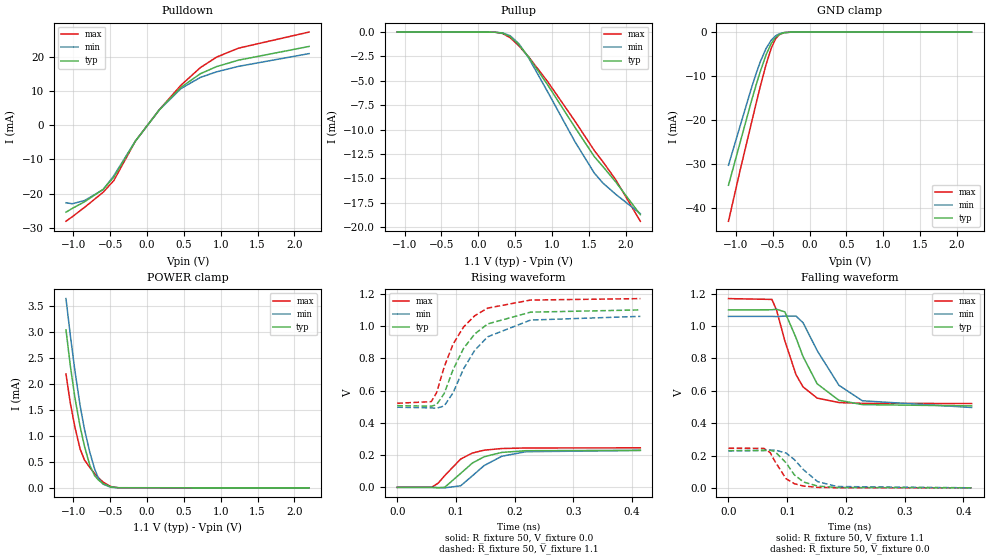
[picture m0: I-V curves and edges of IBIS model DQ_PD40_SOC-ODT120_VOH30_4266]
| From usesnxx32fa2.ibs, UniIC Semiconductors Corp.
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| DQ_PD40_SOC-ODT120_VOH30_4266
| (40 Ohm Pulldown, 120 Ohm System ODT Setting, VOH=VDDQ/3.0, 3200-4266Mbps)
[Model]   DQ_PD40_SOC-ODT120_VOH30_4266
Model_type   I/O
Vinl = 123.333mV
Vinh = 243.333mV
Vmeas = 183.333mV
Vref = 0.0mV
Cref = 0.0pF
Rref = 120.000Ohm
|   typ   min   max
|C_comp   0.834pF   0.784pF   0.884pF
C_comp_pullup   0.4170pF   0.3920pF   0.4420pF
C_comp_pulldown   0.4170pF   0.3920pF   0.4420pF
| Note: C_comp changes when the ODT circuit is enabled.
[Model Spec]
| Input threshold voltage corners
Vinl   0.1233V   0.1167V   0.1350V
Vinh   0.2433V   0.2367V   0.2550V
| Measurement voltage corners
Vmeas   0.1833V   0.1767V   0.1950V
| Timing spec test load voltage corners
Vref   0.0000V   0.0000V   0.0000V
| Dynamic Overshoot Parameters from LPDDR4 Specification
D_overshoot_ampl_h   0.30   NA   NA
D_overshoot_ampl_l   0.30   NA   NA
D_overshoot_area_h   0.1n   NA   NA
D_overshoot_area_l   0.1n   NA   NA
[Voltage Range]   1.1000V   1.0600V   1.1700V
[Pullup Reference]   1.1000V   1.0600V   1.1700V
| Junction Temperature (Ambient temp is 35C typ 95C min -40C max)
[Temperature Range]   50.0   110.0   -40.0
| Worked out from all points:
|   slope of the pulldown table from 0 to 0.165 V, typ, clamps not added: 37 ohm
|   slope of the pullup table from 0 to 0.165 V, typ, clamps not added: 39.1 kohm
|   GND clamp passes 1 mA (typ) near -0.45 V on its own axis
|   POWER clamp passes 1 mA (typ) near -0.88 V on its own axis
|   rising waveform, R_fixture 50, V_fixture 0.0: 20-80 % time 46.5ps typ, 50.5ps min, 41.5ps max; typ from 0 V to 0.23 V
|   falling waveform, R_fixture 50, V_fixture 1.1: 20-80 % time 45.3ps typ, 56.8ps min, 35.6ps max; typ from 1.1 V to 0.507 V
|   rising waveform, R_fixture 50, V_fixture 1.1: 20-80 % time 56.7ps typ, 61.2ps min, 52ps max; typ from 0.507 V to 1.1 V
|   falling waveform, R_fixture 50, V_fixture 0.0: 20-80 % time 30.4ps typ, 38.5ps min, 25.6ps max; typ from 0.23 V to 0 V
[Pulldown]
|   Voltage   I(typ)   I(min)   I(max)
-1.1V     -25.37mA   -22.63mA   -28.03mA
-1.014V   -24.28mA   -22.92mA   -26.7mA
-845.9mV  -22.31mA   -21.96mA   -23.93mA
-595.1mV  -18.71mA   -18.78mA   -19.56mA
-449.9mV  -15.13mA   -14.73mA   -16.13mA
-159.5mV  -4.688mA   -4.687mA   -4.702mA
167.2mV   4.501mA    4.462mA    4.525mA
460.9mV   11.05mA    10.69mA    11.67mA
724.9mV   15.03mA    13.95mA    16.82mA
946mV     17.11mA    15.58mA    19.88mA
1.24V     18.97mA    17.16mA    22.47mA
2.2V      22.98mA    20.89mA    27.18mA
[GND Clamp]
|   Voltage   I(typ)   I(min)   I(max)
-1.1V     -34.74mA   -30.21mA   -42.91mA
-938.3mV  -24.81mA   -21.07mA   -31.08mA
-793.1mV  -15.92mA   -12.96mA   -20.95mA
-727.1mV  -12.12mA   -9.513mA   -16.33mA
-667.7mV  -8.907mA   -6.722mA   -12.29mA
-588.5mV  -5.112mA   -3.681mA   -7.299mA
-519.2mV  -2.567mA   -1.832mA   -3.66mA
-463.1mV  -1.235mA   -898.9uA   -1.597mA
-413.6mV  -566uA     -417.2uA   -621.1uA
-344.3mV  -143.8uA   -109.4uA   -125.2uA
-232.1mV  -7.402uA   -7.068uA   -4.018uA
2.2V      0A         0A         0A
[Pullup]
|   Voltage   I(typ)   I(min)   I(max)
-1.1V     2.092uA    3.224uA    943.2nA
229.9mV   -15.02uA   -15.37uA   -15.53uA
332.2mV   -107.6uA   -89.94uA   -148.2uA
434.5mV   -465.7uA   -380.9uA   -589.6uA
553.3mV   -1.313mA   -1.213mA   -1.422mA
685.3mV   -2.584mA   -2.664mA   -2.556mA
942.7mV   -5.422mA   -6.135mA   -5.087mA
1.312V    -9.759mA   -11.23mA   -9.123mA
1.576V    -12.77mA   -14.46mA   -12.15mA
1.692V    -13.78mA   -15.47mA   -13.29mA
1.867V    -15.37mA   -16.63mA   -15.15mA
2.2V      -18.72mA   -18.61mA   -19.39mA
[POWER Clamp]
|   Voltage   I(typ)   I(min)   I(max)
-1.1V     3.033mA    3.633mA    2.184mA
-1.041V   2.345mA    2.929mA    1.625mA
-977.9mV  1.723mA    2.241mA    1.16mA
-908.6mV  1.178mA    1.582mA    747.9uA
-849.2mV  799uA      1.125mA    535.4uA
-776.6mV  434.1uA    683.3uA    390.2uA
-710.6mV  232.2uA    359.1uA    273.1uA
-657.8mV  146.8uA    178.9uA    190.7uA
-598.4mV  83.64uA    71.98uA    113uA
-496.1mV  20.06uA    12.3uA     25.72uA
-387.2mV  1.914uA    1.296uA    1.609uA
2.2V      0A         0A         0A
[Ramp]
|   typ   min   max
| 20% - 80%
dV/dt_r   137.80m/46.47p   137.36m/50.47p   146.99m/41.48p
dV/dt_f   356.03m/45.27p   337.76m/56.84p   389.18m/35.54p
| 25% - 75%
|dV/dt_r   114.84m/37.07p   114.46m/40.32p   122.49m/32.94p
|dV/dt_f   296.69m/36.12p   281.47m/45.43p   324.32m/28.29p
R_load = 50
[Rising Waveform]
R_fixture = 50
V_fixture = 0.0
|   Time   V(typ)   V(min)   V(max)
0s        169.8uV    127.4uV    131.4uV
59ps      -591.4uV   361.4uV    1.587mV
70ps      -2.672mV   -883.6uV   26.98mV
81ps      1.084mV    -2.735mV   73.35mV
108ps     86.65mV    9.855mV    175.6mV
128ps     150.9mV    71.76mV    212.9mV
148ps     189.8mV    135.3mV    230.7mV
178ps     216.7mV    192.8mV    240.9mV
219ps     227.3mV    221.1mV    244.3mV
414ps     229.8mV    229.1mV    245.1mV
[Falling Waveform]
R_fixture   = 50
V_fixture   = 1.1
V_fixture_min = 1.06
V_fixture_max = 1.17
|   Time   V(typ)   V(min)   V(max)
0s        1.1V       1.06V      1.17V
74ps      1.101V     1.06V      1.165V
82ps      1.104V     1.059V     1.097V
96ps      1.088V     1.062V     908.8mV
115ps     927.6mV    1.062V     699.9mV
127ps     811.5mV    1.021V     624.2mV
151ps     643.3mV    848.8mV    554.9mV
188ps     541.5mV    634.4mV    527.4mV
228ps     514.6mV    538.3mV    522.3mV
414ps     506.6mV    497mV      521.4mV
[Rising Waveform]
R_fixture   = 50
V_fixture   = 1.1
V_fixture_min = 1.06
V_fixture_max = 1.17
|   Time   V(typ)   V(min)   V(max)
0s        506.5mV    496.8mV    521.3mV
58ps      503.3mV    492.8mV    531.4mV
67ps      512.6mV    490.5mV    586.7mV
80ps      581.8mV    504.7mV    747mV
95ps      729.1mV    585.6mV    887.2mV
113ps     861.7mV    735.1mV    994.5mV
132ps     950.7mV    849.8mV    1.064V
154ps     1.013V     933.3mV    1.111V
227ps     1.086V     1.037V     1.161V
414ps     1.1V       1.06V      1.17V
[Falling Waveform]
R_fixture = 50
V_fixture = 0.0
|   Time   V(typ)   V(min)   V(max)
0s        229.9mV    229.2mV    245.2mV
60ps      232.6mV    230mV      244.3mV
71ps      232.3mV    233.1mV    217.7mV
79ps      224.6mV    234mV      164.4mV
98ps      155.3mV    215.2mV    56.71mV
112ps     81.04mV    175.4mV    26.17mV
128ps     35.78mV    111.1mV    10.99mV
152ps     10.71mV    38.17mV    3.147mV
185ps     2.325mV    8.199mV    686.1uV
414ps     237.5uV    227.7uV    152.8uV
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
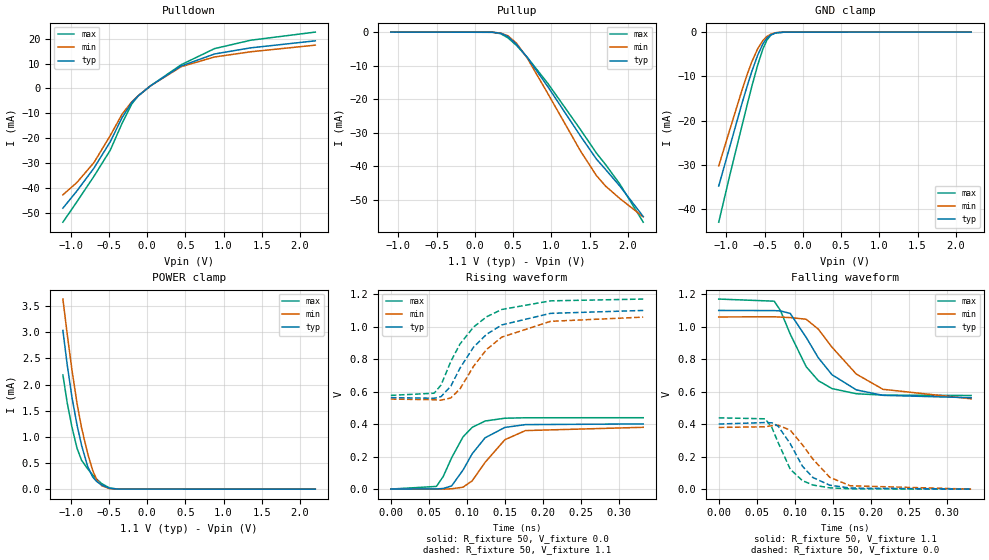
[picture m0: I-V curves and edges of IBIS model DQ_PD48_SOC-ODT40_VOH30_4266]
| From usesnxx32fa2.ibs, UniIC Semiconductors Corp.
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| DQ_PD48_SOC-ODT40_VOH30_4266
| (48 Ohm Pulldown, 40 Ohm System ODT Setting, VOH=VDDQ/3.0, 3200-4266Mbps)
[Model]   DQ_PD48_SOC-ODT40_VOH30_4266
Model_type   I/O
Vinl = 123.333mV
Vinh = 243.333mV
Vmeas = 183.333mV
Vref = 0.0mV
Cref = 0.0pF
Rref = 40.000Ohm
|   typ   min   max
|C_comp   0.834pF   0.784pF   0.884pF
C_comp_pullup   0.4170pF   0.3920pF   0.4420pF
C_comp_pulldown   0.4170pF   0.3920pF   0.4420pF
| Note: C_comp changes when the ODT circuit is enabled.
[Model Spec]
| Input threshold voltage corners
Vinl   0.1233V   0.1167V   0.1350V
Vinh   0.2433V   0.2367V   0.2550V
| Measurement voltage corners
Vmeas   0.1833V   0.1767V   0.1950V
| Timing spec test load voltage corners
Vref   0.0000V   0.0000V   0.0000V
| Dynamic Overshoot Parameters from LPDDR4 Specification
D_overshoot_ampl_h   0.30   NA   NA
D_overshoot_ampl_l   0.30   NA   NA
D_overshoot_area_h   0.1n   NA   NA
D_overshoot_area_l   0.1n   NA   NA
[Voltage Range]   1.1000V   1.0600V   1.1700V
[Pullup Reference]   1.1000V   1.0600V   1.1700V
| Junction Temperature (Ambient temp is 35C typ 95C min -40C max)
[Temperature Range]   50.0   110.0   -40.0
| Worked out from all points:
|   slope of the pulldown table from 0 to 0.165 V, typ, clamps not added: 43.8 ohm
|   slope of the pullup table from 0 to 0.165 V, typ, clamps not added: 13 kohm
|   GND clamp passes 1 mA (typ) near -0.45 V on its own axis
|   POWER clamp passes 1 mA (typ) near -0.88 V on its own axis
|   rising waveform, R_fixture 50, V_fixture 0.0: 20-80 % time 34.7ps typ, 38.8ps min, 30.2ps max; typ from 0.001 V to 0.401 V
|   falling waveform, R_fixture 50, V_fixture 1.1: 20-80 % time 49.3ps typ, 61.2ps min, 39.2ps max; typ from 1.1 V to 0.563 V
|   rising waveform, R_fixture 50, V_fixture 1.1: 20-80 % time 55.5ps typ, 58.1ps min, 51.7ps max; typ from 0.563 V to 1.1 V
|   falling waveform, R_fixture 50, V_fixture 0.0: 20-80 % time 32.5ps typ, 40ps min, 27.6ps max; typ from 0.401 V to 0.001 V
[Pulldown]
|   Voltage   I(typ)   I(min)   I(max)
-1.1V     -48.22mA   -42.85mA   -53.87mA
-918.5mV  -41.36mA   -37.93mA   -45.72mA
-694.1mV  -32.1mA    -29.86mA   -35.4mA
-479.6mV  -21.39mA   -18.92mA   -24.8mA
-324.5mV  -11.65mA   -10.29mA   -13.91mA
-199.1mV  -5.64mA    -5.359mA   -6.219mA
-113.3mV  -2.927mA   -2.884mA   -2.961mA
45.1mV    1.047mA    1.044mA    1.045mA
447.7mV   9.071mA    8.78mA     9.581mA
883.3mV   13.89mA    12.68mA    16.05mA
1.355V    16.35mA    14.77mA    19.42mA
2.2V      19.18mA    17.44mA    22.7mA
[GND Clamp]
|   Voltage   I(typ)   I(min)   I(max)
-1.1V     -34.74mA   -30.21mA   -42.91mA
-941.6mV  -25.02mA   -21.26mA   -31.32mA
-799.7mV  -16.31mA   -13.32mA   -21.42mA
-723.8mV  -11.94mA   -9.348mA   -16.1mA
-667.7mV  -8.907mA   -6.722mA   -12.29mA
-591.8mV  -5.255mA   -3.789mA   -7.493mA
-522.5mV  -2.665mA   -1.902mA   -3.811mA
-469.7mV  -1.357mA   -985.1uA   -1.788mA
-416.9mV  -596.7uA   -440.1uA   -664.7uA
-354.2mV  -178.1uA   -134.8uA   -159.9uA
-235.4mV  -8.186uA   -7.681uA   -4.491uA
2.2V      0A         0A         0A
[Pullup]
|   Voltage   I(typ)   I(min)   I(max)
-1.1V     6.275uA    9.671uA    2.829uA
229.9mV   -45.14uA   -46.16uA   -46.64uA
335.5mV   -340.5uA   -282.4uA   -468.8uA
431.2mV   -1.333mA   -1.089mA   -1.693mA
543.4mV   -3.63mA    -3.312mA   -3.978mA
685.3mV   -7.607mA   -7.806mA   -7.548mA
955.9mV   -16.38mA   -18.46mA   -15.4mA
1.378V    -30.95mA   -35.41mA   -29.04mA
1.589V    -37.92mA   -42.84mA   -36.13mA
1.708V    -41mA      -45.97mA   -39.55mA
1.893V    -45.92mA   -49.65mA   -45.31mA
2.2V      -55.05mA   -55.15mA   -56.74mA
[POWER Clamp]
|   Voltage   I(typ)   I(min)   I(max)
-1.1V     3.033mA    3.633mA    2.184mA
-1.044V   2.381mA    2.967mA    1.653mA
-981.2mV  1.753mA    2.275mA    1.183mA
-915.2mV  1.224mA    1.639mA    781.4uA
-855.8mV  837.6uA    1.171mA    552.2uA
-776.6mV  434.3uA    683.3uA    390.2uA
-710.6mV  232.2uA    359uA      273.1uA
-657.8mV  146.8uA    178.8uA    190.6uA
-591.8mV  77.9uA     64.81uA    105.5uA
-489.5mV  17.75uA    10.81uA    22.48uA
-380.6mV  1.603uA    1.131uA    1.341uA
2.2V      0A         0A         0A
[Ramp]
|   typ   min   max
| 20% - 80%
dV/dt_r   240.28m/34.75p   227.83m/38.76p   263.33m/30.20p
dV/dt_f   322.12m/49.32p   302.17m/61.19p   355.99m/39.15p
| 25% - 75%
|dV/dt_r   200.24m/27.67p   189.86m/30.88p   219.44m/23.94p
|dV/dt_f   268.43m/39.31p   251.80m/48.83p   296.66m/31.17p
R_load = 50
[Rising Waveform]
R_fixture = 50
V_fixture = 0.0
|   Time   V(typ)   V(min)   V(max)
0s        619.1uV    536.6uV    450.1uV
60ps      1.042mV    -84.49uV   16.73mV
69ps      4.083mV    -175.8uV   78.14mV
80ps      19.77mV    2.236mV    193.1mV
95ps      117.6mV    11.96mV    321.6mV
107ps     217.2mV    51mV       379.9mV
124ps     315.7mV    164.6mV    418.9mV
150ps     379.5mV    303.8mV    436.1mV
177ps     396.8mV    360.1mV    439mV
332ps     401.1mV    380.3mV    439.3mV
[Falling Waveform]
R_fixture   = 50
V_fixture   = 1.1
V_fixture_min = 1.06
V_fixture_max = 1.17
|   Time   V(typ)   V(min)   V(max)
0s        1.1V       1.06V      1.17V
73ps      1.099V     1.061V     1.157V
81ps      1.097V     1.059V     1.101V
94ps      1.082V     1.056V     954.9mV
115ps     934.4mV    1.046V     754.1mV
131ps     808.8mV    985mV      668.1mV
149ps     704.4mV    873.8mV    619.1mV
181ps     611.3mV    708.5mV    587.5mV
216ps     577.7mV    614.8mV    579.2mV
332ps     563.1mV    556.4mV    576.7mV
[Rising Waveform]
R_fixture   = 50
V_fixture   = 1.1
V_fixture_min = 1.06
V_fixture_max = 1.17
|   Time   V(typ)   V(min)   V(max)
0s        562.8mV    553.9mV    576.6mV
57ps      559mV      549.8mV    590mV
66ps      568.8mV    547mV      640mV
79ps      633.7mV    560.8mV    785.9mV
91ps      744.4mV    616.5mV    892.7mV
109ps     874.4mV    756.8mV    997.7mV
126ps     952.2mV    859mV      1.06V
146ps     1.01V      934.9mV    1.105V
210ps     1.081V     1.032V     1.158V
332ps     1.099V     1.058V     1.169V
[Falling Waveform]
R_fixture = 50
V_fixture = 0.0
|   Time   V(typ)   V(min)   V(max)
0s        401.2mV    380.4mV    439.4mV
61ps      410.3mV    384.3mV    433.3mV
70ps      408.7mV    391.1mV    378.8mV
78ps      388.8mV    394mV      288.8mV
94ps      280.8mV    363.6mV    123.8mV
110ps     142.2mV    274.1mV    53.17mV
124ps     71.85mV    184.8mV    25.79mV
146ps     24.83mV    73.47mV    8.582mV
173ps     7.298mV    21.37mV    2.537mV
332ps     679.4uV    647.7uV    471uV
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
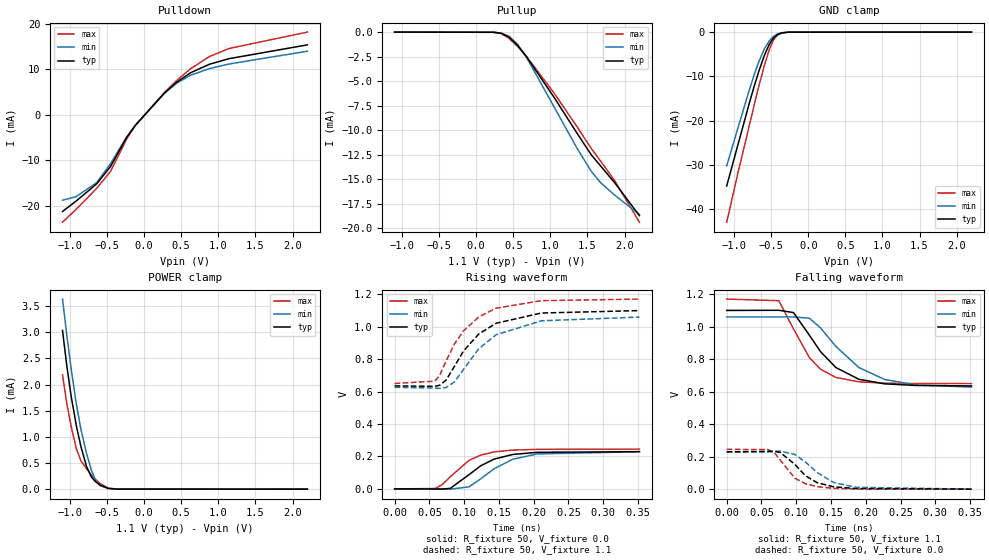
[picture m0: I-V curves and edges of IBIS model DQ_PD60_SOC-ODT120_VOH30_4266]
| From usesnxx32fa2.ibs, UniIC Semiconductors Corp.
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| DQ_PD60_SOC-ODT120_VOH30_4266
| (60 Ohm Pulldown, 120 Ohm System ODT Setting, VOH=VDDQ/3.0, 3200-4266Mbps)
[Model]   DQ_PD60_SOC-ODT120_VOH30_4266
Model_type   I/O
Vinl = 123.333mV
Vinh = 243.333mV
Vmeas = 183.333mV
Vref = 0.0mV
Cref = 0.0pF
Rref = 120.000Ohm
|   typ   min   max
|C_comp   0.834pF   0.784pF   0.884pF
C_comp_pullup   0.4170pF   0.3920pF   0.4420pF
C_comp_pulldown   0.4170pF   0.3920pF   0.4420pF
| Note: C_comp changes when the ODT circuit is enabled.
[Model Spec]
| Input threshold voltage corners
Vinl   0.1233V   0.1167V   0.1350V
Vinh   0.2433V   0.2367V   0.2550V
| Measurement voltage corners
Vmeas   0.1833V   0.1767V   0.1950V
| Timing spec test load voltage corners
Vref   0.0000V   0.0000V   0.0000V
| Dynamic Overshoot Parameters from LPDDR4 Specification
D_overshoot_ampl_h   0.30   NA   NA
D_overshoot_ampl_l   0.30   NA   NA
D_overshoot_area_h   0.1n   NA   NA
D_overshoot_area_l   0.1n   NA   NA
[Voltage Range]   1.1000V   1.0600V   1.1700V
[Pullup Reference]   1.1000V   1.0600V   1.1700V
| Junction Temperature (Ambient temp is 35C typ 95C min -40C max)
[Temperature Range]   50.0   110.0   -40.0
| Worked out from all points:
|   slope of the pulldown table from 0 to 0.165 V, typ, clamps not added: 55 ohm
|   slope of the pullup table from 0 to 0.165 V, typ, clamps not added: 39.2 kohm
|   GND clamp passes 1 mA (typ) near -0.45 V on its own axis
|   POWER clamp passes 1 mA (typ) near -0.88 V on its own axis
|   rising waveform, R_fixture 50, V_fixture 0.0: 20-80 % time 47.1ps typ, 51.2ps min, 41.8ps max; typ from 0 V to 0.23 V
|   falling waveform, R_fixture 50, V_fixture 1.1: 20-80 % time 53.3ps typ, 65ps min, 42.9ps max; typ from 1.1 V to 0.635 V
|   rising waveform, R_fixture 50, V_fixture 1.1: 20-80 % time 56.3ps typ, 60.3ps min, 52.3ps max; typ from 0.635 V to 1.1 V
|   falling waveform, R_fixture 50, V_fixture 0.0: 20-80 % time 35ps typ, 42.4ps min, 30.4ps max; typ from 0.23 V to 0 V
[Pulldown]
|   Voltage   I(typ)   I(min)   I(max)
-1.1V     -21.25mA   -18.78mA   -23.61mA
-918.5mV  -19mA      -18.02mA   -20.81mA
-638mV    -15.16mA   -14.89mA   -16.16mA
-453.2mV  -11.38mA   -10.78mA   -12.45mA
-235.4mV  -4.998mA   -4.872mA   -5.302mA
-116.6mV  -2.307mA   -2.303mA   -2.296mA
276.1mV   4.816mA    4.74mA     4.918mA
437.8mV   7.121mA    6.906mA    7.497mA
625.9mV   9.213mA    8.675mA    10.1mA
880mV     11.08mA    10.12mA    12.78mA
1.144V    12.31mA    11.14mA    14.54mA
2.2V      15.34mA    13.95mA    18.15mA
[GND Clamp]
|   Voltage   I(typ)   I(min)   I(max)
-1.1V     -34.74mA   -30.21mA   -42.91mA
-948.2mV  -25.43mA   -21.63mA   -31.79mA
-793.1mV  -15.92mA   -12.96mA   -20.95mA
-723.8mV  -11.93mA   -9.348mA   -16.1mA
-664.4mV  -8.736mA   -6.578mA   -12.07mA
-591.8mV  -5.254mA   -3.789mA   -7.492mA
-525.8mV  -2.766mA   -1.974mA   -3.964mA
-469.7mV  -1.356mA   -986uA     -1.787mA
-416.9mV  -597.3uA   -440.2uA   -665.1uA
-357.5mV  -190.9uA   -145.2uA   -173.7uA
-265.1mV  -19.48uA   -16.92uA   -12.31uA
2.2V      0A         0A         0A
[Pullup]
|   Voltage   I(typ)   I(min)   I(max)
-1.1V     2.092uA    3.224uA    943.2nA
233.2mV   -16.12uA   -16.27uA   -16.87uA
335.5mV   -114uA     -94.77uA   -157uA
441.1mV   -501.8uA   -411.9uA   -628.2uA
556.6mV   -1.342mA   -1.243mA   -1.448mA
678.7mV   -2.516mA   -2.582mA   -2.496mA
1.055V    -6.719mA   -7.703mA   -6.276mA
1.362V    -10.35mA   -11.89mA   -9.685mA
1.553V    -12.54mA   -14.22mA   -11.89mA
1.675V    -13.64mA   -15.35mA   -13.14mA
1.867V    -15.37mA   -16.63mA   -15.15mA
2.2V      -18.72mA   -18.61mA   -19.39mA
[POWER Clamp]
|   Voltage   I(typ)   I(min)   I(max)
-1.1V     3.033mA    3.633mA    2.184mA
-1.041V   2.345mA    2.929mA    1.625mA
-984.5mV  1.782mA    2.31mA     1.205mA
-911.9mV  1.201mA    1.61mA     764.1uA
-852.5mV  818.2uA    1.148mA    543.5uA
-776.6mV  434.1uA    683.3uA    390.2uA
-710.6mV  232.2uA    359uA      273.1uA
-657.8mV  146.8uA    178.8uA    190.6uA
-595.1mV  80.78uA    68.3uA     109.2uA
-482.9mV  15.69uA    9.499uA    19.51uA
-364.1mV  1.098uA    819.7nA    867nA
2.2V      0A         0A         0A
[Ramp]
|   typ   min   max
| 20% - 80%
dV/dt_r   137.76m/47.06p   137.31m/51.22p   146.97m/41.83p
dV/dt_f   278.79m/53.28p   259.05m/65.05p   312.06m/42.98p
| 25% - 75%
|dV/dt_r   114.80m/37.54p   114.43m/40.90p   122.47m/33.22p
|dV/dt_f   232.32m/42.47p   215.88m/51.80p   260.05m/34.24p
R_load = 50
[Rising Waveform]
R_fixture = 50
V_fixture = 0.0
|   Time   V(typ)   V(min)   V(max)
0s        225.3uV    184.2uV    168.8uV
58ps      -235.5uV   253.1uV    2.338mV
68ps      -877.8uV   -528.5uV   24.86mV
80ps      3.421mV    -1.491mV   74.85mV
107ps     87.78mV    12.87mV    175.8mV
124ps     143.1mV    62.63mV    208.8mV
143ps     183.7mV    124.3mV    228.2mV
170ps     212.5mV    182.9mV    239.5mV
205ps     225.5mV    215.6mV    243.8mV
352ps     229.8mV    229mV      245.1mV
[Falling Waveform]
R_fixture   = 50
V_fixture   = 1.1
V_fixture_min = 1.06
V_fixture_max = 1.17
|   Time   V(typ)   V(min)   V(max)
0s        1.1V       1.06V      1.17V
75ps      1.101V     1.06V      1.16V
96ps      1.087V     1.06V      986.5mV
119ps     947mV      1.052V     809.1mV
135ps     846.2mV    992.1mV    738mV
157ps     748.6mV    878.7mV    687.9mV
190ps     676.5mV    748.8mV    660.6mV
227ps     648.3mV    675.4mV    652.5mV
272ps     638.4mV    641.6mV    650.3mV
352ps     635.4mV    628.2mV    649.9mV
[Rising Waveform]
R_fixture   = 50
V_fixture   = 1.1
V_fixture_min = 1.06
V_fixture_max = 1.17
|   Time   V(typ)   V(min)   V(max)
0s        635mV      626.1mV    649.8mV
58ps      632.2mV    621.6mV    664.1mV
65ps      639.4mV    619.9mV    702.1mV
74ps      670.3mV    624.7mV    787.4mV
86ps      755.2mV    659.1mV    892.9mV
99ps      849.6mV    735.8mV    973.7mV
121ps     954.6mV    864mV      1.06V
146ps     1.021V     950.2mV    1.114V
211ps     1.084V     1.036V     1.16V
352ps     1.099V     1.059V     1.17V
[Falling Waveform]
R_fixture = 50
V_fixture = 0.0
|   Time   V(typ)   V(min)   V(max)
0s        229.9mV    229.2mV    245.2mV
59ps      232.6mV    229.9mV    244.5mV
69ps      232.8mV    232.8mV    222.5mV
77ps      226.2mV    234.3mV    179.5mV
98ps      152.9mV    213.6mV    67.75mV
113ps     83.32mV    168mV      33.78mV
130ps     40.1mV     102.6mV    15.5mV
154ps     14.49mV    40.75mV    5.262mV
186ps     3.913mV    11.43mV    1.37mV
352ps     303.3uV    314.6uV    191.7uV
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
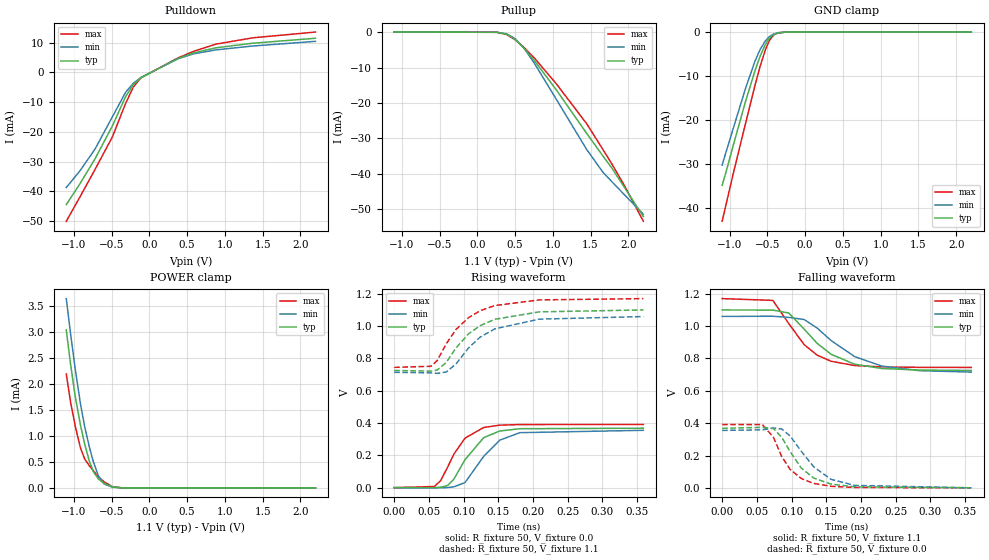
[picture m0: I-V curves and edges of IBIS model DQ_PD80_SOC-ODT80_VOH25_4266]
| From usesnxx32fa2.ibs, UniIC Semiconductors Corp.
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| DQ_PD80_SOC-ODT80_VOH25_4266
| (80 Ohm Pulldown, 80 Ohm System ODT Setting, VOH=VDDQ/2.5, 3200-4266Mbps)
[Model]   DQ_PD80_SOC-ODT80_VOH25_4266
Model_type   I/O
Vinl = 160.000mV
Vinh = 280.000mV
Vmeas = 220.000mV
Vref = 0.0mV
Cref = 0.0pF
Rref = 80.000Ohm
|   typ   min   max
|C_comp   0.834pF   0.784pF   0.884pF
C_comp_pullup   0.4170pF   0.3920pF   0.4420pF
C_comp_pulldown   0.4170pF   0.3920pF   0.4420pF
| Note: C_comp changes when the ODT circuit is enabled.
[Model Spec]
| Input threshold voltage corners
Vinl   0.1600V   0.1520V   0.1740V
Vinh   0.2800V   0.2720V   0.2940V
| Measurement voltage corners
Vmeas   0.2200V   0.2120V   0.2340V
| Timing spec test load voltage corners
Vref   0.0000V   0.0000V   0.0000V
| Dynamic Overshoot Parameters from LPDDR4 Specification
D_overshoot_ampl_h   0.30   NA   NA
D_overshoot_ampl_l   0.30   NA   NA
D_overshoot_area_h   0.1n   NA   NA
D_overshoot_area_l   0.1n   NA   NA
[Voltage Range]   1.1000V   1.0600V   1.1700V
[Pullup Reference]   1.1000V   1.0600V   1.1700V
| Junction Temperature (Ambient temp is 35C typ 95C min -40C max)
[Temperature Range]   50.0   110.0   -40.0
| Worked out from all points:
|   slope of the pulldown table from 0 to 0.165 V, typ, clamps not added: 73.8 ohm
|   slope of the pullup table from 0 to 0.165 V, typ, clamps not added: 17.5 kohm
|   GND clamp passes 1 mA (typ) near -0.45 V on its own axis
|   POWER clamp passes 1 mA (typ) near -0.88 V on its own axis
|   rising waveform, R_fixture 50, V_fixture 0.0: 20-80 % time 35.1ps typ, 38.9ps min, 32ps max; typ from 0.001 V to 0.368 V
|   falling waveform, R_fixture 50, V_fixture 1.1: 20-80 % time 58ps typ, 69ps min, 47.3ps max; typ from 1.1 V to 0.726 V
|   rising waveform, R_fixture 50, V_fixture 1.1: 20-80 % time 54.9ps typ, 56.7ps min, 51.7ps max; typ from 0.726 V to 1.1 V
|   falling waveform, R_fixture 50, V_fixture 0.0: 20-80 % time 38.3ps typ, 44.3ps min, 32.9ps max; typ from 0.368 V to 0.001 V
[Pulldown]
|   Voltage   I(typ)   I(min)   I(max)
-1.1V     -44.48mA   -38.75mA   -50.1mA
-921.8mV  -37.58mA   -33.22mA   -42.04mA
-720.5mV  -29.14mA   -25.86mA   -32.73mA
-489.5mV  -18.03mA   -14.96mA   -21.71mA
-314.6mV  -8.178mA   -6.693mA   -10.48mA
-212.3mV  -4.114mA   -3.666mA   -4.927mA
-110mV    -1.768mA   -1.705mA   -1.812mA
381.7mV   4.717mA    4.613mA    4.889mA
589.6mV   6.577mA    6.251mA    7.117mA
883.3mV   8.277mA    7.574mA    9.509mA
1.368V    9.806mA    8.868mA    11.62mA
2.2V      11.48mA    10.44mA    13.57mA
[GND Clamp]
|   Voltage   I(typ)   I(min)   I(max)
-1.1V     -34.75mA   -30.2mA    -42.92mA
-1.05V    -31.86mA   -27.33mA   -39.27mA
-948.2mV  -25.44mA   -21.62mA   -31.8mA
-789.8mV  -15.73mA   -12.78mA   -20.73mA
-664.4mV  -8.74mA    -6.576mA   -12.08mA
-595.1mV  -5.401mA   -3.898mA   -7.695mA
-525.8mV  -2.768mA   -1.974mA   -3.966mA
-473mV    -1.422mA   -1.031mA   -1.89mA
-416.9mV  -600.9uA   -440.5uA   -665.8uA
-357.5mV  -192.8uA   -144.2uA   -174uA
-248.6mV  -12.2uA    -10.93uA   -7.146uA
2.2V      0A         0A         0A
[Pullup]
|   Voltage   I(typ)   I(min)   I(max)
-1.1V     4.106uA    7.431uA    1.361uA
259.6mV   -60.57uA   -59.49uA   -61.51uA
388.3mV   -576.6uA   -480.7uA   -687.8uA
500.5mV   -2.04mA    -1.831mA   -2.142mA
619.3mV   -4.529mA   -4.567mA   -4.328mA
754.6mV   -7.982mA   -8.738mA   -7.279mA
1.042V    -16.16mA   -18.8mA    -14.47mA
1.448V    -28.55mA   -33.09mA   -25.83mA
1.662V    -34.9mA    -39.5mA    -33.05mA
1.788V    -38.54mA   -42.33mA   -37.4mA
1.943V    -43.63mA   -45.77mA   -43.12mA
2.2V      -52.05mA   -51.39mA   -53.39mA
[POWER Clamp]
|   Voltage   I(typ)   I(min)   I(max)
-1.1V     3.033mA    3.633mA    2.184mA
-1.044V   2.381mA    2.967mA    1.653mA
-981.2mV  1.752mA    2.276mA    1.183mA
-911.9mV  1.201mA    1.611mA    764.5uA
-855.8mV  837.8uA    1.172mA    552.1uA
-796.4mV  521.2uA    795.3uA    427.2uA
-743.6mV  316uA      510.6uA    330.1uA
-674.3mV  169.2uA    226uA      215.1uA
-598.4mV  83.65uA    71.95uA    113.1uA
-486.2mV  16.75uA    10.13uA    20.98uA
-367.4mV  1.201uA    871.3nA    948.2nA
2.2V      0A         0A         0A
[Ramp]
|   typ   min   max
| 20% - 80%
dV/dt_r   220.51m/35.12p   212.86m/38.87p   234.61m/31.95p
dV/dt_f   224.46m/57.99p   206.41m/68.96p   255.16m/47.24p
| 25% - 75%
|dV/dt_r   183.76m/27.95p   177.38m/30.96p   195.51m/25.38p
|dV/dt_f   187.05m/46.15p   172.01m/54.89p   212.64m/37.50p
R_load = 50
[Rising Waveform]
R_fixture = 50
V_fixture = 0.0
|   Time   V(typ)   V(min)   V(max)
0s        836.2uV    685.8uV    613uV
58ps      506.9uV    -45.3uV    7.832mV
67ps      3.418mV    -439.2uV   44.62mV
77ps      13.93mV    1.482mV    127.9mV
86ps      53.46mV    5.803mV    207.8mV
102ps     173.7mV    31.95mV    306.9mV
129ps     310.1mV    194.6mV    373mV
152ps     351mV      294.2mV    387.2mV
181ps     365.2mV    340.8mV    391mV
359ps     368.4mV    355.4mV    391.6mV
[Falling Waveform]
R_fixture   = 50
V_fixture   = 1.1
V_fixture_min = 1.06
V_fixture_max = 1.17
|   Time   V(typ)   V(min)   V(max)
0s        1.1V       1.06V      1.17V
73ps      1.099V     1.061V     1.159V
96ps      1.081V     1.054V     1.016V
118ps     982.4mV    1.041V     886.3mV
137ps     893.3mV    987.8mV    820.4mV
157ps     825.9mV    911.1mV    782.9mV
191ps     764.5mV    811.4mV    756.4mV
230ps     738.2mV    753.4mV    747.8mV
284ps     728.3mV    724.8mV    745.2mV
359ps     725.9mV    716mV      744.7mV
[Rising Waveform]
R_fixture   = 50
V_fixture   = 1.1
V_fixture_min = 1.06
V_fixture_max = 1.17
|   Time   V(typ)   V(min)   V(max)
0s        725.5mV    714.2mV    744.7mV
53ps      721.5mV    710.7mV    751.4mV
62ps      728.2mV    707.5mV    787.3mV
75ps      774.9mV    716.2mV    890.4mV
89ps      864.6mV    765.3mV    979mV
107ps     951.9mV    864.6mV    1.052V
124ps     1.003V     932.4mV    1.095V
145ps     1.042V     982.9mV    1.127V
209ps     1.088V     1.043V     1.162V
359ps     1.1V       1.059V     1.17V
[Falling Waveform]
R_fixture = 50
V_fixture = 0.0
|   Time   V(typ)   V(min)   V(max)
0s        368.5mV    355.6mV    391.7mV
58ps      374.4mV    359mV      391.8mV
74ps      367mV      370.3mV    313.1mV
86ps      312.3mV    364.2mV    192.4mV
98ps      224.6mV    321.2mV    114.5mV
114ps     122.9mV    226.6mV    58.43mV
132ps     61.05mV    130.3mV    27.72mV
157ps     23.47mV    52.97mV    10.16mV
191ps     6.912mV    15.81mV    2.96mV
359ps     897.5uV    805.7uV    637uV
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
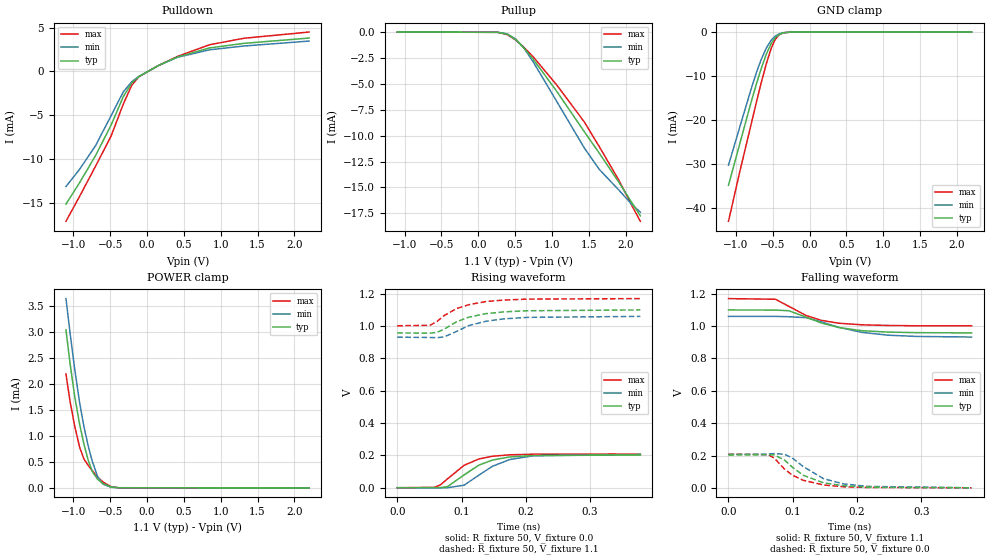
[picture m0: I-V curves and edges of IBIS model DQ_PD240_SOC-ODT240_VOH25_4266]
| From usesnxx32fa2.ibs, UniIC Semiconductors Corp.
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| DQ_PD240_SOC-ODT240_VOH25_4266
| (240 Ohm Pulldown, 240 Ohm System ODT Setting, VOH=VDDQ/2.5, 3200-4266Mbps)
[Model]   DQ_PD240_SOC-ODT240_VOH25_4266
Model_type   I/O
Vinl = 160.000mV
Vinh = 280.000mV
Vmeas = 220.000mV
Vref = 0.0mV
Cref = 0.0pF
Rref = 240.000Ohm
|   typ   min   max
|C_comp   0.834pF   0.784pF   0.884pF
C_comp_pullup   0.4170pF   0.3920pF   0.4420pF
C_comp_pulldown   0.4170pF   0.3920pF   0.4420pF
| Note: C_comp changes when the ODT circuit is enabled.
[Model Spec]
| Input threshold voltage corners
Vinl   0.1600V   0.1520V   0.1740V
Vinh   0.2800V   0.2720V   0.2940V
| Measurement voltage corners
Vmeas   0.2200V   0.2120V   0.2340V
| Timing spec test load voltage corners
Vref   0.0000V   0.0000V   0.0000V
| Dynamic Overshoot Parameters from LPDDR4 Specification
D_overshoot_ampl_h   0.30   NA   NA
D_overshoot_ampl_l   0.30   NA   NA
D_overshoot_area_h   0.1n   NA   NA
D_overshoot_area_l   0.1n   NA   NA
[Voltage Range]   1.1000V   1.0600V   1.1700V
[Pullup Reference]   1.1000V   1.0600V   1.1700V
| Junction Temperature (Ambient temp is 35C typ 95C min -40C max)
[Temperature Range]   50.0   110.0   -40.0
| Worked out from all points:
|   slope of the pulldown table from 0 to 0.165 V, typ, clamps not added: 225 ohm
|   slope of the pullup table from 0 to 0.165 V, typ, clamps not added: 53.3 kohm
|   GND clamp passes 1 mA (typ) near -0.45 V on its own axis
|   POWER clamp passes 1 mA (typ) near -0.88 V on its own axis
|   rising waveform, R_fixture 50, V_fixture 0.0: 20-80 % time 47.9ps typ, 52.4ps min, 44.1ps max; typ from 0 V to 0.203 V
|   falling waveform, R_fixture 50, V_fixture 1.1: 20-80 % time 66.3ps typ, 74.9ps min, 56.7ps max; typ from 1.1 V to 0.958 V
|   rising waveform, R_fixture 50, V_fixture 1.1: 20-80 % time 54.5ps typ, 56.7ps min, 51.5ps max; typ from 0.958 V to 1.1 V
|   falling waveform, R_fixture 50, V_fixture 0.0: 20-80 % time 48.5ps typ, 53.2ps min, 44.1ps max; typ from 0.203 V to 0.001 V
[Pulldown]
|   Voltage   I(typ)   I(min)   I(max)
-1.1V     -15.15mA   -13.14mA   -17.11mA
-918.5mV  -12.75mA   -11.21mA   -14.32mA
-697.4mV  -9.593mA   -8.457mA   -10.8mA
-489.5mV  -6.154mA   -5.079mA   -7.413mA
-321.2mV  -2.871mA   -2.319mA   -3.711mA
-209mV    -1.33mA    -1.185mA   -1.6mA
-113.3mV  -600.2uA   -577.7uA   -617.2uA
160.6mV   704.8uA    700.5uA    702.8uA
411.4mV   1.648mA    1.612mA    1.708mA
847mV     2.685mA    2.471mA    3.047mA
1.319V    3.214mA    2.91mA     3.796mA
2.2V      3.814mA    3.471mA    4.502mA
[GND Clamp]
|   Voltage   I(typ)   I(min)   I(max)
-1.1V     -34.75mA   -30.2mA    -42.92mA
-944.9mV  -25.23mA   -21.44mA   -31.56mA
-793.1mV  -15.92mA   -12.96mA   -20.97mA
-720.5mV  -11.75mA   -9.183mA   -15.88mA
-661.1mV  -8.569mA   -6.434mA   -11.86mA
-585.2mV  -4.973mA   -3.574mA   -7.112mA
-519.2mV  -2.565mA   -1.835mA   -3.664mA
-469.7mV  -1.356mA   -986.7uA   -1.789mA
-413.6mV  -565.4uA   -417.9uA   -621uA
-357.5mV  -191.7uA   -145.3uA   -173.6uA
-258.5mV  -16.08uA   -14.25uA   -9.843uA
2.2V      0A         0A         0A
[Pullup]
|   Voltage   I(typ)   I(min)   I(max)
-1.1V     1.369uA    2.477uA    453.9nA
266.2mV   -23.1uA    -22.05uA   -23.94uA
391.6mV   -202uA     -167.5uA   -241uA
510.4mV   -747.3uA   -678.3uA   -775.6uA
622.6mV   -1.559mA   -1.581mA   -1.482mA
744.7mV   -2.615mA   -2.864mA   -2.382mA
1.062V    -5.688mA   -6.655mA   -5.078mA
1.438V    -9.601mA   -11.17mA   -8.662mA
1.642V    -11.68mA   -13.25mA   -11.05mA
1.91V     -14.51mA   -15.26mA   -14.32mA
2.094V    -16.57mA   -16.71mA   -16.87mA
2.2V      -17.73mA   -17.38mA   -18.26mA
[POWER Clamp]
|   Voltage   I(typ)   I(min)   I(max)
-1.1V     3.033mA    3.633mA    2.184mA
-1.044V   2.381mA    2.967mA    1.653mA
-981.2mV  1.753mA    2.276mA    1.184mA
-915.2mV  1.223mA    1.639mA    781.3uA
-855.8mV  837.7uA    1.171mA    552.2uA
-799.7mV  536.7uA    814uA      433.4uA
-743.6mV  315.8uA    510.5uA    330.1uA
-671mV    164.5uA    215.9uA    210.1uA
-598.4mV  83.65uA    71.98uA    113.1uA
-492.8mV  18.92uA    11.61uA    24.02uA
-383.9mV  1.745uA    1.219uA    1.463uA
2.2V      0A         0A         0A
[Ramp]
|   typ   min   max
| 20% - 80%
dV/dt_r   121.42m/47.94p   123.72m/52.39p   125.24m/44.09p
dV/dt_f   85.15m/66.09p   76.65m/74.92p   100.80m/56.89p
| 25% - 75%
|dV/dt_r   101.18m/38.14p   103.10m/41.71p   104.36m/35.05p
|dV/dt_f   70.96m/52.57p   63.87m/59.65p   84.00m/45.16p
R_load = 50
[Rising Waveform]
R_fixture = 50
V_fixture = 0.0
|   Time   V(typ)   V(min)   V(max)
0s        392.2uV    320.6uV    288.3uV
58ps      62.61uV    3.595uV    2.834mV
67ps      1.022mV    -297.3uV   17.64mV
78ps      6.794mV    354.8uV    54.71mV
104ps     79.62mV    16.07mV    139.2mV
127ps     140.3mV    78.39mV    178.2mV
148ps     171.6mV    132.9mV    194.9mV
175ps     190.8mV    174.8mV    204mV
212ps     199.7mV    197.9mV    207.8mV
378ps     202.8mV    206.5mV    209mV
[Falling Waveform]
R_fixture   = 50
V_fixture   = 1.1
V_fixture_min = 1.06
V_fixture_max = 1.17
|   Time   V(typ)   V(min)   V(max)
0s        1.1V       1.06V      1.17V
73ps      1.099V     1.06V      1.166V
94ps      1.095V     1.058V     1.122V
121ps     1.055V     1.052V     1.065V
144ps     1.02V      1.027V     1.036V
171ps     991.4mV    992.9mV    1.018V
207ps     971.8mV    961.6mV    1.008V
248ps     962.9mV    943.9mV    1.004V
293ps     959.5mV    936.1mV    1.002V
378ps     958.1mV    932.3mV    1.002V
[Rising Waveform]
R_fixture   = 50
V_fixture   = 1.1
V_fixture_min = 1.06
V_fixture_max = 1.17
|   Time   V(typ)   V(min)   V(max)
0s        957.9mV    931.6mV    1.002V
51ps      956mV      929.5mV    1.005V
62ps      961.5mV    928.3mV    1.029V
73ps      981.1mV    933.3mV    1.065V
92ps      1.026V     966.5mV    1.108V
111ps     1.055V     1.003V     1.132V
138ps     1.077V     1.03V      1.152V
166ps     1.088V     1.045V     1.161V
203ps     1.095V     1.054V     1.167V
378ps     1.1V       1.06V      1.17V
[Falling Waveform]
R_fixture = 50
V_fixture = 0.0
|   Time   V(typ)   V(min)   V(max)
0s        202.9mV    206.6mV    209.1mV
61ps      205.5mV    208.8mV    205.8mV
71ps      203.6mV    212mV      184.9mV
87ps      172.6mV    208.2mV    116.7mV
99ps      128.8mV    185.7mV    79.63mV
116ps     78.27mV    132.4mV    47.07mV
148ps     31.3mV     56.46mV    17.7mV
179ps     13.11mV    24.55mV    7.031mV
217ps     4.711mV    9.086mV    2.419mV
378ps     520.8uV    549.6uV    325.8uV
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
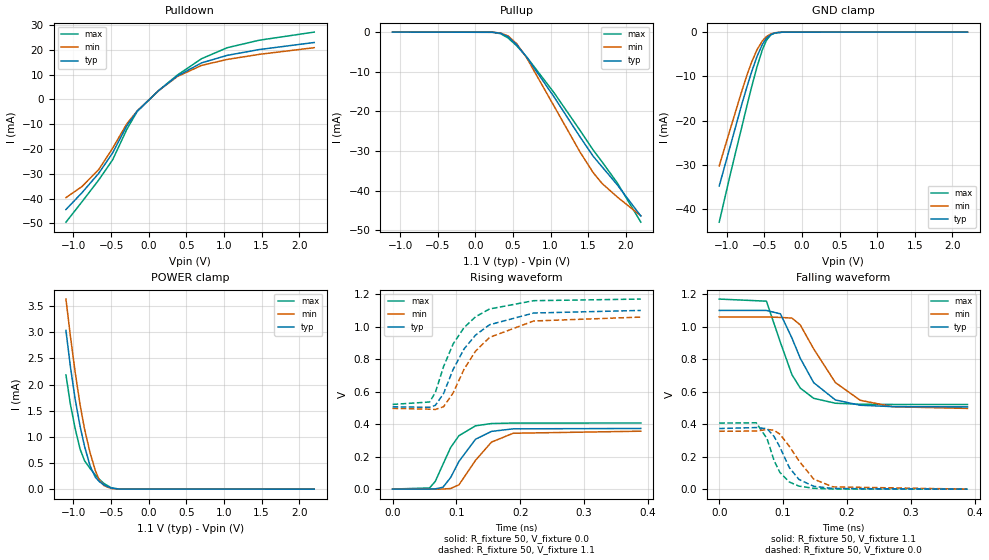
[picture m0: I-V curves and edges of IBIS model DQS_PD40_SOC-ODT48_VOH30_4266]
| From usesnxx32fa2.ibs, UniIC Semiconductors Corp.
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| DQS_PD40_SOC-ODT48_VOH30_4266
| (40 Ohm Pulldown, 48 Ohm System ODT Setting, VOH=VDDQ/3.0, 3200-4266Mbps)
[Model]   DQS_PD40_SOC-ODT48_VOH30_4266
Model_type   I/O
Vinl = 123.333mV
Vinh = 243.333mV
Vmeas = 183.333mV
Vref = 0.0mV
Cref = 0.0pF
Rref = 48.000Ohm
|   typ   min   max
|C_comp   0.849pF   0.799pF   0.899pF
C_comp_pullup   0.4245pF   0.3995pF   0.4495pF
C_comp_pulldown   0.4245pF   0.3995pF   0.4495pF
| Note: C_comp changes when the ODT circuit is enabled.
[Model Spec]
| Input threshold voltage corners
Vinl   0.1233V   0.1167V   0.1350V
Vinh   0.2433V   0.2367V   0.2550V
| Measurement voltage corners
Vmeas   0.1833V   0.1767V   0.1950V
| Timing spec test load voltage corners
Vref   0.0000V   0.0000V   0.0000V
| Dynamic Overshoot Parameters from LPDDR4 Specification
D_overshoot_ampl_h   0.30   NA   NA
D_overshoot_ampl_l   0.30   NA   NA
D_overshoot_area_h   0.1n   NA   NA
D_overshoot_area_l   0.1n   NA   NA
[Voltage Range]   1.1000V   1.0600V   1.1700V
[Pullup Reference]   1.1000V   1.0600V   1.1700V
| Junction Temperature (Ambient temp is 35C typ 95C min -40C max)
[Temperature Range]   50.0   110.0   -40.0
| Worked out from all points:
|   slope of the pulldown table from 0 to 0.165 V, typ, clamps not added: 37 ohm
|   slope of the pullup table from 0 to 0.165 V, typ, clamps not added: 15.6 kohm
|   GND clamp passes 1 mA (typ) near -0.45 V on its own axis
|   POWER clamp passes 1 mA (typ) near -0.88 V on its own axis
|   rising waveform, R_fixture 50, V_fixture 0.0: 20-80 % time 36ps typ, 40.3ps min, 31.8ps max; typ from 0 V to 0.373 V
|   falling waveform, R_fixture 50, V_fixture 1.1: 20-80 % time 45.6ps typ, 57.4ps min, 35.8ps max; typ from 1.1 V to 0.507 V
|   rising waveform, R_fixture 50, V_fixture 1.1: 20-80 % time 56.2ps typ, 59.5ps min, 51.8ps max; typ from 0.507 V to 1.1 V
|   falling waveform, R_fixture 50, V_fixture 0.0: 20-80 % time 30.9ps typ, 39.1ps min, 25.5ps max; typ from 0.373 V to 0.001 V
[Pulldown]
|   Voltage   I(typ)   I(min)   I(max)
-1.1V     -44.39mA   -39.58mA   -49.5mA
-888.8mV  -37.68mA   -35.17mA   -41.35mA
-664.4mV  -29.79mA   -28.29mA   -32.48mA
-479.6mV  -21.57mA   -19.68mA   -24.36mA
-291.5mV  -10.62mA   -9.821mA   -12.1mA
-152.9mV  -4.694mA   -4.619mA   -4.822mA
137.5mV   3.734mA    3.707mA    3.742mA
378.4mV   9.422mA    9.201mA    9.791mA
701.8mV   14.75mA    13.74mA    16.43mA
1.045V    17.81mA    16.16mA    20.89mA
1.471V    20.14mA    18.2mA     23.91mA
2.2V      22.98mA    20.89mA    27.18mA
[GND Clamp]
|   Voltage   I(typ)   I(min)   I(max)
-1.1V     -34.75mA   -30.21mA   -42.91mA
-944.9mV  -25.23mA   -21.44mA   -31.55mA
-803mV    -16.5mA    -13.5mA    -21.65mA
-727.1mV  -12.12mA   -9.513mA   -16.33mA
-671mV    -9.079mA   -6.866mA   -12.51mA
-598.4mV  -5.545mA   -4.01mA    -7.885mA
-525.8mV  -2.767mA   -1.975mA   -3.963mA
-473mV    -1.423mA   -1.031mA   -1.887mA
-416.9mV  -598.1uA   -441.3uA   -665.3uA
-357.5mV  -192.3uA   -144.5uA   -174.3uA
-251.9mV  -13.29uA   -11.93uA   -7.91uA
2.2V      0A         0A         0A
[Pullup]
|   Voltage   I(typ)   I(min)   I(max)
-1.1V     5.229uA    8.059uA    2.358uA
233.2mV   -40.51uA   -40.55uA   -42.22uA
335.5mV   -284.5uA   -237.4uA   -391.9uA
434.5mV   -1.159mA   -947.5uA   -1.465mA
550mV     -3.184mA   -2.927mA   -3.464mA
682mV     -6.308mA   -6.472mA   -6.26mA
1.045V    -16.32mA   -18.64mA   -15.27mA
1.391V    -26.44mA   -30.26mA   -24.79mA
1.566V    -31.33mA   -35.46mA   -29.76mA
1.685V    -34.02mA   -38.22mA   -32.77mA
1.887V    -38.56mA   -41.63mA   -38.07mA
2.2V      -46.44mA   -46.38mA   -47.99mA
[POWER Clamp]
|   Voltage   I(typ)   I(min)   I(max)
-1.1V     3.033mA    3.633mA    2.184mA
-1.041V   2.345mA    2.929mA    1.625mA
-977.9mV  1.723mA    2.241mA    1.161mA
-911.9mV  1.2mA      1.611mA    764.8uA
-852.5mV  818.1uA    1.148mA    543.8uA
-779.9mV  447.8uA    701.5uA    396.3uA
-710.6mV  232.2uA    359uA      273.1uA
-657.8mV  146.8uA    178.9uA    190.6uA
-595.1mV  80.76uA    68.29uA    109.2uA
-499.4mV  21.31uA    13.13uA    27.43uA
-397.1mV  2.394uA    1.592uA    2.118uA
2.2V      0A         0A         0A
[Ramp]
|   typ   min   max
| 20% - 80%
dV/dt_r   223.72m/36.03p   213.67m/40.33p   243.96m/31.77p
dV/dt_f   356.03m/45.63p   337.66m/57.36p   389.18m/35.80p
| 25% - 75%
|dV/dt_r   186.43m/28.69p   178.06m/32.18p   203.30m/25.20p
|dV/dt_f   296.69m/36.40p   281.38m/45.81p   324.32m/28.50p
R_load = 50
[Rising Waveform]
R_fixture = 50
V_fixture = 0.0
|   Time   V(typ)   V(min)   V(max)
0s        460.5uV    391.3uV    338.1uV
58ps      150.5uV    145.1uV    6.959mV
67ps      1.344mV    -450.1uV   48.07mV
79ps      11.62mV    295.9uV    152.8mV
91ps      71.21mV    3.437mV    256mV
104ps     170.6mV    26.43mV    328.9mV
130ps     307mV      177.2mV    389.7mV
155ps     355.3mV    289.4mV    403.6mV
189ps     371mV      343.8mV    406.6mV
389ps     373.3mV    356.5mV    406.9mV
[Falling Waveform]
R_fixture   = 50
V_fixture   = 1.1
V_fixture_min = 1.06
V_fixture_max = 1.17
|   Time   V(typ)   V(min)   V(max)
0s        1.1V       1.06V      1.17V
74ps      1.1V       1.06V      1.157V
96ps      1.079V     1.057V     901.9mV
114ps     929.7mV    1.053V     704.5mV
127ps     805.8mV    1.011V     622.3mV
148ps     655.8mV    863.7mV    559.3mV
182ps     549.4mV    656.3mV    529.1mV
221ps     516.7mV    547.2mV    522.6mV
272ps     508.2mV    507.4mV    521.5mV
389ps     506.6mV    497.2mV    521.4mV
[Rising Waveform]
R_fixture   = 50
V_fixture   = 1.1
V_fixture_min = 1.06
V_fixture_max = 1.17
|   Time   V(typ)   V(min)   V(max)
0s        506.5mV    496.8mV    521.3mV
58ps      503.6mV    492.2mV    536.2mV
67ps      515.5mV    490.3mV    594.5mV
80ps      588.9mV    507.3mV    755.6mV
95ps      737.8mV    593mV      894.4mV
112ps     863mV      737.9mV    994.2mV
130ps     948.1mV    849.3mV    1.061V
152ps     1.012V     934.1mV    1.109V
221ps     1.084V     1.035V     1.16V
389ps     1.1V       1.059V     1.17V
[Falling Waveform]
R_fixture = 50
V_fixture = 0.0
|   Time   V(typ)   V(min)   V(max)
0s        373.4mV    356.6mV    407mV
58ps      379.4mV    358.1mV    408.7mV
75ps      372.1mV    367.7mV    310.8mV
86ps      324.8mV    362.6mV    175.8mV
95ps      259.4mV    339mV      103.9mV
110ps     132.2mV    263.6mV    44.04mV
125ps     60.19mV    174.3mV    19.1mV
148ps     18.21mV    62.6mV     5.643mV
178ps     4.397mV    14.5mV     1.429mV
389ps     518.3uV    477.6uV    357.8uV
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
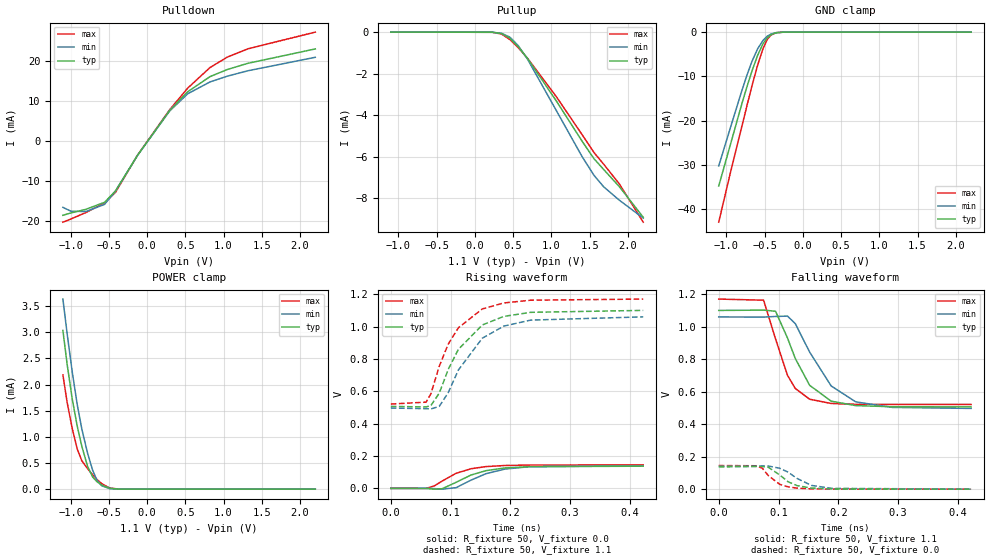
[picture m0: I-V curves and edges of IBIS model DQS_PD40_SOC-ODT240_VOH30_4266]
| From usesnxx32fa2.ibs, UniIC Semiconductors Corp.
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| DQS_PD40_SOC-ODT240_VOH30_4266
| (40 Ohm Pulldown, 240 Ohm System ODT Setting, VOH=VDDQ/3.0, 3200-4266Mbps)
[Model]   DQS_PD40_SOC-ODT240_VOH30_4266
Model_type   I/O
Vinl = 123.333mV
Vinh = 243.333mV
Vmeas = 183.333mV
Vref = 0.0mV
Cref = 0.0pF
Rref = 240.000Ohm
|   typ   min   max
|C_comp   0.849pF   0.799pF   0.899pF
C_comp_pullup   0.4245pF   0.3995pF   0.4495pF
C_comp_pulldown   0.4245pF   0.3995pF   0.4495pF
| Note: C_comp changes when the ODT circuit is enabled.
[Model Spec]
| Input threshold voltage corners
Vinl   0.1233V   0.1167V   0.1350V
Vinh   0.2433V   0.2367V   0.2550V
| Measurement voltage corners
Vmeas   0.1833V   0.1767V   0.1950V
| Timing spec test load voltage corners
Vref   0.0000V   0.0000V   0.0000V
| Dynamic Overshoot Parameters from LPDDR4 Specification
D_overshoot_ampl_h   0.30   NA   NA
D_overshoot_ampl_l   0.30   NA   NA
D_overshoot_area_h   0.1n   NA   NA
D_overshoot_area_l   0.1n   NA   NA
[Voltage Range]   1.1000V   1.0600V   1.1700V
[Pullup Reference]   1.1000V   1.0600V   1.1700V
| Junction Temperature (Ambient temp is 35C typ 95C min -40C max)
[Temperature Range]   50.0   110.0   -40.0
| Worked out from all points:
|   slope of the pulldown table from 0 to 0.165 V, typ, clamps not added: 37.1 ohm
|   slope of the pullup table from 0 to 0.165 V, typ, clamps not added: 77.3 kohm
|   GND clamp passes 1 mA (typ) near -0.45 V on its own axis
|   POWER clamp passes 1 mA (typ) near -0.88 V on its own axis
|   rising waveform, R_fixture 50, V_fixture 0.0: 20-80 % time 55ps typ, 57.7ps min, 48.6ps max; typ from 0 V to 0.137 V
|   falling waveform, R_fixture 50, V_fixture 1.1: 20-80 % time 45.2ps typ, 56.7ps min, 35.5ps max; typ from 1.1 V to 0.507 V
|   rising waveform, R_fixture 50, V_fixture 1.1: 20-80 % time 56.9ps typ, 61.7ps min, 52.2ps max; typ from 0.507 V to 1.1 V
|   falling waveform, R_fixture 50, V_fixture 0.0: 20-80 % time 30.4ps typ, 38.4ps min, 26.3ps max; typ from 0.137 V to 0 V
[Pulldown]
|   Voltage   I(typ)   I(min)   I(max)
-1.1V     -18.54mA   -16.56mA   -20.26mA
-994.4mV  -17.95mA   -17.52mA   -19.46mA
-799.7mV  -17.05mA   -17.6mA    -17.85mA
-555.5mV  -15.29mA   -15.82mA   -15.47mA
-413.6mV  -12.49mA   -12.53mA   -12.86mA
-123.2mV  -3.54mA    -3.561mA   -3.496mA
295.9mV   7.621mA    7.493mA    7.804mA
533.5mV   12.32mA    11.8mA     13.23mA
823.9mV   16.07mA    14.75mA    18.34mA
1.048V    17.83mA    16.17mA    20.92mA
1.319V    19.39mA    17.53mA    23mA
2.2V      22.98mA    20.89mA    27.18mA
[GND Clamp]
|   Voltage   I(typ)   I(min)   I(max)
-1.1V     -34.74mA   -30.21mA   -42.91mA
-951.5mV  -25.64mA   -21.81mA   -32.03mA
-796.4mV  -16.11mA   -13.14mA   -21.19mA
-730.4mV  -12.3mA    -9.678mA   -16.56mA
-664.4mV  -8.736mA   -6.578mA   -12.07mA
-591.8mV  -5.256mA   -3.789mA   -7.492mA
-522.5mV  -2.664mA   -1.902mA   -3.81mA
-466.4mV  -1.295mA   -942.6uA   -1.69mA
-416.9mV  -597.3uA   -441.4uA   -665.4uA
-347.6mV  -155.9uA   -117.5uA   -135.2uA
-245.3mV  -11.03uA   -10.04uA   -6.275uA
2.2V      0A         0A         0A
[Pullup]
|   Voltage   I(typ)   I(min)   I(max)
-1.1V     1.046uA    1.612uA    471.3nA
229.9mV   -7.613uA   -7.644uA   -7.764uA
348.7mV   -70.6uA    -57.82uA   -97.34uA
457.6mV   -294.5uA   -245.7uA   -359.9uA
563.2mV   -685.3uA   -637.4uA   -737.2uA
688.6mV   -1.277mA   -1.311mA   -1.267mA
1.065V    -3.324mA   -3.787mA   -3.116mA
1.401V    -5.257mA   -5.999mA   -4.942mA
1.556V    -6.1mA     -6.899mA   -5.799mA
1.682V    -6.617mA   -7.451mA   -6.361mA
1.887V    -7.444mA   -8.098mA   -7.311mA
2.2V      -8.921mA   -8.963mA   -9.16mA
[POWER Clamp]
|   Voltage   I(typ)   I(min)   I(max)
-1.1V     3.033mA    3.633mA    2.184mA
-1.044V   2.381mA    2.967mA    1.653mA
-977.9mV  1.723mA    2.241mA    1.16mA
-911.9mV  1.2mA      1.611mA    764uA
-852.5mV  818.3uA    1.148mA    543.6uA
-776.6mV  434.2uA    683.3uA    390.2uA
-710.6mV  232.2uA    359uA      273.1uA
-654.5mV  142.6uA    170.4uA    185.9uA
-591.8mV  77.94uA    64.8uA     105.5uA
-489.5mV  17.76uA    10.82uA    22.47uA
-367.4mV  1.199uA    874nA      945.3nA
2.2V      0A         0A         0A
[Ramp]
|   typ   min   max
| 20% - 80%
dV/dt_r   82.39m/55.04p   84.14m/57.75p   87.15m/48.57p
dV/dt_f   356.02m/45.18p   337.78m/56.69p   389.18m/35.46p
| 25% - 75%
|dV/dt_r   68.66m/43.85p   70.12m/46.04p   72.62m/38.52p
|dV/dt_f   296.68m/36.06p   281.48m/45.29p   324.31m/28.23p
R_load = 50
[Rising Waveform]
R_fixture = 50
V_fixture = 0.0
|   Time   V(typ)   V(min)   V(max)
0s        71.06uV    37.31uV    61.25uV
59ps      -748.4uV   418.8uV    -12.15uV
73ps      -4.734mV   -1.424mV   16.13mV
86ps      -1.962mV   -4.609mV   45.73mV
109ps     37.38mV    4.427mV    93.15mV
134ps     82.44mV    50.78mV    121.4mV
159ps     109.6mV    90.86mV    134.7mV
191ps     126.5mV    119.5mV    141.6mV
232ps     134.2mV    134mV      144.3mV
422ps     137.4mV    140.3mV    145.3mV
[Falling Waveform]
R_fixture   = 50
V_fixture   = 1.1
V_fixture_min = 1.06
V_fixture_max = 1.17
|   Time   V(typ)   V(min)   V(max)
0s        1.1V       1.06V      1.17V
75ps      1.102V     1.059V     1.163V
95ps      1.095V     1.063V     924.4mV
115ps     929.9mV    1.065V     700.6mV
128ps     804.2mV    1.019V     620mV
152ps     639.3mV    843.5mV    553.5mV
188ps     541.7mV    635.3mV    527.4mV
229ps     514.3mV    537.4mV    522.3mV
290ps     507.4mV    503.2mV    521.4mV
422ps     506.6mV    497mV      521.4mV
[Rising Waveform]
R_fixture   = 50
V_fixture   = 1.1
V_fixture_min = 1.06
V_fixture_max = 1.17
|   Time   V(typ)   V(min)   V(max)
0s        506.5mV    496.8mV    521.3mV
59ps      503.5mV    492.5mV    533mV
67ps      511.9mV    490.7mV    584.3mV
81ps      588.5mV    507mV      755.2mV
96ps      735.4mV    591.7mV    891.6mV
113ps     859.4mV    731.8mV    992.7mV
153ps     1.01V      928.2mV    1.109V
189ps     1.063V     1.003V     1.146V
234ps     1.088V     1.04V      1.163V
422ps     1.1V       1.06V      1.17V
[Falling Waveform]
R_fixture = 50
V_fixture = 0.0
|   Time   V(typ)   V(min)   V(max)
0s        137.4mV    140.4mV    145.3mV
63ps      139.3mV    141.7mV    144.1mV
73ps      139.4mV    142.9mV    128.3mV
83ps      134.7mV    142.5mV    83.36mV
102ps     87.56mV    128.8mV    29.85mV
116ps     45.56mV    104.8mV    14.15mV
131ps     21.68mV    65.9mV     6.422mV
155ps     6.788mV    23.2mV     1.876mV
189ps     1.45mV     5.133mV    393uV
422ps     131.3uV    130.4uV    79.34uV
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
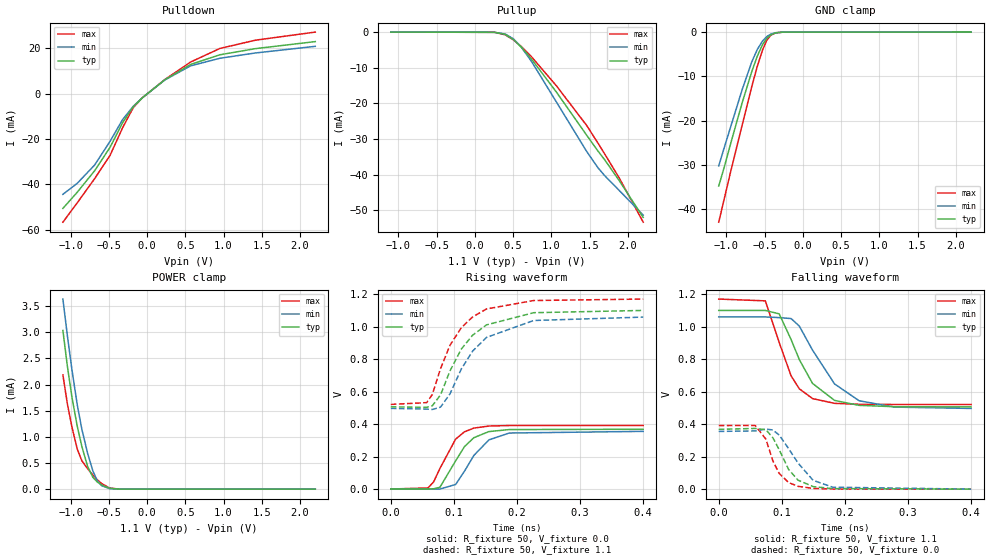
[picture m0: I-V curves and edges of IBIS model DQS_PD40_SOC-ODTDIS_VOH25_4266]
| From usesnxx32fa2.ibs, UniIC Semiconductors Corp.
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| DQS_PD40_SOC-ODTDIS_VOH25_4266
| (40 Ohm Pulldown, SOC ODT disabled setting, VOH=VDDQ/2.5 cal. point, 3200-4266Mbps)
[Model]   DQS_PD40_SOC-ODTDIS_VOH25_4266
Model_type   I/O
Vinl = 160.000mV
Vinh = 280.000mV
Vmeas = 220.000mV
Vref = 0.0mV
Cref = 0.0pF
|   typ   min   max
|C_comp   0.849pF   0.799pF   0.899pF
C_comp_pullup   0.4245pF   0.3995pF   0.4495pF
C_comp_pulldown   0.4245pF   0.3995pF   0.4495pF
| Note: C_comp changes when the ODT circuit is enabled.
[Model Spec]
| Input threshold voltage corners
Vinl   0.1600V   0.1520V   0.1740V
Vinh   0.2800V   0.2720V   0.2940V
| Measurement voltage corners
Vmeas   0.2200V   0.2120V   0.2340V
| Timing spec test load voltage corners
Vref   0.0000V   0.0000V   0.0000V
| Dynamic Overshoot Parameters from LPDDR4 Specification
D_overshoot_ampl_h   0.30   NA   NA
D_overshoot_ampl_l   0.30   NA   NA
D_overshoot_area_h   0.1n   NA   NA
D_overshoot_area_l   0.1n   NA   NA
[Voltage Range]   1.1000V   1.0600V   1.1700V
[Pullup Reference]   1.1000V   1.0600V   1.1700V
| Junction Temperature (Ambient temp is 35C typ 95C min -40C max)
[Temperature Range]   50.0   110.0   -40.0
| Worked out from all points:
|   slope of the pulldown table from 0 to 0.165 V, typ, clamps not added: 36.9 ohm
|   slope of the pullup table from 0 to 0.165 V, typ, clamps not added: 17.1 kohm
|   GND clamp passes 1 mA (typ) near -0.45 V on its own axis
|   POWER clamp passes 1 mA (typ) near -0.88 V on its own axis
|   rising waveform, R_fixture 50, V_fixture 0.0: 20-80 % time 34.6ps typ, 38.2ps min, 31.6ps max; typ from 0.001 V to 0.368 V
|   falling waveform, R_fixture 50, V_fixture 1.1: 20-80 % time 45.6ps typ, 57.6ps min, 35.8ps max; typ from 1.1 V to 0.507 V
|   rising waveform, R_fixture 50, V_fixture 1.1: 20-80 % time 56.3ps typ, 59.8ps min, 51.7ps max; typ from 0.507 V to 1.1 V
|   falling waveform, R_fixture 50, V_fixture 0.0: 20-80 % time 31.3ps typ, 39.3ps min, 25.3ps max; typ from 0.368 V to 0.001 V
[Pulldown]
|   Voltage   I(typ)   I(min)   I(max)
-1.1V     -50.64mA   -44.42mA   -56.73mA
-915.2mV  -43.62mA   -39.66mA   -48.31mA
-684.2mV  -33.99mA   -31.46mA   -37.48mA
-482.9mV  -23.65mA   -20.99mA   -27.19mA
-317.9mV  -12.72mA   -11.35mA   -14.94mA
-179.3mV  -5.752mA   -5.546mA   -6.132mA
-60.5mV   -1.802mA   -1.786mA   -1.779mA
229.9mV   6.063mA    5.989mA    6.147mA
569.8mV   12.91mA    12.29mA    13.97mA
952.6mV   17.16mA    15.62mA    19.95mA
1.418V    19.88mA    17.97mA    23.61mA
2.2V      22.98mA    20.89mA    27.18mA
[GND Clamp]
|   Voltage   I(typ)   I(min)   I(max)
-1.1V     -34.75mA   -30.2mA    -42.92mA
-1.027V   -30.44mA   -26.03mA   -37.57mA
-941.6mV  -25.02mA   -21.25mA   -31.33mA
-793.1mV  -15.92mA   -12.96mA   -20.97mA
-667.7mV  -8.911mA   -6.72mA    -12.3mA
-595.1mV  -5.401mA   -3.898mA   -7.695mA
-525.8mV  -2.771mA   -1.974mA   -3.966mA
-469.7mV  -1.358mA   -985.2uA   -1.787mA
-416.9mV  -597.2uA   -440.2uA   -665.5uA
-354.2mV  -179uA     -134.5uA   -160.5uA
-258.5mV  -16.23uA   -14.39uA   -9.948uA
2.2V      0A         0A         0A
[Pullup]
|   Voltage   I(typ)   I(min)   I(max)
-1.1V     4.106uA    7.431uA    1.361uA
256.3mV   -57.83uA   -56.08uA   -56.76uA
394.9mV   -631.3uA   -523.9uA   -750.6uA
503.8mV   -2.099mA   -1.888mA   -2.196mA
606.1mV   -4.22mA    -4.209mA   -4.061mA
741.4mV   -7.628mA   -8.301mA   -6.975mA
1.065V    -16.85mA   -19.63mA   -15.08mA
1.461V    -28.96mA   -33.53mA   -26.23mA
1.609V    -33.42mA   -38.12mA   -31.2mA
1.698V    -35.91mA   -40.36mA   -34.29mA
1.887V    -41.73mA   -44.49mA   -41mA
2.2V      -52.05mA   -51.39mA   -53.39mA
[POWER Clamp]
|   Voltage   I(typ)   I(min)   I(max)
-1.1V     3.033mA    3.633mA    2.184mA
-1.041V   2.345mA    2.929mA    1.625mA
-981.2mV  1.753mA    2.275mA    1.183mA
-911.9mV  1.2mA      1.61mA     764.6uA
-852.5mV  818.1uA    1.148mA    543.5uA
-776.6mV  434.1uA    683.2uA    390.2uA
-707.3mV  225.4uA    345.4uA    267.6uA
-651.2mV  138.6uA    162.4uA    181.2uA
-591.8mV  77.93uA    64.79uA    105.5uA
-489.5mV  17.84uA    10.81uA    22.44uA
-367.4mV  1.189uA    872.9nA    943.4nA
2.2V      0A         0A         0A
[Ramp]
|   typ   min   max
| 20% - 80%
dV/dt_r   220.67m/34.62p   212.99m/38.16p   234.73m/31.58p
dV/dt_f   356.03m/45.65p   337.71m/57.58p   389.19m/35.75p
| 25% - 75%
|dV/dt_r   183.89m/27.56p   177.50m/30.42p   195.60m/25.07p
|dV/dt_f   296.69m/36.41p   281.42m/45.98p   324.32m/28.47p
R_load = 50
[Rising Waveform]
R_fixture = 50
V_fixture = 0.0
|   Time   V(typ)   V(min)   V(max)
0s        576.2uV    460uV      427uV
59ps      302.1uV    60.2uV     6.861mV
68ps      1.699mV    -527.5uV   44.07mV
78ps      11.14mV    298.1uV    126.8mV
103ps     173.9mV    28.19mV    307.8mV
117ps     261.2mV    109.9mV    352.6mV
132ps     316.6mV    207.5mV    375.5mV
156ps     354.2mV    303.3mV    388.2mV
188ps     366.4mV    345.1mV    391.3mV
401ps     368.4mV    355.4mV    391.6mV
[Falling Waveform]
R_fixture   = 50
V_fixture   = 1.1
V_fixture_min = 1.06
V_fixture_max = 1.17
|   Time   V(typ)   V(min)   V(max)
0s        1.1V       1.06V      1.17V
74ps      1.1V       1.06V      1.159V
96ps      1.079V     1.056V     903.5mV
115ps     920.8mV    1.05V      697.3mV
128ps     797.9mV    1.004V     618.1mV
149ps     651.2mV    856.1mV    557.7mV
184ps     546.5mV    648mV      528.4mV
223ps     516mV      544.4mV    522.5mV
279ps     507.9mV    505.4mV    521.5mV
401ps     506.6mV    497.1mV    521.4mV
[Rising Waveform]
R_fixture   = 50
V_fixture   = 1.1
V_fixture_min = 1.06
V_fixture_max = 1.17
|   Time   V(typ)   V(min)   V(max)
0s        506.5mV    496.8mV    521.3mV
57ps      503.2mV    492.6mV    532.3mV
66ps      513.1mV    490.1mV    582.9mV
79ps      579.9mV    504.6mV    741.8mV
94ps      727.7mV    586.1mV    885.4mV
112ps     862.2mV    739.3mV    993.7mV
130ps     947.6mV    849.8mV    1.06V
152ps     1.011V     933.9mV    1.109V
227ps     1.086V     1.038V     1.161V
401ps     1.1V       1.059V     1.17V
[Falling Waveform]
R_fixture = 50
V_fixture = 0.0
|   Time   V(typ)   V(min)   V(max)
0s        368.5mV    355.6mV    391.7mV
58ps      374mV      358.9mV    392.3mV
75ps      365.9mV    370.3mV    307.4mV
86ps      317mV      364.6mV    174.7mV
96ps      243.4mV    333.4mV    97.47mV
111ps     122.2mV    250.2mV    41.27mV
126ps     55.84mV    161.1mV    17.92mV
150ps     16.22mV    54.74mV    5.098mV
181ps     3.876mV    12.57mV    1.335mV
401ps     621.2uV    531.5uV    445.4uV
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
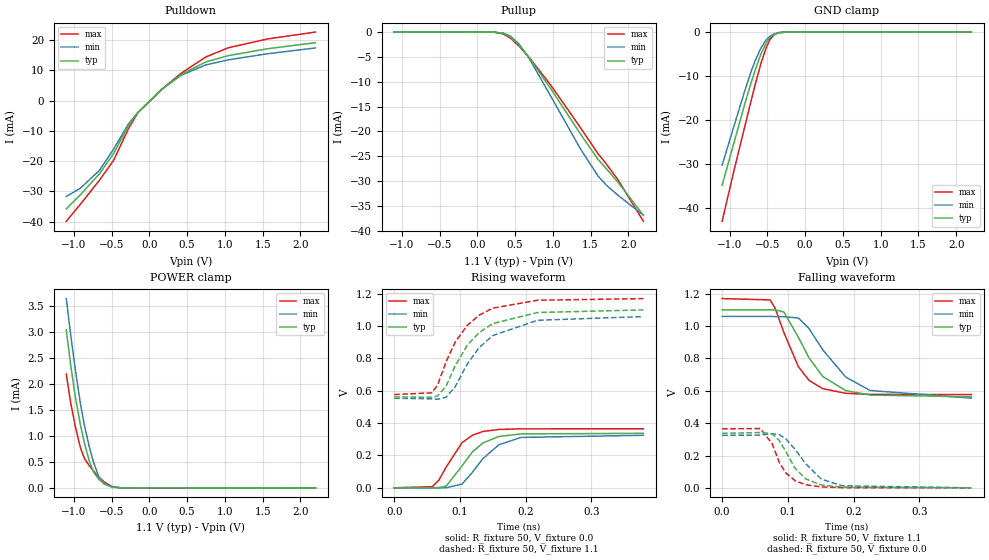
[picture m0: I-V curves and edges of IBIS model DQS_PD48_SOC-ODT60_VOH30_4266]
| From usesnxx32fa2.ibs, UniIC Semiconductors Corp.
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| DQS_PD48_SOC-ODT60_VOH30_4266
| (48 Ohm Pulldown, 60 Ohm System ODT Setting, VOH=VDDQ/3.0, 3200-4266Mbps)
[Model]   DQS_PD48_SOC-ODT60_VOH30_4266
Model_type   I/O
Vinl = 123.333mV
Vinh = 243.333mV
Vmeas = 183.333mV
Vref = 0.0mV
Cref = 0.0pF
Rref = 60.000Ohm
|   typ   min   max
|C_comp   0.849pF   0.799pF   0.899pF
C_comp_pullup   0.4245pF   0.3995pF   0.4495pF
C_comp_pulldown   0.4245pF   0.3995pF   0.4495pF
| Note: C_comp changes when the ODT circuit is enabled.
[Model Spec]
| Input threshold voltage corners
Vinl   0.1233V   0.1167V   0.1350V
Vinh   0.2433V   0.2367V   0.2550V
| Measurement voltage corners
Vmeas   0.1833V   0.1767V   0.1950V
| Timing spec test load voltage corners
Vref   0.0000V   0.0000V   0.0000V
| Dynamic Overshoot Parameters from LPDDR4 Specification
D_overshoot_ampl_h   0.30   NA   NA
D_overshoot_ampl_l   0.30   NA   NA
D_overshoot_area_h   0.1n   NA   NA
D_overshoot_area_l   0.1n   NA   NA
[Voltage Range]   1.1000V   1.0600V   1.1700V
[Pullup Reference]   1.1000V   1.0600V   1.1700V
| Junction Temperature (Ambient temp is 35C typ 95C min -40C max)
[Temperature Range]   50.0   110.0   -40.0
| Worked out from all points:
|   slope of the pulldown table from 0 to 0.165 V, typ, clamps not added: 43.9 ohm
|   slope of the pullup table from 0 to 0.165 V, typ, clamps not added: 19.5 kohm
|   GND clamp passes 1 mA (typ) near -0.45 V on its own axis
|   POWER clamp passes 1 mA (typ) near -0.88 V on its own axis
|   rising waveform, R_fixture 50, V_fixture 0.0: 20-80 % time 39.5ps typ, 43.4ps min, 34.7ps max; typ from 0 V to 0.337 V
|   falling waveform, R_fixture 50, V_fixture 1.1: 20-80 % time 49.1ps typ, 61.2ps min, 38.9ps max; typ from 1.1 V to 0.563 V
|   rising waveform, R_fixture 50, V_fixture 1.1: 20-80 % time 56.2ps typ, 59.6ps min, 52.1ps max; typ from 0.563 V to 1.1 V
|   falling waveform, R_fixture 50, V_fixture 0.0: 20-80 % time 32.1ps typ, 40ps min, 27.3ps max; typ from 0.337 V to 0 V
[Pulldown]
|   Voltage   I(typ)   I(min)   I(max)
-1.1V     -35.78mA   -31.71mA   -39.91mA
-915.2mV  -31.18mA   -29.01mA   -34.33mA
-661.1mV  -24.22mA   -23.08mA   -26.35mA
-473mV    -17.5mA    -16.03mA   -19.72mA
-275mV    -8.16mA    -7.633mA   -9.193mA
-152.9mV  -3.942mA   -3.884mA   -4.047mA
170.5mV   3.86mA     3.823mA    3.888mA
424.6mV   8.7mA      8.444mA    9.144mA
744.7mV   12.77mA    11.81mA    14.4mA
1.042V    14.87mA    13.48mA    17.47mA
1.56V     17.15mA    15.5mA     20.39mA
2.2V      19.18mA    17.44mA    22.7mA
[GND Clamp]
|   Voltage   I(typ)   I(min)   I(max)
-1.1V     -34.74mA   -30.21mA   -42.91mA
-941.6mV  -25.02mA   -21.26mA   -31.32mA
-799.7mV  -16.31mA   -13.32mA   -21.42mA
-723.8mV  -11.93mA   -9.348mA   -16.1mA
-664.4mV  -8.736mA   -6.578mA   -12.07mA
-588.5mV  -5.113mA   -3.681mA   -7.298mA
-519.2mV  -2.565mA   -1.834mA   -3.661mA
-469.7mV  -1.357mA   -988uA     -1.787mA
-413.6mV  -563.8uA   -416.5uA   -622.5uA
-347.6mV  -154.3uA   -117.3uA   -136uA
-251.9mV  -13.35uA   -12.05uA   -7.848uA
2.2V      0A         0A         0A
[Pullup]
|   Voltage   I(typ)   I(min)   I(max)
-1.1V     4.184uA    6.447uA    1.886uA
226.6mV   -28.13uA   -28.75uA   -28.57uA
342.1mV   -254uA     -208.9uA   -350.4uA
441.1mV   -996.4uA   -818.8uA   -1.248mA
553.3mV   -2.6mA     -2.398mA   -2.819mA
691.9mV   -5.241mA   -5.408mA   -5.18mA
975.7mV   -11.45mA   -12.97mA   -10.74mA
1.365V    -20.49mA   -23.48mA   -19.21mA
1.599V    -25.64mA   -28.97mA   -24.48mA
1.708V    -27.49mA   -30.81mA   -26.54mA
1.86V     -30.16mA   -32.82mA   -29.67mA
2.2V      -36.89mA   -36.86mA   -38.1mA
[POWER Clamp]
|   Voltage   I(typ)   I(min)   I(max)
-1.1V     3.033mA    3.633mA    2.184mA
-1.044V   2.381mA    2.967mA    1.653mA
-981.2mV  1.753mA    2.275mA    1.183mA
-911.9mV  1.2mA      1.611mA    764.4uA
-859.1mV  857.2uA    1.195mA    560.9uA
-796.4mV  521.5uA    794.7uA    427.2uA
-740.3mV  306.4uA    494.3uA    324.2uA
-667.7mV  159.9uA    206uA      205.2uA
-598.4mV  83.68uA    71.98uA    113uA
-492.8mV  18.91uA    11.59uA    24.05uA
-383.9mV  1.741uA    1.215uA    1.465uA
2.2V      0A         0A         0A
[Ramp]
|   typ   min   max
| 20% - 80%
dV/dt_r   201.86m/39.49p   194.60m/43.39p   218.92m/34.74p
dV/dt_f   322.25m/49.07p   303.18m/61.18p   355.99m/38.94p
| 25% - 75%
|dV/dt_r   168.22m/31.52p   162.16m/34.62p   182.43m/27.60p
|dV/dt_f   268.54m/39.11p   252.65m/48.79p   296.66m/31.00p
R_load = 50
[Rising Waveform]
R_fixture = 50
V_fixture = 0.0
|   Time   V(typ)   V(min)   V(max)
0s        408uV      346.4uV    299.4uV
58ps      471.7uV    181.4uV    7.048mV
68ps      1.726mV    -105.6uV   47.61mV
79ps      10.38mV    843uV      128.1mV
103ps     134.5mV    22.75mV    278.1mV
119ps     222.1mV    95.93mV    325.6mV
135ps     277.5mV    180.9mV    348.3mV
159ps     317.2mV    265.6mV    360.9mV
193ps     333.4mV    311.7mV    364.6mV
379ps     336.8mV    324.7mV    365.2mV
[Falling Waveform]
R_fixture   = 50
V_fixture   = 1.1
V_fixture_min = 1.06
V_fixture_max = 1.17
|   Time   V(typ)   V(min)   V(max)
0s        1.1V       1.06V      1.17V
73ps      1.1V       1.06V      1.162V
81ps      1.1V       1.059V     1.107V
94ps      1.087V     1.058V     959.6mV
116ps     930.8mV    1.05V      749.2mV
132ps     804.9mV    986mV      665.5mV
153ps     688.7mV    853.8mV    612.9mV
188ps     601.4mV    685.2mV    584.7mV
225ps     573.9mV    602.1mV    578.3mV
379ps     562.9mV    554.7mV    576.7mV
[Rising Waveform]
R_fixture   = 50
V_fixture   = 1.1
V_fixture_min = 1.06
V_fixture_max = 1.17
|   Time   V(typ)   V(min)   V(max)
0s        562.8mV    553.9mV    576.6mV
57ps      559.2mV    550.1mV    587.5mV
66ps      567.6mV    547.3mV    635.2mV
79ps      629.5mV    560mV      780.5mV
93ps      756.4mV    626.5mV    902.8mV
111ps     880.6mV    764.5mV    1.004V
129ps     959.4mV    866.5mV    1.067V
150ps     1.016V     941.5mV    1.111V
218ps     1.084V     1.036V     1.16V
379ps     1.1V       1.059V     1.17V
[Falling Waveform]
R_fixture = 50
V_fixture = 0.0
|   Time   V(typ)   V(min)   V(max)
0s        336.9mV    324.8mV    365.2mV
58ps      342.2mV    326.4mV    366.8mV
76ps      334.8mV    334.8mV    273.5mV
87ps      292.7mV    328.8mV    157.5mV
97ps      224.2mV    302.6mV    92.29mV
111ps     120.6mV    237.9mV    44.35mV
127ps     55.74mV    149.5mV    19.49mV
151ps     17.67mV    53.73mV    5.931mV
183ps     4.287mV    12.82mV    1.446mV
379ps     476.1uV    446uV      320.2uV
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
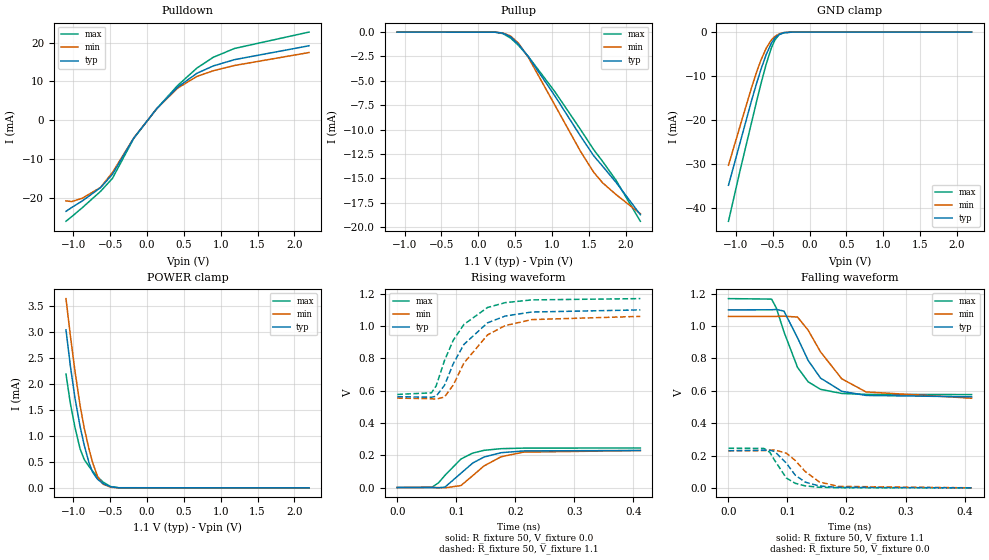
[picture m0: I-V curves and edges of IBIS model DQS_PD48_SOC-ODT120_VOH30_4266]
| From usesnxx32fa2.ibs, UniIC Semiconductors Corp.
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| DQS_PD48_SOC-ODT120_VOH30_4266
| (48 Ohm Pulldown, 120 Ohm System ODT Setting, VOH=VDDQ/3.0, 3200-4266Mbps)
[Model]   DQS_PD48_SOC-ODT120_VOH30_4266
Model_type   I/O
Vinl = 123.333mV
Vinh = 243.333mV
Vmeas = 183.333mV
Vref = 0.0mV
Cref = 0.0pF
Rref = 120.000Ohm
|   typ   min   max
|C_comp   0.849pF   0.799pF   0.899pF
C_comp_pullup   0.4245pF   0.3995pF   0.4495pF
C_comp_pulldown   0.4245pF   0.3995pF   0.4495pF
| Note: C_comp changes when the ODT circuit is enabled.
[Model Spec]
| Input threshold voltage corners
Vinl   0.1233V   0.1167V   0.1350V
Vinh   0.2433V   0.2367V   0.2550V
| Measurement voltage corners
Vmeas   0.1833V   0.1767V   0.1950V
| Timing spec test load voltage corners
Vref   0.0000V   0.0000V   0.0000V
| Dynamic Overshoot Parameters from LPDDR4 Specification
D_overshoot_ampl_h   0.30   NA   NA
D_overshoot_ampl_l   0.30   NA   NA
D_overshoot_area_h   0.1n   NA   NA
D_overshoot_area_l   0.1n   NA   NA
[Voltage Range]   1.1000V   1.0600V   1.1700V
[Pullup Reference]   1.1000V   1.0600V   1.1700V
| Junction Temperature (Ambient temp is 35C typ 95C min -40C max)
[Temperature Range]   50.0   110.0   -40.0
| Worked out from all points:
|   slope of the pulldown table from 0 to 0.165 V, typ, clamps not added: 44 ohm
|   slope of the pullup table from 0 to 0.165 V, typ, clamps not added: 38.9 kohm
|   GND clamp passes 1 mA (typ) near -0.45 V on its own axis
|   POWER clamp passes 1 mA (typ) near -0.88 V on its own axis
|   rising waveform, R_fixture 50, V_fixture 0.0: 20-80 % time 46.8ps typ, 50.9ps min, 41.7ps max; typ from 0 V to 0.23 V
|   falling waveform, R_fixture 50, V_fixture 1.1: 20-80 % time 48.8ps typ, 60.9ps min, 38.7ps max; typ from 1.1 V to 0.563 V
|   rising waveform, R_fixture 50, V_fixture 1.1: 20-80 % time 56.6ps typ, 60.8ps min, 52ps max; typ from 0.563 V to 1.1 V
|   falling waveform, R_fixture 50, V_fixture 0.0: 20-80 % time 32.2ps typ, 39.7ps min, 27.6ps max; typ from 0.23 V to 0 V
[Pulldown]
|   Voltage   I(typ)   I(min)   I(max)
-1.1V     -23.35mA   -20.65mA   -25.9mA
-1.024V   -22.39mA   -20.85mA   -24.74mA
-878.9mV  -20.68mA   -19.99mA   -22.42mA
-631.4mV  -17.27mA   -17.21mA   -18.23mA
-469.7mV  -13.86mA   -13.38mA   -14.89mA
-179.3mV  -4.509mA   -4.486mA   -4.589mA
130.9mV   2.999mA    2.977mA    3.007mA
414.7mV   8.537mA    8.295mA    8.955mA
678.7mV   12.12mA    11.31mA    13.47mA
899.8mV   14mA       12.77mA    16.22mA
1.187V    15.61mA    14.11mA    18.48mA
2.2V      19.18mA    17.44mA    22.7mA
[GND Clamp]
|   Voltage   I(typ)   I(min)   I(max)
-1.1V     -34.74mA   -30.21mA   -42.91mA
-948.2mV  -25.43mA   -21.63mA   -31.79mA
-789.8mV  -15.72mA   -12.78mA   -20.72mA
-720.5mV  -11.75mA   -9.185mA   -15.87mA
-661.1mV  -8.566mA   -6.435mA   -11.85mA
-588.5mV  -5.114mA   -3.681mA   -7.298mA
-519.2mV  -2.564mA   -1.833mA   -3.66mA
-469.7mV  -1.358mA   -991.2uA   -1.787mA
-413.6mV  -565uA     -420.4uA   -620.8uA
-350.9mV  -166uA     -126.7uA   -146.9uA
-228.8mV  -6.698uA   -6.444uA   -3.568uA
2.2V      0A         0A         0A
[Pullup]
|   Voltage   I(typ)   I(min)   I(max)
-1.1V     2.092uA    3.225uA    943.3nA
229.9mV   -15.11uA   -15.29uA   -15.56uA
332.2mV   -107.7uA   -90.15uA   -148.1uA
437.8mV   -483.6uA   -396.5uA   -608.7uA
546.7mV   -1.257mA   -1.152mA   -1.37mA
678.7mV   -2.516mA   -2.582mA   -2.496mA
1.042V    -6.565mA   -7.519mA   -6.134mA
1.388V    -10.66mA   -12.23mA   -9.986mA
1.566V    -12.67mA   -14.36mA   -12.04mA
1.688V    -13.75mA   -15.45mA   -13.26mA
1.867V    -15.37mA   -16.63mA   -15.15mA
2.2V      -18.72mA   -18.62mA   -19.39mA
[POWER Clamp]
|   Voltage   I(typ)   I(min)   I(max)
-1.1V     3.033mA    3.633mA    2.184mA
-1.041V   2.345mA    2.929mA    1.625mA
-977.9mV  1.723mA    2.241mA    1.16mA
-908.6mV  1.178mA    1.582mA    748uA
-852.5mV  818.6uA    1.148mA    543.6uA
-786.5mV  476.4uA    738.2uA    408.6uA
-737mV    296.5uA    478.3uA    318.4uA
-671mV    164.5uA    215.8uA    210.2uA
-598.4mV  83.69uA    71.97uA    113uA
-496.1mV  20.09uA    12.36uA    25.7uA
-387.2mV  1.884uA    1.296uA    1.609uA
2.2V      0A         0A         0A
[Ramp]
|   typ   min   max
| 20% - 80%
dV/dt_r   137.79m/46.76p   137.34m/50.87p   146.98m/41.66p
dV/dt_f   322.26m/48.81p   303.44m/60.92p   355.99m/38.75p
| 25% - 75%
|dV/dt_r   114.82m/37.28p   114.45m/40.63p   122.48m/33.07p
|dV/dt_f   268.55m/38.94p   252.87m/48.64p   296.66m/30.86p
R_load = 50
[Rising Waveform]
R_fixture = 50
V_fixture = 0.0
|   Time   V(typ)   V(min)   V(max)
0s        194.6uV    153.1uV    147.7uV
59ps      -158.9uV   377.3uV    2.635mV
70ps      -1.547mV   -498.2uV   29.23mV
81ps      2.941mV    -1.786mV   76.01mV
108ps     88.68mV    12.4mV     176.7mV
128ps     151.9mV    73.89mV    213.5mV
147ps     188.8mV    133.8mV    230.4mV
176ps     215.8mV    190.6mV    240.7mV
214ps     226.7mV    219.4mV    244.2mV
412ps     229.8mV    229.1mV    245.1mV
[Falling Waveform]
R_fixture   = 50
V_fixture   = 1.1
V_fixture_min = 1.06
V_fixture_max = 1.17
|   Time   V(typ)   V(min)   V(max)
0s        1.1V       1.06V      1.17V
73ps      1.101V     1.06V      1.167V
81ps      1.103V     1.06V      1.113V
94ps      1.093V     1.061V     964.7mV
117ps     927.7mV    1.056V     744.7mV
135ps     788mV      974.8mV    655.7mV
156ps     678.6mV    840.5mV    609mV
192ps     597.1mV    674.2mV    583.6mV
233ps     571.4mV    593.2mV    577.9mV
412ps     562.9mV    554.3mV    576.7mV
[Rising Waveform]
R_fixture   = 50
V_fixture   = 1.1
V_fixture_min = 1.06
V_fixture_max = 1.17
|   Time   V(typ)   V(min)   V(max)
0s        562.7mV    553.9mV    576.6mV
58ps      559.1mV    550mV      586.4mV
66ps      565.6mV    547.5mV    629.6mV
80ps      632.4mV    560.2mV    785.5mV
95ps      767.2mV    635.2mV    912.4mV
113ps     886.4mV    770.9mV    1.01V
153ps     1.02V      945.1mV    1.115V
183ps     1.062V     1.003V     1.145V
228ps     1.087V     1.04V      1.162V
412ps     1.1V       1.06V      1.17V
[Falling Waveform]
R_fixture = 50
V_fixture = 0.0
|   Time   V(typ)   V(min)   V(max)
0s        229.9mV    229.2mV    245.2mV
60ps      232.7mV    230.1mV    244mV
70ps      232.6mV    233mV      220.4mV
78ps      225.5mV    234.2mV    171.6mV
98ps      153.2mV    214.6mV    61.21mV
113ps     79.1mV     170mV      28.43mV
130ps     35.4mV     101.3mV    12.07mV
154ps     11.58mV    36.65mV    3.717mV
186ps     2.841mV    9.147mV    890uV
412ps     263.4uV    252.2uV    168.7uV
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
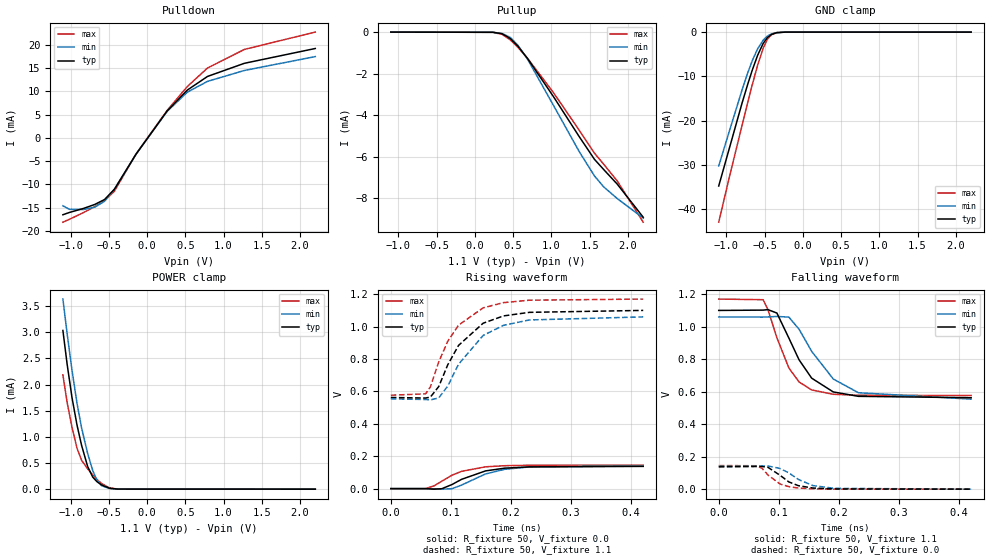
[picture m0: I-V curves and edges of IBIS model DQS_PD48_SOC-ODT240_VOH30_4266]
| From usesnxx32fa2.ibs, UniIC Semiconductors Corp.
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| DQS_PD48_SOC-ODT240_VOH30_4266
| (48 Ohm Pulldown, 240 Ohm System ODT Setting, VOH=VDDQ/3.0, 3200-4266Mbps)
[Model]   DQS_PD48_SOC-ODT240_VOH30_4266
Model_type   I/O
Vinl = 123.333mV
Vinh = 243.333mV
Vmeas = 183.333mV
Vref = 0.0mV
Cref = 0.0pF
Rref = 240.000Ohm
|   typ   min   max
|C_comp   0.849pF   0.799pF   0.899pF
C_comp_pullup   0.4245pF   0.3995pF   0.4495pF
C_comp_pulldown   0.4245pF   0.3995pF   0.4495pF
| Note: C_comp changes when the ODT circuit is enabled.
[Model Spec]
| Input threshold voltage corners
Vinl   0.1233V   0.1167V   0.1350V
Vinh   0.2433V   0.2367V   0.2550V
| Measurement voltage corners
Vmeas   0.1833V   0.1767V   0.1950V
| Timing spec test load voltage corners
Vref   0.0000V   0.0000V   0.0000V
| Dynamic Overshoot Parameters from LPDDR4 Specification
D_overshoot_ampl_h   0.30   NA   NA
D_overshoot_ampl_l   0.30   NA   NA
D_overshoot_area_h   0.1n   NA   NA
D_overshoot_area_l   0.1n   NA   NA
[Voltage Range]   1.1000V   1.0600V   1.1700V
[Pullup Reference]   1.1000V   1.0600V   1.1700V
| Junction Temperature (Ambient temp is 35C typ 95C min -40C max)
[Temperature Range]   50.0   110.0   -40.0
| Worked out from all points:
|   slope of the pulldown table from 0 to 0.165 V, typ, clamps not added: 44.1 ohm
|   slope of the pullup table from 0 to 0.165 V, typ, clamps not added: 79.3 kohm
|   GND clamp passes 1 mA (typ) near -0.45 V on its own axis
|   POWER clamp passes 1 mA (typ) near -0.88 V on its own axis
|   rising waveform, R_fixture 50, V_fixture 0.0: 20-80 % time 55.5ps typ, 58.2ps min, 48.9ps max; typ from 0 V to 0.137 V
|   falling waveform, R_fixture 50, V_fixture 1.1: 20-80 % time 48.7ps typ, 60.7ps min, 38.7ps max; typ from 1.1 V to 0.563 V
|   rising waveform, R_fixture 50, V_fixture 1.1: 20-80 % time 56.8ps typ, 61.4ps min, 52.1ps max; typ from 0.563 V to 1.1 V
|   falling waveform, R_fixture 50, V_fixture 0.0: 20-80 % time 32.4ps typ, 40ps min, 28.4ps max; typ from 0.137 V to 0 V
[Pulldown]
|   Voltage   I(typ)   I(min)   I(max)
-1.1V     -16.51mA   -14.59mA   -18.11mA
-1.014V   -16.02mA   -15.35mA   -17.49mA
-829.4mV  -15.15mA   -15.38mA   -16.03mA
-684.2mV  -14.31mA   -14.89mA   -14.77mA
-555.5mV  -13.24mA   -13.61mA   -13.51mA
-426.8mV  -11.04mA   -11.03mA   -11.46mA
-143mV    -3.482mA   -3.501mA   -3.455mA
262.9mV   5.767mA    5.679mA    5.885mA
526.9mV   10.25mA    9.81mA     11.02mA
790.9mV   13.18mA    12.12mA    14.99mA
1.273V    16mA       14.46mA    18.98mA
2.2V      19.18mA    17.44mA    22.7mA
[GND Clamp]
|   Voltage   I(typ)   I(min)   I(max)
-1.1V     -34.74mA   -30.21mA   -42.91mA
-948.2mV  -25.43mA   -21.63mA   -31.79mA
-796.4mV  -16.11mA   -13.14mA   -21.19mA
-720.5mV  -11.75mA   -9.185mA   -15.87mA
-661.1mV  -8.566mA   -6.436mA   -11.85mA
-591.8mV  -5.256mA   -3.789mA   -7.492mA
-519.2mV  -2.565mA   -1.833mA   -3.66mA
-463.1mV  -1.235mA   -901.2uA   -1.597mA
-410.3mV  -533.2uA   -394.7uA   -580.3uA
-344.3mV  -143.3uA   -109.4uA   -124.4uA
-228.8mV  -6.811uA   -6.523uA   -3.508uA
2.2V      0A         0A         0A
[Pullup]
|   Voltage   I(typ)   I(min)   I(max)
-1.1V     1.046uA    1.612uA    471.2nA
236.5mV   -8.631uA   -8.641uA   -9.164uA
355.3mV   -78.55uA   -64.09uA   -108.2uA
460.9mV   -304.4uA   -254.6uA   -370.3uA
559.9mV   -671.2uA   -622.1uA   -724.2uA
688.6mV   -1.277mA   -1.311mA   -1.267mA
1.025V    -3.1mA     -3.52mA    -2.909mA
1.362V    -5.029mA   -5.749mA   -4.722mA
1.563V    -6.132mA   -6.933mA   -5.834mA
1.685V    -6.629mA   -7.463mA   -6.374mA
1.86V     -7.324mA   -8.019mA   -7.172mA
2.2V      -8.92mA    -8.963mA   -9.16mA
[POWER Clamp]
|   Voltage   I(typ)   I(min)   I(max)
-1.1V     3.033mA    3.633mA    2.184mA
-1.044V   2.381mA    2.967mA    1.653mA
-981.2mV  1.753mA    2.275mA    1.183mA
-915.2mV  1.223mA    1.639mA    781.2uA
-855.8mV  837.6uA    1.171mA    552.6uA
-776.6mV  434uA      683.3uA    390.2uA
-710.6mV  232.2uA    359.3uA    273.1uA
-657.8mV  146.8uA    178.8uA    190.6uA
-595.1mV  80.8uA     68.29uA    109.2uA
-492.8mV  18.91uA    11.54uA    24.06uA
-383.9mV  1.767uA    1.209uA    1.473uA
2.2V      0A         0A         0A
[Ramp]
|   typ   min   max
| 20% - 80%
dV/dt_r   82.37m/55.47p   84.13m/58.21p   87.14m/48.90p
dV/dt_f   322.26m/48.66p   303.46m/60.70p   355.99m/38.65p
| 25% - 75%
|dV/dt_r   68.64m/44.18p   70.11m/46.40p   72.62m/38.75p
|dV/dt_f   268.55m/38.81p   252.89m/48.42p   296.66m/30.77p
R_load = 50
[Rising Waveform]
R_fixture = 50
V_fixture = 0.0
|   Time   V(typ)   V(min)   V(max)
0s        85.97uV    54.11uV    70.45uV
58ps      -188.4uV   469.8uV    491.7uV
72ps      -3.272mV   -755.5uV   16.81mV
85ps      -497.1uV   -3.196mV   45.78mV
102ps     25.18mV    -481.8uV   82.73mV
118ps     57.35mV    21.91mV    106.8mV
158ps     109.4mV    90.75mV    134.6mV
190ps     126.4mV    119.4mV    141.5mV
231ps     134.2mV    133.9mV    144.3mV
421ps     137.4mV    140.3mV    145.3mV
[Falling Waveform]
R_fixture   = 50
V_fixture   = 1.1
V_fixture_min = 1.06
V_fixture_max = 1.17
|   Time   V(typ)   V(min)   V(max)
0s        1.1V       1.06V      1.17V
74ps      1.102V     1.059V     1.166V
82ps      1.105V     1.06V      1.106V
97ps      1.084V     1.063V     932.1mV
117ps     929.9mV    1.059V     745.7mV
134ps     796.1mV    984.1mV    659.7mV
155ps     683.3mV    848.5mV    610.7mV
191ps     598.5mV    678.2mV    584mV
233ps     571.4mV    593.5mV    577.9mV
421ps     562.9mV    554.2mV    576.7mV
[Rising Waveform]
R_fixture   = 50
V_fixture   = 1.1
V_fixture_min = 1.06
V_fixture_max = 1.17
|   Time   V(typ)   V(min)   V(max)
0s        562.7mV    553.9mV    576.6mV
58ps      559.1mV    550.2mV    585.1mV
66ps      564.9mV    547.7mV    627.3mV
80ps      630.3mV    559.8mV    782.7mV
95ps      764.5mV    633.3mV    910mV
113ps     884.2mV    767.7mV    1.009V
154ps     1.021V     945.5mV    1.116V
188ps     1.066V     1.008V     1.148V
231ps     1.088V     1.041V     1.163V
421ps     1.1V       1.06V      1.17V
[Falling Waveform]
R_fixture = 50
V_fixture = 0.0
|   Time   V(typ)   V(min)   V(max)
0s        137.4mV    140.4mV    145.3mV
62ps      139.3mV    141.6mV    144.2mV
72ps      139.4mV    143mV      129.4mV
82ps      134.6mV    142.9mV    87.95mV
102ps     86.3mV     127.8mV    32.33mV
117ps     44.61mV    100.1mV    15.35mV
133ps     21.39mV    59.66mV    6.985mV
157ps     7.185mV    22.15mV    2.195mV
193ps     1.53mV     4.956mV    454.1uV
421ps     145.8uV    144.5uV    87.69uV
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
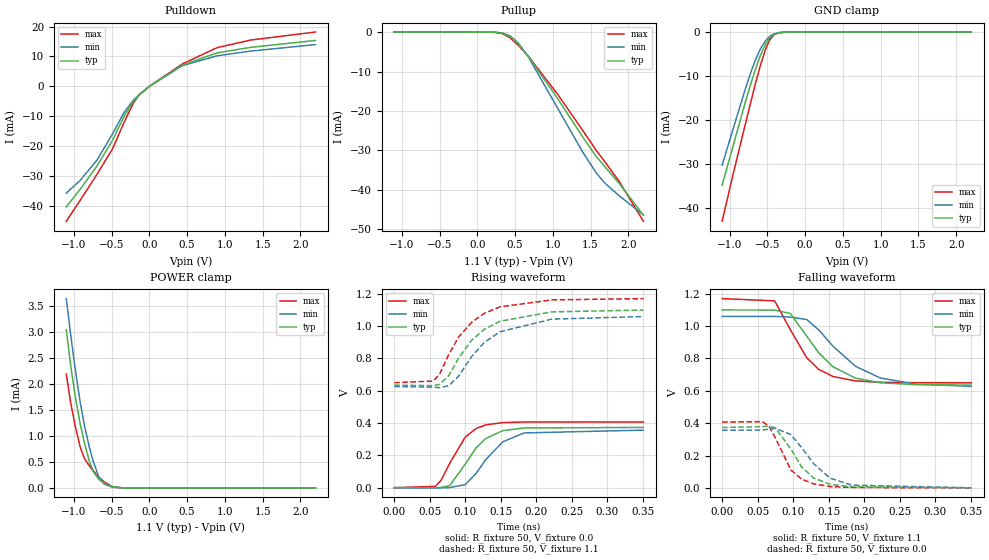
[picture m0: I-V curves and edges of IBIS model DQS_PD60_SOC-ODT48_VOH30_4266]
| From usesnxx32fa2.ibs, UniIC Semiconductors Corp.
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| DQS_PD60_SOC-ODT48_VOH30_4266
| (60 Ohm Pulldown, 48 Ohm System ODT Setting, VOH=VDDQ/3.0, 3200-4266Mbps)
[Model]   DQS_PD60_SOC-ODT48_VOH30_4266
Model_type   I/O
Vinl = 123.333mV
Vinh = 243.333mV
Vmeas = 183.333mV
Vref = 0.0mV
Cref = 0.0pF
Rref = 48.000Ohm
|   typ   min   max
|C_comp   0.849pF   0.799pF   0.899pF
C_comp_pullup   0.4245pF   0.3995pF   0.4495pF
C_comp_pulldown   0.4245pF   0.3995pF   0.4495pF
| Note: C_comp changes when the ODT circuit is enabled.
[Model Spec]
| Input threshold voltage corners
Vinl   0.1233V   0.1167V   0.1350V
Vinh   0.2433V   0.2367V   0.2550V
| Measurement voltage corners
Vmeas   0.1833V   0.1767V   0.1950V
| Timing spec test load voltage corners
Vref   0.0000V   0.0000V   0.0000V
| Dynamic Overshoot Parameters from LPDDR4 Specification
D_overshoot_ampl_h   0.30   NA   NA
D_overshoot_ampl_l   0.30   NA   NA
D_overshoot_area_h   0.1n   NA   NA
D_overshoot_area_l   0.1n   NA   NA
[Voltage Range]   1.1000V   1.0600V   1.1700V
[Pullup Reference]   1.1000V   1.0600V   1.1700V
| Junction Temperature (Ambient temp is 35C typ 95C min -40C max)
[Temperature Range]   50.0   110.0   -40.0
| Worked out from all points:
|   slope of the pulldown table from 0 to 0.165 V, typ, clamps not added: 54.8 ohm
|   slope of the pullup table from 0 to 0.165 V, typ, clamps not added: 15.6 kohm
|   GND clamp passes 1 mA (typ) near -0.45 V on its own axis
|   POWER clamp passes 1 mA (typ) near -0.88 V on its own axis
|   rising waveform, R_fixture 50, V_fixture 0.0: 20-80 % time 36.4ps typ, 40.8ps min, 32ps max; typ from 0.001 V to 0.373 V
|   falling waveform, R_fixture 50, V_fixture 1.1: 20-80 % time 53.8ps typ, 65.8ps min, 43.3ps max; typ from 1.1 V to 0.635 V
|   rising waveform, R_fixture 50, V_fixture 1.1: 20-80 % time 55.5ps typ, 58.2ps min, 52.1ps max; typ from 0.635 V to 1.1 V
|   falling waveform, R_fixture 50, V_fixture 0.0: 20-80 % time 34.8ps typ, 42.1ps min, 30ps max; typ from 0.373 V to 0.001 V
[Pulldown]
|   Voltage   I(typ)   I(min)   I(max)
-1.1V     -40.32mA   -35.72mA   -45.15mA
-918.5mV  -34.51mA   -31.53mA   -38.24mA
-694.1mV  -26.68mA   -24.71mA   -29.47mA
-486.2mV  -17.99mA   -15.86mA   -20.88mA
-334.4mV  -10.01mA   -8.751mA   -12.04mA
-209mV    -4.856mA   -4.568mA   -5.443mA
-129.8mV  -2.726mA   -2.67mA    -2.795mA
0V        -23.66uA   -20.91uA   -17uA
437.8mV   7.121mA    6.906mA    7.497mA
899.8mV   11.19mA    10.21mA    12.95mA
1.342V    13.03mA    11.78mA    15.47mA
2.2V      15.34mA    13.95mA    18.15mA
[GND Clamp]
|   Voltage   I(typ)   I(min)   I(max)
-1.1V     -34.74mA   -30.21mA   -42.91mA
-944.9mV  -25.23mA   -21.44mA   -31.55mA
-796.4mV  -16.11mA   -13.14mA   -21.19mA
-727.1mV  -12.12mA   -9.512mA   -16.33mA
-667.7mV  -8.907mA   -6.722mA   -12.29mA
-595.1mV  -5.399mA   -3.899mA   -7.688mA
-522.5mV  -2.666mA   -1.902mA   -3.811mA
-469.7mV  -1.357mA   -986uA     -1.787mA
-416.9mV  -600.7uA   -440.7uA   -665.3uA
-350.9mV  -166.3uA   -126.2uA   -147.3uA
-238.7mV  -9.223uA   -8.476uA   -5.049uA
2.2V      0A         0A         0A
[Pullup]
|   Voltage   I(typ)   I(min)   I(max)
-1.1V     5.229uA    8.059uA    2.358uA
226.6mV   -35.33uA   -36.14uA   -35.65uA
332.2mV   -268.8uA   -223.6uA   -369.7uA
431.2mV   -1.116mA   -910.3uA   -1.418mA
543.4mV   -3.046mA   -2.78mA    -3.335mA
678.7mV   -6.224mA   -6.372mA   -6.186mA
1.065V    -16.89mA   -19.32mA   -15.79mA
1.401V    -26.72mA   -30.58mA   -25.07mA
1.576V    -31.58mA   -35.72mA   -30.03mA
1.688V    -34.09mA   -38.28mA   -32.85mA
1.877V    -38.32mA   -41.48mA   -37.79mA
2.2V      -46.44mA   -46.36mA   -47.99mA
[POWER Clamp]
|   Voltage   I(typ)   I(min)   I(max)
-1.1V     3.033mA    3.633mA    2.184mA
-1.041V   2.345mA    2.929mA    1.625mA
-981.2mV  1.753mA    2.275mA    1.183mA
-915.2mV  1.224mA    1.639mA    781.5uA
-859.1mV  857.3uA    1.194mA    560.9uA
-796.4mV  521.3uA    794.8uA    427.2uA
-743.6mV  315.9uA    510.5uA    330.1uA
-671mV    164.5uA    215.9uA    210.1uA
-598.4mV  83.68uA    72uA       113.1uA
-486.2mV  16.71uA    10.18uA    20.95uA
-360.8mV  1.031uA    771.3nA    796nA
2.2V      0A         0A         0A
[Ramp]
|   typ   min   max
| 20% - 80%
dV/dt_r   223.64m/36.41p   213.59m/40.83p   243.90m/32.04p
dV/dt_f   278.78m/53.88p   259.07m/65.82p   312.07m/43.35p
| 25% - 75%
|dV/dt_r   186.37m/29.02p   178.00m/32.55p   203.25m/25.45p
|dV/dt_f   232.32m/42.88p   215.89m/52.46p   260.06m/34.50p
R_load = 50
[Rising Waveform]
R_fixture = 50
V_fixture = 0.0
|   Time   V(typ)   V(min)   V(max)
0s        584.2uV    508.9uV    424.4uV
58ps      392.9uV    -7.84uV    8.791mV
66ps      2.378mV    -432.5uV   45.62mV
78ps      12.91mV    1.071mV    149.7mV
100ps     145.2mV    19.16mV    313.2mV
115ps     244.9mV    86.49mV    365.7mV
129ps     304.9mV    174.5mV    389.1mV
153ps     353.4mV    284.3mV    403.2mV
183ps     369.9mV    339.2mV    406.5mV
351ps     373.3mV    356.5mV    406.9mV
[Falling Waveform]
R_fixture   = 50
V_fixture   = 1.1
V_fixture_min = 1.06
V_fixture_max = 1.17
|   Time   V(typ)   V(min)   V(max)
0s        1.1V       1.06V      1.17V
74ps      1.099V     1.06V      1.156V
96ps      1.078V     1.056V     979mV
119ps     939.2mV    1.041V     805.5mV
136ps     835.6mV    977.1mV    733mV
156ps     749.1mV    876.4mV    688.6mV
188ps     678.1mV    751.3mV    661.2mV
223ps     649.7mV    679.3mV    652.8mV
273ps     638.2mV    640.9mV    650.3mV
351ps     635.4mV    628.2mV    649.9mV
[Rising Waveform]
R_fixture   = 50
V_fixture   = 1.1
V_fixture_min = 1.06
V_fixture_max = 1.17
|   Time   V(typ)   V(min)   V(max)
0s        635mV      626.1mV    649.8mV
55ps      631.4mV    622.3mV    659.9mV
64ps      639.6mV    619.4mV    702.1mV
77ps      694.3mV    631.4mV    825.6mV
91ps      803.6mV    691.4mV    933.9mV
109ps     912.2mV    811.3mV    1.023V
127ps     980mV      899.5mV    1.079V
149ps     1.03V      964.9mV    1.119V
222ps     1.088V     1.043V     1.162V
351ps     1.099V     1.059V     1.17V
[Falling Waveform]
R_fixture = 50
V_fixture = 0.0
|   Time   V(typ)   V(min)   V(max)
0s        373.4mV    356.6mV    407mV
57ps      379mV      357.7mV    409.6mV
66ps      381.8mV    363.1mV    381.1mV
75ps      371.3mV    368mV      308.6mV
97ps      239.5mV    329.7mV    110.6mV
112ps     129mV      248.6mV    54.33mV
129ps     61.12mV    149.7mV    24.58mV
152ps     22.45mV    60.15mV    8.677mV
183ps     6.317mV    16.86mV    2.436mV
351ps     653.4uV    625.9uV    445.5uV
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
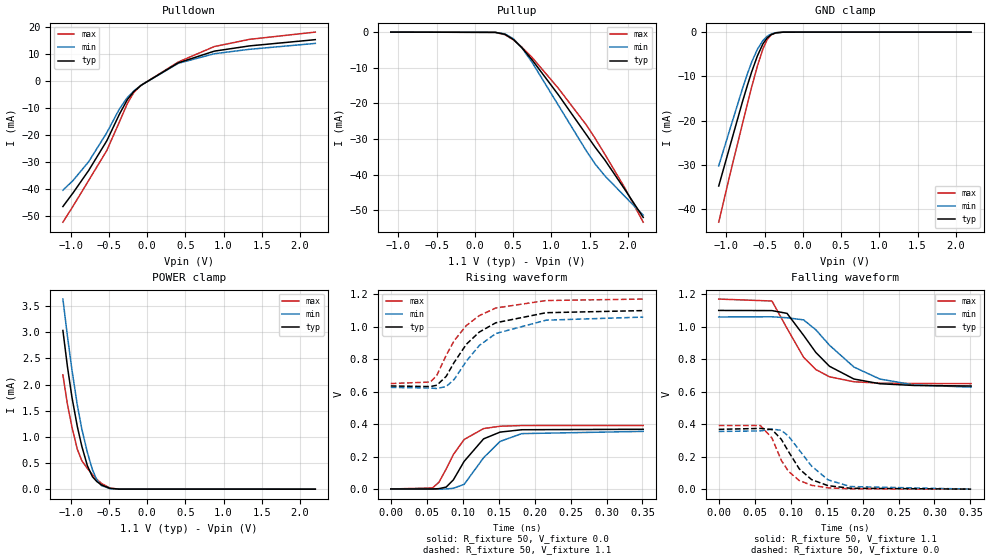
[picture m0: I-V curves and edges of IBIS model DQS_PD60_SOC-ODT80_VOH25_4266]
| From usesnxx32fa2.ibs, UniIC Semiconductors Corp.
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| DQS_PD60_SOC-ODT80_VOH25_4266
| (60 Ohm Pulldown, 80 Ohm System ODT Setting, VOH=VDDQ/2.5, 3200-4266Mbps)
[Model]   DQS_PD60_SOC-ODT80_VOH25_4266
Model_type   I/O
Vinl = 160.000mV
Vinh = 280.000mV
Vmeas = 220.000mV
Vref = 0.0mV
Cref = 0.0pF
Rref = 80.000Ohm
|   typ   min   max
|C_comp   0.849pF   0.799pF   0.899pF
C_comp_pullup   0.4245pF   0.3995pF   0.4495pF
C_comp_pulldown   0.4245pF   0.3995pF   0.4495pF
| Note: C_comp changes when the ODT circuit is enabled.
[Model Spec]
| Input threshold voltage corners
Vinl   0.1600V   0.1520V   0.1740V
Vinh   0.2800V   0.2720V   0.2940V
| Measurement voltage corners
Vmeas   0.2200V   0.2120V   0.2340V
| Timing spec test load voltage corners
Vref   0.0000V   0.0000V   0.0000V
| Dynamic Overshoot Parameters from LPDDR4 Specification
D_overshoot_ampl_h   0.30   NA   NA
D_overshoot_ampl_l   0.30   NA   NA
D_overshoot_area_h   0.1n   NA   NA
D_overshoot_area_l   0.1n   NA   NA
[Voltage Range]   1.1000V   1.0600V   1.1700V
[Pullup Reference]   1.1000V   1.0600V   1.1700V
| Junction Temperature (Ambient temp is 35C typ 95C min -40C max)
[Temperature Range]   50.0   110.0   -40.0
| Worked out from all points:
|   slope of the pulldown table from 0 to 0.165 V, typ, clamps not added: 54.7 ohm
|   slope of the pullup table from 0 to 0.165 V, typ, clamps not added: 17.7 kohm
|   GND clamp passes 1 mA (typ) near -0.45 V on its own axis
|   POWER clamp passes 1 mA (typ) near -0.88 V on its own axis
|   rising waveform, R_fixture 50, V_fixture 0.0: 20-80 % time 35ps typ, 38.6ps min, 31.9ps max; typ from 0.001 V to 0.368 V
|   falling waveform, R_fixture 50, V_fixture 1.1: 20-80 % time 53.8ps typ, 66.1ps min, 43.3ps max; typ from 1.1 V to 0.635 V
|   rising waveform, R_fixture 50, V_fixture 1.1: 20-80 % time 55.5ps typ, 58.5ps min, 51.9ps max; typ from 0.635 V to 1.1 V
|   falling waveform, R_fixture 50, V_fixture 0.0: 20-80 % time 35.1ps typ, 42.1ps min, 29.8ps max; typ from 0.368 V to 0.001 V
[Pulldown]
|   Voltage   I(typ)   I(min)   I(max)
-1.1V     -46.59mA   -40.55mA   -52.4mA
-964.7mV  -41.42mA   -36.85mA   -46.33mA
-763.4mV  -33.22mA   -29.97mA   -36.93mA
-525.8mV  -22.18mA   -19.19mA   -25.77mA
-360.8mV  -12.31mA   -10.36mA   -15.17mA
-255.2mV  -6.824mA   -6.049mA   -8.222mA
-172.7mV  -3.909mA   -3.703mA   -4.272mA
-77mV     -1.59mA    -1.563mA   -1.582mA
408.1mV   6.732mA    6.55mA     7.044mA
880mV     11.08mA    10.12mA    12.78mA
1.339V    13.02mA    11.76mA    15.45mA
2.2V      15.34mA    13.95mA    18.15mA
[GND Clamp]
|   Voltage   I(typ)   I(min)   I(max)
-1.1V     -34.75mA   -30.2mA    -42.92mA
-944.9mV  -25.23mA   -21.44mA   -31.56mA
-789.8mV  -15.73mA   -12.78mA   -20.73mA
-723.8mV  -11.94mA   -9.346mA   -16.11mA
-667.7mV  -8.911mA   -6.72mA    -12.3mA
-595.1mV  -5.401mA   -3.898mA   -7.696mA
-522.5mV  -2.665mA   -1.902mA   -3.814mA
-466.4mV  -1.3mA     -941.3uA   -1.692mA
-413.6mV  -567.7uA   -416.6uA   -621.5uA
-354.2mV  -179.6uA   -134.7uA   -160.1uA
-255.2mV  -14.6uA    -12.93uA   -8.859uA
2.2V      0A         0A         0A
[Pullup]
|   Voltage   I(typ)   I(min)   I(max)
-1.1V     4.106uA    7.431uA    1.361uA
266.2mV   -69.36uA   -66.65uA   -71.81uA
394.9mV   -631.9uA   -524.2uA   -750.4uA
507.1mV   -2.157mA   -1.952mA   -2.25mA
612.7mV   -4.374mA   -4.386mA   -4.194mA
744.7mV   -7.716mA   -8.411mA   -7.051mA
1.088V    -17.54mA   -20.45mA   -15.71mA
1.458V    -28.85mA   -33.42mA   -26.13mA
1.573V    -32.37mA   -37.08mA   -29.9mA
1.698V    -35.91mA   -40.36mA   -34.29mA
1.956V    -44.08mA   -46.07mA   -43.63mA
2.2V      -52.05mA   -51.4mA    -53.39mA
[POWER Clamp]
|   Voltage   I(typ)   I(min)   I(max)
-1.1V     3.033mA    3.633mA    2.184mA
-1.041V   2.345mA    2.929mA    1.625mA
-981.2mV  1.753mA    2.275mA    1.183mA
-911.9mV  1.2mA      1.61mA     764.5uA
-852.5mV  818.3uA    1.148mA    543.7uA
-779.9mV  447.9uA    701.4uA    396.3uA
-713.9mV  239.2uA    373uA      278.6uA
-657.8mV  146.8uA    178.9uA    190.6uA
-595.1mV  80.74uA    68.29uA    109.3uA
-486.2mV  16.78uA    10.13uA    20.96uA
-367.4mV  1.203uA    872.8nA    947.4nA
2.2V      0A         0A         0A
[Ramp]
|   typ   min   max
| 20% - 80%
dV/dt_r   220.58m/34.98p   212.91m/38.64p   234.66m/31.86p
dV/dt_f   278.79m/53.87p   259.07m/66.15p   312.07m/43.34p
| 25% - 75%
|dV/dt_r   183.82m/27.84p   177.42m/30.78p   195.55m/25.31p
|dV/dt_f   232.33m/42.89p   215.89m/52.71p   260.06m/34.44p
R_load = 50
[Rising Waveform]
R_fixture = 50
V_fixture = 0.0
|   Time   V(typ)   V(min)   V(max)
0s        727.4uV    593.5uV    534.4uV
58ps      505.6uV    12.21uV    7.106mV
67ps      2.893mV    -473.1uV   42.34mV
77ps      12.29mV    918.3uV    123.7mV
87ps      56.86mV    4.918mV    212.8mV
102ps     170.9mV    29.17mV    305.4mV
129ps     309.2mV    192.9mV    372.7mV
152ps     350.9mV    293.6mV    387.1mV
182ps     365.4mV    341.5mV    391.1mV
351ps     368.4mV    355.4mV    391.6mV
[Falling Waveform]
R_fixture   = 50
V_fixture   = 1.1
V_fixture_min = 1.06
V_fixture_max = 1.17
|   Time   V(typ)   V(min)   V(max)
0s        1.1V       1.06V      1.17V
74ps      1.099V     1.061V     1.158V
95ps      1.082V     1.055V     989.8mV
118ps     946.9mV    1.042V     811.9mV
135ps     841.8mV    981.1mV    736.6mV
154ps     756.5mV    886.2mV    691.9mV
188ps     678.2mV    751.8mV    661.3mV
224ps     649.2mV    678.1mV    652.7mV
272ps     638.3mV    641.3mV    650.3mV
351ps     635.3mV    628.2mV    649.9mV
[Rising Waveform]
R_fixture   = 50
V_fixture   = 1.1
V_fixture_min = 1.06
V_fixture_max = 1.17
|   Time   V(typ)   V(min)   V(max)
0s        635mV      626.1mV    649.8mV
55ps      631.3mV    622.3mV    659.1mV
64ps      639.5mV    619.3mV    700.4mV
77ps      694mV      631.4mV    823.7mV
88ps      779.5mV    674.8mV    913mV
105ps     891.5mV    787.2mV    1.007V
123ps     966.8mV    884.1mV    1.068V
146ps     1.024V     957.8mV    1.115V
216ps     1.086V     1.04V      1.161V
351ps     1.099V     1.059V     1.17V
[Falling Waveform]
R_fixture = 50
V_fixture = 0.0
|   Time   V(typ)   V(min)   V(max)
0s        368.5mV    355.6mV    391.7mV
58ps      374.3mV    358.9mV    391.9mV
74ps      367.4mV    370.2mV    315.1mV
87ps      307.5mV    362.6mV    178.3mV
97ps      232mV      327.4mV    109.9mV
112ps     125.4mV    240.7mV    53.84mV
129ps     59.65mV    143.3mV    24.4mV
152ps     22.03mV    58.01mV    8.687mV
183ps     6.28mV     16.71mV    2.471mV
351ps     779.8uV    697.8uV    553.4uV
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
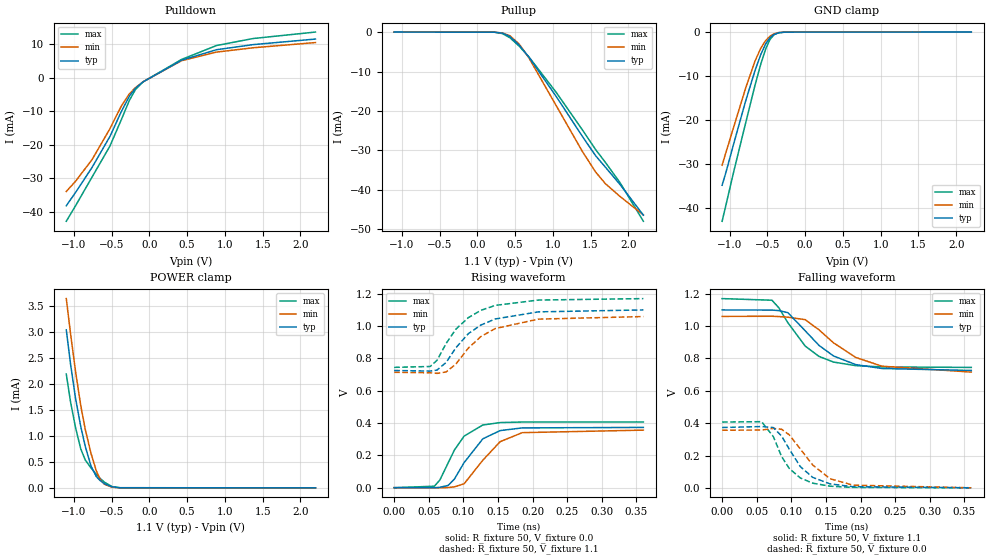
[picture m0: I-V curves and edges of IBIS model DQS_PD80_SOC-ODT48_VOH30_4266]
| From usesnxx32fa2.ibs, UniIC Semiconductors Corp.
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| DQS_PD80_SOC-ODT48_VOH30_4266
| (80 Ohm Pulldown, 48 Ohm System ODT Setting, VOH=VDDQ/3.0, 3200-4266Mbps)
[Model]   DQS_PD80_SOC-ODT48_VOH30_4266
Model_type   I/O
Vinl = 123.333mV
Vinh = 243.333mV
Vmeas = 183.333mV
Vref = 0.0mV
Cref = 0.0pF
Rref = 48.000Ohm
|   typ   min   max
|C_comp   0.849pF   0.799pF   0.899pF
C_comp_pullup   0.4245pF   0.3995pF   0.4495pF
C_comp_pulldown   0.4245pF   0.3995pF   0.4495pF
| Note: C_comp changes when the ODT circuit is enabled.
[Model Spec]
| Input threshold voltage corners
Vinl   0.1233V   0.1167V   0.1350V
Vinh   0.2433V   0.2367V   0.2550V
| Measurement voltage corners
Vmeas   0.1833V   0.1767V   0.1950V
| Timing spec test load voltage corners
Vref   0.0000V   0.0000V   0.0000V
| Dynamic Overshoot Parameters from LPDDR4 Specification
D_overshoot_ampl_h   0.30   NA   NA
D_overshoot_ampl_l   0.30   NA   NA
D_overshoot_area_h   0.1n   NA   NA
D_overshoot_area_l   0.1n   NA   NA
[Voltage Range]   1.1000V   1.0600V   1.1700V
[Pullup Reference]   1.1000V   1.0600V   1.1700V
| Junction Temperature (Ambient temp is 35C typ 95C min -40C max)
[Temperature Range]   50.0   110.0   -40.0
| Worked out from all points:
|   slope of the pulldown table from 0 to 0.165 V, typ, clamps not added: 74 ohm
|   slope of the pullup table from 0 to 0.165 V, typ, clamps not added: 15.7 kohm
|   GND clamp passes 1 mA (typ) near -0.45 V on its own axis
|   POWER clamp passes 1 mA (typ) near -0.88 V on its own axis
|   rising waveform, R_fixture 50, V_fixture 0.0: 20-80 % time 36.6ps typ, 41.1ps min, 32.1ps max; typ from 0.001 V to 0.373 V
|   falling waveform, R_fixture 50, V_fixture 1.1: 20-80 % time 58.1ps typ, 68.6ps min, 47.3ps max; typ from 1.1 V to 0.726 V
|   rising waveform, R_fixture 50, V_fixture 1.1: 20-80 % time 54.9ps typ, 56.5ps min, 52ps max; typ from 0.726 V to 1.1 V
|   falling waveform, R_fixture 50, V_fixture 0.0: 20-80 % time 38.1ps typ, 44.4ps min, 33ps max; typ from 0.373 V to 0.001 V
[Pulldown]
|   Voltage   I(typ)   I(min)   I(max)
-1.1V     -38.21mA   -33.94mA   -42.83mA
-977.9mV  -34.26mA   -30.94mA   -38.23mA
-756.8mV  -26.71mA   -24.37mA   -29.58mA
-522.5mV  -17.57mA   -15.27mA   -20.44mA
-370.7mV  -10.11mA   -8.473mA   -12.53mA
-265.1mV  -5.559mA   -4.867mA   -6.822mA
-182.6mV  -3.159mA   -2.966mA   -3.524mA
-83.6mV   -1.288mA   -1.266mA   -1.283mA
427.9mV   5.179mA    5.041mA    5.417mA
889.9mV   8.305mA    7.596mA    9.551mA
1.375V    9.822mA    8.882mA    11.64mA
2.2V      11.48mA    10.44mA    13.57mA
[GND Clamp]
|   Voltage   I(typ)   I(min)   I(max)
-1.1V     -34.74mA   -30.21mA   -42.91mA
-1.05V    -31.86mA   -27.33mA   -39.27mA
-941.6mV  -25.02mA   -21.26mA   -31.32mA
-789.8mV  -15.72mA   -12.78mA   -20.72mA
-664.4mV  -8.736mA   -6.578mA   -12.07mA
-588.5mV  -5.113mA   -3.681mA   -7.299mA
-522.5mV  -2.664mA   -1.903mA   -3.811mA
-466.4mV  -1.295mA   -942.8uA   -1.69mA
-413.6mV  -565.8uA   -416.5uA   -620.2uA
-354.2mV  -178.7uA   -134.8uA   -159uA
-265.1mV  -19.44uA   -16.77uA   -12.17uA
2.2V      0A         0A         0A
[Pullup]
|   Voltage   I(typ)   I(min)   I(max)
-1.1V     5.229uA    8.059uA    2.358uA
229.9mV   -37.61uA   -38.47uA   -38.81uA
335.5mV   -284.3uA   -236uA     -391.5uA
434.5mV   -1.16mA    -949.4uA   -1.465mA
556.6mV   -3.328mA   -3.076mA   -3.593mA
685.3mV   -6.393mA   -6.572mA   -6.335mA
1.048V    -16.41mA   -18.75mA   -15.36mA
1.395V    -26.53mA   -30.37mA   -24.88mA
1.566V    -31.33mA   -35.46mA   -29.76mA
1.698V    -34.29mA   -38.48mA   -33.08mA
1.89V     -38.64mA   -41.69mA   -38.17mA
2.2V      -46.44mA   -46.38mA   -47.99mA
[POWER Clamp]
|   Voltage   I(typ)   I(min)   I(max)
-1.1V     3.033mA    3.633mA    2.184mA
-1.044V   2.381mA    2.967mA    1.653mA
-977.9mV  1.723mA    2.241mA    1.16mA
-908.6mV  1.178mA    1.582mA    748.2uA
-849.2mV  799.1uA    1.126mA    535.5uA
-773.3mV  420.8uA    665.2uA    384.1uA
-704mV    218.9uA    332uA      262.1uA
-651.2mV  138.6uA    162.3uA    181.2uA
-595.1mV  80.74uA    68.36uA    109.2uA
-496.1mV  20.1uA     12.33uA    25.71uA
-393.8mV  2.208uA    1.486uA    1.931uA
2.2V      0A         0A         0A
[Ramp]
|   typ   min   max
| 20% - 80%
dV/dt_r   223.59m/36.62p   213.55m/41.15p   243.87m/32.09p
dV/dt_f   224.45m/58.01p   206.40m/68.64p   255.16m/47.36p
| 25% - 75%
|dV/dt_r   186.32m/29.17p   177.96m/32.83p   203.22m/25.53p
|dV/dt_f   187.04m/46.20p   172.00m/54.54p   212.63m/37.58p
R_load = 50
[Rising Waveform]
R_fixture = 50
V_fixture = 0.0
|   Time   V(typ)   V(min)   V(max)
0s        672.2uV    588.8uV    486.9uV
58ps      372.1uV    -79.65uV   9.572mV
66ps      2.788mV    -431.2uV   47.87mV
78ps      14.63mV    1.706mV    154.3mV
87ps      53.9mV     5.601mV    233.4mV
101ps     155.6mV    24.41mV    319.5mV
128ps     302.6mV    170.2mV    388.2mV
153ps     353.6mV    284.9mV    403.2mV
185ps     370.3mV    340.9mV    406.6mV
360ps     373.3mV    356.5mV    406.9mV
[Falling Waveform]
R_fixture   = 50
V_fixture   = 1.1
V_fixture_min = 1.06
V_fixture_max = 1.17
|   Time   V(typ)   V(min)   V(max)
0s        1.1V       1.06V      1.17V
72ps      1.099V     1.061V     1.16V
82ps      1.096V     1.059V     1.113V
95ps      1.083V     1.055V     1.021V
120ps     971.3mV    1.04V      876.7mV
140ps     880.8mV    976.9mV    812.7mV
161ps     815.3mV    896.5mV    777.8mV
193ps     762.1mV    806.6mV    755.7mV
231ps     737.9mV    752.2mV    747.7mV
360ps     725.9mV    716mV      744.7mV
[Rising Waveform]
R_fixture   = 50
V_fixture   = 1.1
V_fixture_min = 1.06
V_fixture_max = 1.17
|   Time   V(typ)   V(min)   V(max)
0s        725.5mV    714.2mV    744.7mV
52ps      721.6mV    711.2mV    750.1mV
62ps      728.2mV    707.6mV    788.9mV
75ps      775.1mV    716.3mV    892.3mV
89ps      865.3mV    764.5mV    980.3mV
107ps     952.8mV    863.2mV    1.052V
125ps     1.006V     934.7mV    1.097V
146ps     1.044V     984.8mV    1.128V
208ps     1.088V     1.043V     1.161V
360ps     1.1V       1.059V     1.17V
[Falling Waveform]
R_fixture = 50
V_fixture = 0.0
|   Time   V(typ)   V(min)   V(max)
0s        373.4mV    356.6mV    407mV
57ps      379.2mV    357.7mV    409.5mV
74ps      373.1mV    367.8mV    317.1mV
86ps      320.2mV    362.3mV    193.4mV
97ps      239.7mV    328.5mV    120.3mV
113ps     131.5mV    240.5mV    61.44mV
131ps     64.96mV    141.1mV    29.19mV
156ps     24.81mV    56.89mV    10.67mV
189ps     7.517mV    17.05mV    3.113mV
360ps     751.8uV    729.3uV    513.7uV
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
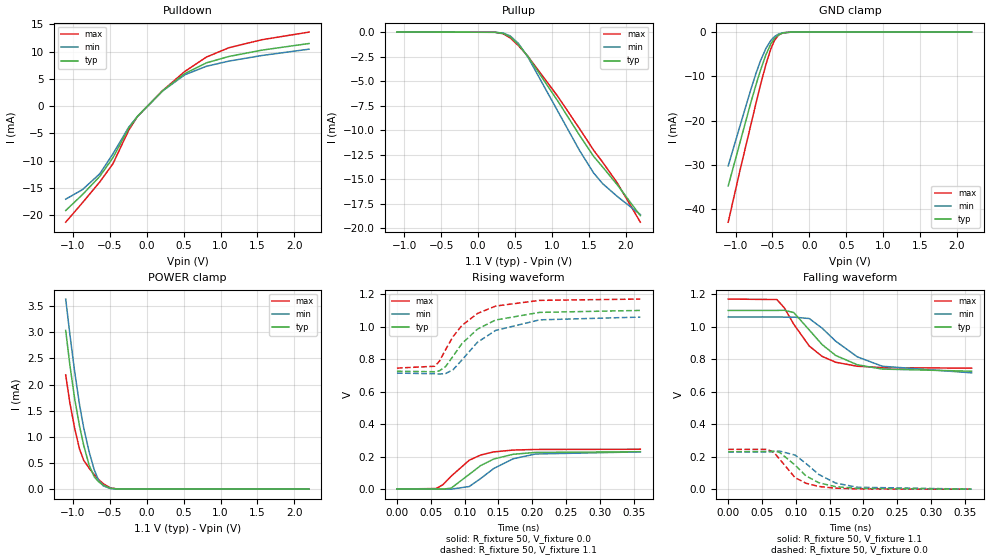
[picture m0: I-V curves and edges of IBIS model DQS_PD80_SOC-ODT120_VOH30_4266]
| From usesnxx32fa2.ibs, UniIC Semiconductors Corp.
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| DQS_PD80_SOC-ODT120_VOH30_4266
| (80 Ohm Pulldown, 120 Ohm System ODT Setting, VOH=VDDQ/3.0, 3200-4266Mbps)
[Model]   DQS_PD80_SOC-ODT120_VOH30_4266
Model_type   I/O
Vinl = 123.333mV
Vinh = 243.333mV
Vmeas = 183.333mV
Vref = 0.0mV
Cref = 0.0pF
Rref = 120.000Ohm
|   typ   min   max
|C_comp   0.849pF   0.799pF   0.899pF
C_comp_pullup   0.4245pF   0.3995pF   0.4495pF
C_comp_pulldown   0.4245pF   0.3995pF   0.4495pF
| Note: C_comp changes when the ODT circuit is enabled.
[Model Spec]
| Input threshold voltage corners
Vinl   0.1233V   0.1167V   0.1350V
Vinh   0.2433V   0.2367V   0.2550V
| Measurement voltage corners
Vmeas   0.1833V   0.1767V   0.1950V
| Timing spec test load voltage corners
Vref   0.0000V   0.0000V   0.0000V
| Dynamic Overshoot Parameters from LPDDR4 Specification
D_overshoot_ampl_h   0.30   NA   NA
D_overshoot_ampl_l   0.30   NA   NA
D_overshoot_area_h   0.1n   NA   NA
D_overshoot_area_l   0.1n   NA   NA
[Voltage Range]   1.1000V   1.0600V   1.1700V
[Pullup Reference]   1.1000V   1.0600V   1.1700V
| Junction Temperature (Ambient temp is 35C typ 95C min -40C max)
[Temperature Range]   50.0   110.0   -40.0
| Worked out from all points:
|   slope of the pulldown table from 0 to 0.165 V, typ, clamps not added: 74.4 ohm
|   slope of the pullup table from 0 to 0.165 V, typ, clamps not added: 39.1 kohm
|   GND clamp passes 1 mA (typ) near -0.45 V on its own axis
|   POWER clamp passes 1 mA (typ) near -0.88 V on its own axis
|   rising waveform, R_fixture 50, V_fixture 0.0: 20-80 % time 47.3ps typ, 51.6ps min, 41.9ps max; typ from 0 V to 0.23 V
|   falling waveform, R_fixture 50, V_fixture 1.1: 20-80 % time 57.3ps typ, 67.4ps min, 46.7ps max; typ from 1.1 V to 0.726 V
|   rising waveform, R_fixture 50, V_fixture 1.1: 20-80 % time 56.2ps typ, 59.4ps min, 51.9ps max; typ from 0.726 V to 1.1 V
|   falling waveform, R_fixture 50, V_fixture 0.0: 20-80 % time 38.6ps typ, 45.4ps min, 33.7ps max; typ from 0.23 V to 0 V
[Pulldown]
|   Voltage   I(typ)   I(min)   I(max)
-1.1V     -19.12mA   -17.04mA   -21.26mA
-872.3mV  -16.2mA    -15.29mA   -17.69mA
-638mV    -12.87mA   -12.39mA   -13.89mA
-459.8mV  -9.458mA   -8.75mA    -10.56mA
-245.3mV  -4.032mA   -3.855mA   -4.404mA
-126.5mV  -1.877mA   -1.865mA   -1.882mA
213.4mV   2.813mA    2.783mA    2.836mA
517mV     5.991mA    5.763mA    6.383mA
810.7mV   7.944mA    7.315mA    9.013mA
1.114V    9.108mA    8.255mA    10.71mA
1.56V     10.26mA    9.279mA    12.17mA
2.2V      11.48mA    10.44mA    13.57mA
[GND Clamp]
|   Voltage   I(typ)   I(min)   I(max)
-1.1V     -34.74mA   -30.21mA   -42.91mA
-941.6mV  -25.02mA   -21.26mA   -31.32mA
-796.4mV  -16.11mA   -13.14mA   -21.19mA
-720.5mV  -11.75mA   -9.185mA   -15.87mA
-661.1mV  -8.566mA   -6.435mA   -11.85mA
-588.5mV  -5.112mA   -3.681mA   -7.299mA
-522.5mV  -2.664mA   -1.902mA   -3.81mA
-473mV    -1.421mA   -1.032mA   -1.887mA
-416.9mV  -598.3uA   -441.3uA   -666.3uA
-357.5mV  -191.1uA   -145.2uA   -173.9uA
-248.6mV  -12.11uA   -11.01uA   -7.142uA
2.2V      0A         0A         0A
[Pullup]
|   Voltage   I(typ)   I(min)   I(max)
-1.1V     2.092uA    3.224uA    943.2nA
229.9mV   -15.06uA   -15.21uA   -15.56uA
342.1mV   -128uA     -105.1uA   -175.9uA
434.5mV   -465.9uA   -380.6uA   -589.2uA
546.7mV   -1.257mA   -1.152mA   -1.37mA
675.4mV   -2.482mA   -2.542mA   -2.466mA
1.081V    -7.027mA   -8.071mA   -6.561mA
1.378V    -10.55mA   -12.1mA    -9.873mA
1.566V    -12.67mA   -14.36mA   -12.04mA
1.688V    -13.75mA   -15.45mA   -13.26mA
1.887V    -15.57mA   -16.76mA   -15.38mA
2.2V      -18.72mA   -18.61mA   -19.39mA
[POWER Clamp]
|   Voltage   I(typ)   I(min)   I(max)
-1.1V     3.033mA    3.633mA    2.184mA
-1.044V   2.381mA    2.967mA    1.653mA
-977.9mV  1.723mA    2.241mA    1.16mA
-911.9mV  1.201mA    1.611mA    764.3uA
-855.8mV  837.7uA    1.171mA    552.1uA
-783.2mV  462uA      719.8uA    402.4uA
-713.9mV  239.3uA    373uA      278.6uA
-654.5mV  142.7uA    170.4uA    185.9uA
-591.8mV  77.95uA    64.83uA    105.5uA
-496.1mV  20.07uA    12.3uA     25.72uA
-393.8mV  2.209uA    1.492uA    1.94uA
2.2V      0A         0A         0A
[Ramp]
|   typ   min   max
| 20% - 80%
dV/dt_r   137.74m/47.27p   137.30m/51.57p   146.95m/41.87p
dV/dt_f   224.45m/57.20p   206.41m/67.44p   255.15m/46.77p
| 25% - 75%
|dV/dt_r   114.79m/37.69p   114.42m/41.15p   122.46m/33.25p
|dV/dt_f   187.04m/45.54p   172.01m/53.73p   212.62m/37.19p
R_load = 50
[Rising Waveform]
R_fixture = 50
V_fixture = 0.0
|   Time   V(typ)   V(min)   V(max)
0s        261.2uV    217.8uV    193.6uV
58ps      -285.1uV   152.7uV    2.964mV
68ps      -394uV     -483.8uV   26.93mV
80ps      5.041mV    -750.6uV   78.48mV
107ps     90.6mV     15.61mV    177.7mV
124ps     145mV      65.21mV    209.9mV
143ps     184.7mV    126mV      228.7mV
172ps     214.1mV    186.5mV    240.1mV
205ps     225.5mV    215.8mV    243.8mV
360ps     229.8mV    229mV      245.1mV
[Falling Waveform]
R_fixture   = 50
V_fixture   = 1.1
V_fixture_min = 1.06
V_fixture_max = 1.17
|   Time   V(typ)   V(min)   V(max)
0s        1.1V       1.06V      1.17V
72ps      1.1V       1.06V      1.167V
83ps      1.101V     1.059V     1.116V
97ps      1.087V     1.059V     1.015V
120ps     979.2mV    1.05V      880.5mV
139ps     889.6mV    990.7mV    817mV
159ps     823mV      910.8mV    781.1mV
191ps     765.5mV    814.4mV    756.6mV
228ps     739.2mV    756.5mV    748mV
360ps     725.9mV    716mV      744.8mV
[Rising Waveform]
R_fixture   = 50
V_fixture   = 1.1
V_fixture_min = 1.06
V_fixture_max = 1.17
|   Time   V(typ)   V(min)   V(max)
0s        725.5mV    714.2mV    744.7mV
56ps      722.4mV    710mV      756.3mV
63ps      728.5mV    708.1mV    788.1mV
72ps      754.7mV    711.4mV    858.9mV
83ps      817.6mV    734.7mV    939.1mV
96ps      895.5mV    794.1mV    1.007V
119ps     984.6mV    903.8mV    1.081V
146ps     1.041V     976.9mV    1.127V
211ps     1.088V     1.042V     1.162V
360ps     1.1V       1.059V     1.17V
[Falling Waveform]
R_fixture = 50
V_fixture = 0.0
|   Time   V(typ)   V(min)   V(max)
0s        229.9mV    229.2mV    245.2mV
58ps      232.5mV    229.6mV    245.3mV
68ps      233.1mV    232.6mV    224.7mV
76ps      226.9mV    234.4mV    184.7mV
99ps      148mV      209.8mV    70.93mV
115ps     82.08mV    158.5mV    36.7mV
134ps     39.63mV    90.69mV    16.79mV
159ps     15.38mV    37.55mV    6.139mV
191ps     4.783mV    12.04mV    1.818mV
360ps     350.3uV    363.3uV    223.3uV
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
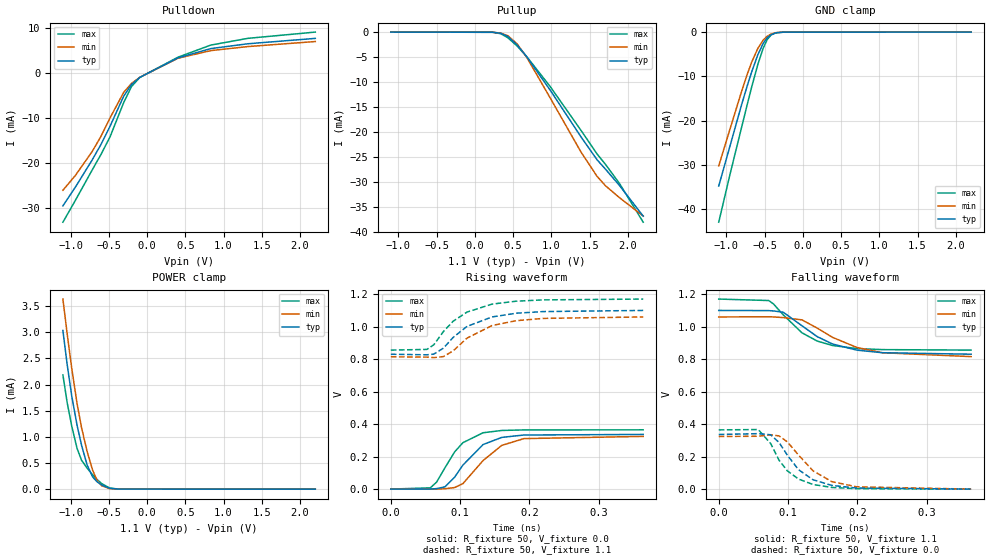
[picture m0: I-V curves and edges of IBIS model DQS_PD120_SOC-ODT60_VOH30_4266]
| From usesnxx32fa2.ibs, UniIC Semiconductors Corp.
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| DQS_PD120_SOC-ODT60_VOH30_4266
| (120 Ohm Pulldown, 60 Ohm System ODT Setting, VOH=VDDQ/3.0, 3200-4266Mbps)
[Model]   DQS_PD120_SOC-ODT60_VOH30_4266
Model_type   I/O
Vinl = 123.333mV
Vinh = 243.333mV
Vmeas = 183.333mV
Vref = 0.0mV
Cref = 0.0pF
Rref = 60.000Ohm
|   typ   min   max
|C_comp   0.849pF   0.799pF   0.899pF
C_comp_pullup   0.4245pF   0.3995pF   0.4495pF
C_comp_pulldown   0.4245pF   0.3995pF   0.4495pF
| Note: C_comp changes when the ODT circuit is enabled.
[Model Spec]
| Input threshold voltage corners
Vinl   0.1233V   0.1167V   0.1350V
Vinh   0.2433V   0.2367V   0.2550V
| Measurement voltage corners
Vmeas   0.1833V   0.1767V   0.1950V
| Timing spec test load voltage corners
Vref   0.0000V   0.0000V   0.0000V
| Dynamic Overshoot Parameters from LPDDR4 Specification
D_overshoot_ampl_h   0.30   NA   NA
D_overshoot_ampl_l   0.30   NA   NA
D_overshoot_area_h   0.1n   NA   NA
D_overshoot_area_l   0.1n   NA   NA
[Voltage Range]   1.1000V   1.0600V   1.1700V
[Pullup Reference]   1.1000V   1.0600V   1.1700V
| Junction Temperature (Ambient temp is 35C typ 95C min -40C max)
[Temperature Range]   50.0   110.0   -40.0
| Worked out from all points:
|   slope of the pulldown table from 0 to 0.165 V, typ, clamps not added: 109 ohm
|   slope of the pullup table from 0 to 0.165 V, typ, clamps not added: 19.5 kohm
|   GND clamp passes 1 mA (typ) near -0.45 V on its own axis
|   POWER clamp passes 1 mA (typ) near -0.88 V on its own axis
|   rising waveform, R_fixture 50, V_fixture 0.0: 20-80 % time 40.3ps typ, 44.4ps min, 35.2ps max; typ from 0.001 V to 0.337 V
|   falling waveform, R_fixture 50, V_fixture 1.1: 20-80 % time 61.4ps typ, 71ps min, 51.9ps max; typ from 1.1 V to 0.831 V
|   rising waveform, R_fixture 50, V_fixture 1.1: 20-80 % time 54.5ps typ, 56.7ps min, 52ps max; typ from 0.83 V to 1.1 V
|   falling waveform, R_fixture 50, V_fixture 0.0: 20-80 % time 41.6ps typ, 47.2ps min, 37ps max; typ from 0.337 V to 0.001 V
[Pulldown]
|   Voltage   I(typ)   I(min)   I(max)
-1.1V     -29.57mA   -26.1mA    -33.2mA
-938.3mV  -25.44mA   -22.84mA   -28.39mA
-717.2mV  -19.36mA   -17.49mA   -21.59mA
-605mV    -16.01mA   -14.2mA    -18.23mA
-482.9mV  -11.84mA   -9.994mA   -14.2mA
-304.7mV  -5.172mA   -4.319mA   -6.585mA
-202.4mV  -2.573mA   -2.34mA    -3.02mA
-93.5mV   -998.5uA   -973.7uA   -1.006mA
404.8mV   3.34mA     3.253mA    3.489mA
833.8mV   5.402mA    4.953mA    6.181mA
1.319V    6.474mA    5.851mA    7.68mA
2.2V      7.669mA    6.972mA    9.07mA
[GND Clamp]
|   Voltage   I(typ)   I(min)   I(max)
-1.1V     -34.74mA   -30.21mA   -42.91mA
-944.9mV  -25.23mA   -21.44mA   -31.55mA
-803mV    -16.5mA    -13.5mA    -21.65mA
-727.1mV  -12.12mA   -9.513mA   -16.33mA
-667.7mV  -8.907mA   -6.722mA   -12.29mA
-588.5mV  -5.112mA   -3.681mA   -7.298mA
-519.2mV  -2.565mA   -1.832mA   -3.66mA
-466.4mV  -1.295mA   -941.7uA   -1.69mA
-413.6mV  -563.7uA   -417.4uA   -620.6uA
-350.9mV  -166.2uA   -126uA     -147.5uA
-245.3mV  -11.25uA   -10.08uA   -6.359uA
2.2V      0A         0A         0A
[Pullup]
|   Voltage   I(typ)   I(min)   I(max)
-1.1V     4.184uA    6.447uA    1.886uA
233.2mV   -32.26uA   -32.48uA   -33.79uA
335.5mV   -227.5uA   -188.9uA   -313.1uA
431.2mV   -891.1uA   -727.6uA   -1.133mA
550mV     -2.544mA   -2.338mA   -2.768mA
675.4mV   -4.904mA   -5.008mA   -4.883mA
982.3mV   -11.6mA    -13.15mA   -10.88mA
1.388V    -21.03mA   -24.07mA   -19.73mA
1.596V    -25.58mA   -28.9mA    -24.41mA
1.708V    -27.49mA   -30.81mA   -26.54mA
1.89V     -30.74mA   -33.19mA   -30.34mA
2.2V      -36.89mA   -36.86mA   -38.1mA
[POWER Clamp]
|   Voltage   I(typ)   I(min)   I(max)
-1.1V     3.033mA    3.633mA    2.184mA
-1.044V   2.381mA    2.967mA    1.653mA
-984.5mV  1.782mA    2.31mA     1.205mA
-915.2mV  1.224mA    1.64mA     781.2uA
-855.8mV  837.7uA    1.172mA    552.1uA
-783.2mV  462uA      719.7uA    402.4uA
-710.6mV  232.4uA    359uA      273.1uA
-651.2mV  138.6uA    162.3uA    181.2uA
-591.8mV  77.91uA    64.79uA    105.5uA
-489.5mV  17.76uA    10.84uA    22.47uA
-374mV    1.378uA    994nA      1.124uA
2.2V      0A         0A         0A
[Ramp]
|   typ   min   max
| 20% - 80%
dV/dt_r   201.73m/40.29p   194.47m/44.40p   218.82m/35.16p
dV/dt_f   161.56m/61.44p   146.48m/71.02p   188.38m/51.94p
| 25% - 75%
|dV/dt_r   168.11m/32.06p   162.06m/35.37p   182.35m/27.95p
|dV/dt_f   134.64m/48.80p   122.07m/56.58p   156.98m/41.19p
R_load = 50
[Rising Waveform]
R_fixture = 50
V_fixture = 0.0
|   Time   V(typ)   V(min)   V(max)
0s        626.5uV    550.9uV    452.4uV
57ps      642.3uV    1.141uV    8.183mV
66ps      3.345mV    -42.18uV   43.15mV
78ps      14.19mV    2.591mV    131mV
92ps      73.56mV    9.924mV    229.1mV
104ps     148.2mV    33.99mV    286.1mV
133ps     274.4mV    175.9mV    347.2mV
160ps     318.6mV    269.4mV    361.3mV
192ps     333.3mV    311.2mV    364.6mV
364ps     336.8mV    324.7mV    365.2mV
[Falling Waveform]
R_fixture   = 50
V_fixture   = 1.1
V_fixture_min = 1.06
V_fixture_max = 1.17
|   Time   V(typ)   V(min)   V(max)
0s        1.1V       1.06V      1.17V
72ps      1.099V     1.061V     1.161V
79ps      1.097V     1.06V      1.14V
93ps      1.089V     1.056V     1.073V
120ps     1.006V     1.042V     962.5mV
142ps     938.9mV    991.4mV    911.7mV
164ps     893.7mV    934.6mV    884.4mV
199ps     855.9mV    872.5mV    865.6mV
236ps     839.9mV    839.8mV    859mV
364ps     830.7mV    815.9mV    856mV
[Rising Waveform]
R_fixture   = 50
V_fixture   = 1.1
V_fixture_min = 1.06
V_fixture_max = 1.17
|   Time   V(typ)   V(min)   V(max)
0s        830.4mV    814.6mV    855.9mV
52ps      826.9mV    812.7mV    860.1mV
62ps      831.2mV    809.7mV    888.7mV
76ps      868.3mV    816.1mV    970.7mV
90ps      934.5mV    851.5mV    1.034V
110ps     1.002V     929.8mV    1.09V
146ps     1.06V      1.007V     1.139V
181ps     1.083V     1.037V     1.157V
220ps     1.093V     1.051V     1.165V
364ps     1.1V       1.06V      1.17V
[Falling Waveform]
R_fixture = 50
V_fixture = 0.0
|   Time   V(typ)   V(min)   V(max)
0s        336.9mV    324.8mV    365.2mV
57ps      342mV      326mV      367.3mV
75ps      335.1mV    335mV      280.7mV
87ps      287.6mV    328mV      178.4mV
99ps      209.4mV    291.4mV    113.1mV
115ps     120.5mV    210.9mV    62.73mV
136ps     58.34mV    113.4mV    29.23mV
163ps     23.51mV    46.97mV    11.19mV
199ps     7.391mV    14.92mV    3.368mV
364ps     741.8uV    731.2uV    490.5uV
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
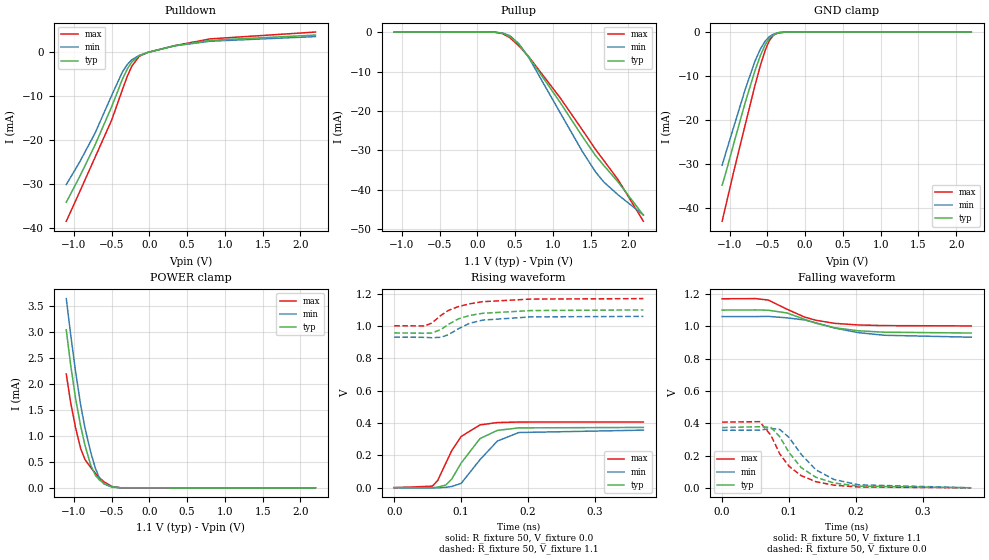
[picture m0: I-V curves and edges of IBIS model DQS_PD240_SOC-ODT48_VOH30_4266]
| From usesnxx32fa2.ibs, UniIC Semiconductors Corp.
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| DQS_PD240_SOC-ODT48_VOH30_4266
| (240 Ohm Pulldown, 48 Ohm System ODT Setting, VOH=VDDQ/3.0, 3200-4266Mbps)
[Model]   DQS_PD240_SOC-ODT48_VOH30_4266
Model_type   I/O
Vinl = 123.333mV
Vinh = 243.333mV
Vmeas = 183.333mV
Vref = 0.0mV
Cref = 0.0pF
Rref = 48.000Ohm
|   typ   min   max
|C_comp   0.849pF   0.799pF   0.899pF
C_comp_pullup   0.4245pF   0.3995pF   0.4495pF
C_comp_pulldown   0.4245pF   0.3995pF   0.4495pF
| Note: C_comp changes when the ODT circuit is enabled.
[Model Spec]
| Input threshold voltage corners
Vinl   0.1233V   0.1167V   0.1350V
Vinh   0.2433V   0.2367V   0.2550V
| Measurement voltage corners
Vmeas   0.1833V   0.1767V   0.1950V
| Timing spec test load voltage corners
Vref   0.0000V   0.0000V   0.0000V
| Dynamic Overshoot Parameters from LPDDR4 Specification
D_overshoot_ampl_h   0.30   NA   NA
D_overshoot_ampl_l   0.30   NA   NA
D_overshoot_area_h   0.1n   NA   NA
D_overshoot_area_l   0.1n   NA   NA
[Voltage Range]   1.1000V   1.0600V   1.1700V
[Pullup Reference]   1.1000V   1.0600V   1.1700V
| Junction Temperature (Ambient temp is 35C typ 95C min -40C max)
[Temperature Range]   50.0   110.0   -40.0
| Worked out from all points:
|   slope of the pulldown table from 0 to 0.165 V, typ, clamps not added: 222 ohm
|   slope of the pullup table from 0 to 0.165 V, typ, clamps not added: 15.7 kohm
|   GND clamp passes 1 mA (typ) near -0.45 V on its own axis
|   POWER clamp passes 1 mA (typ) near -0.88 V on its own axis
|   rising waveform, R_fixture 50, V_fixture 0.0: 20-80 % time 37.1ps typ, 41.9ps min, 32.4ps max; typ from 0.001 V to 0.373 V
|   falling waveform, R_fixture 50, V_fixture 1.1: 20-80 % time 69.5ps typ, 80.6ps min, 59.2ps max; typ from 1.1 V to 0.958 V
|   rising waveform, R_fixture 50, V_fixture 1.1: 20-80 % time 46.9ps typ, 43.9ps min, 49ps max; typ from 0.958 V to 1.1 V
|   falling waveform, R_fixture 50, V_fixture 0.0: 20-80 % time 46.6ps typ, 50.8ps min, 42.7ps max; typ from 0.373 V to 0.001 V
[Pulldown]
|   Voltage   I(typ)   I(min)   I(max)
-1.1V     -34.14mA   -30.13mA   -38.47mA
-925.1mV  -28.42mA   -25.08mA   -31.88mA
-720.5mV  -21.19mA   -18.51mA   -24.01mA
-499.4mV  -12.48mA   -9.914mA   -15.51mA
-357.5mV  -6.246mA   -4.591mA   -8.628mA
-291.5mV  -3.863mA   -2.855mA   -5.528mA
-232.1mV  -2.3mA     -1.803mA   -3.23mA
-133.1mV  -878.4uA   -794.1uA   -994.8uA
-17.6mV   -114uA     -109.1uA   -105.8uA
338.8mV   1.399mA    1.377mA    1.431mA
807.4mV   2.621mA    2.422mA    2.952mA
2.2V      3.814mA    3.471mA    4.502mA
[GND Clamp]
|   Voltage   I(typ)   I(min)   I(max)
-1.1V     -34.74mA   -30.21mA   -42.91mA
-1.05V    -31.86mA   -27.33mA   -39.27mA
-944.9mV  -25.23mA   -21.44mA   -31.55mA
-793.1mV  -15.92mA   -12.96mA   -20.95mA
-667.7mV  -8.907mA   -6.722mA   -12.29mA
-591.8mV  -5.255mA   -3.789mA   -7.492mA
-525.8mV  -2.766mA   -1.974mA   -3.964mA
-473mV    -1.425mA   -1.032mA   -1.887mA
-416.9mV  -600.2uA   -440.5uA   -664.9uA
-350.9mV  -166.8uA   -126.3uA   -148.2uA
-248.6mV  -12.31uA   -11.02uA   -7.125uA
2.2V      0A         0A         0A
[Pullup]
|   Voltage   I(typ)   I(min)   I(max)
-1.1V     5.229uA    8.059uA    2.358uA
233.2mV   -40.35uA   -40.62uA   -42.13uA
335.5mV   -286.4uA   -235.7uA   -391.6uA
431.2mV   -1.117mA   -909.9uA   -1.417mA
550mV     -3.186mA   -2.926mA   -3.464mA
682mV     -6.308mA   -6.472mA   -6.26mA
1.091V    -17.65mA   -20.22mA   -16.5mA
1.391V    -26.44mA   -30.26mA   -24.79mA
1.566V    -31.33mA   -35.46mA   -29.76mA
1.675V    -33.81mA   -38.02mA   -32.54mA
1.867V    -38.07mA   -41.32mA   -37.5mA
2.2V      -46.44mA   -46.37mA   -47.99mA
[POWER Clamp]
|   Voltage   I(typ)   I(min)   I(max)
-1.1V     3.033mA    3.633mA    2.184mA
-1.044V   2.381mA    2.967mA    1.653mA
-977.9mV  1.723mA    2.241mA    1.16mA
-908.6mV  1.177mA    1.583mA    748uA
-852.5mV  818.4uA    1.149mA    543.5uA
-776.6mV  434.1uA    683.2uA    390.2uA
-713.9mV  239.2uA    373uA      278.6uA
-661.1mV  151.1uA    187.5uA    195.4uA
-598.4mV  83.65uA    72.01uA    113uA
-492.8mV  18.96uA    11.63uA    24.05uA
-383.9mV  1.761uA    1.219uA    1.465uA
2.2V      0A         0A         0A
[Ramp]
|   typ   min   max
| 20% - 80%
dV/dt_r   223.43m/37.14p   213.40m/41.93p   243.75m/32.37p
dV/dt_f   85.15m/69.43p   76.64m/80.24p   100.80m/58.91p
| 25% - 75%
|dV/dt_r   186.19m/29.60p   177.83m/33.34p   203.13m/25.80p
|dV/dt_f   70.96m/55.26p   63.87m/63.47p   84.00m/46.80p
R_load = 50
[Rising Waveform]
R_fixture = 50
V_fixture = 0.0
|   Time   V(typ)   V(min)   V(max)
0s        944.6uV    840.9uV    678.4uV
57ps      597.9uV    -79.9uV    9.862mV
65ps      3.879mV    -354.8uV   45.63mV
77ps      16.92mV    2.586mV    151.7mV
86ps      54.38mV    7.944mV    230.4mV
100ps     153.3mV    27.31mV    317.4mV
128ps     304mV      173.5mV    388.7mV
154ps     354.9mV    288.7mV    403.5mV
186ps     370.4mV    341.7mV    406.6mV
372ps     373.3mV    356.5mV    406.9mV
[Falling Waveform]
R_fixture   = 50
V_fixture   = 1.1
V_fixture_min = 1.06
V_fixture_max = 1.17
|   Time   V(typ)   V(min)   V(max)
0s        1.1V       1.06V      1.17V
50ps      1.101V     1.06V      1.171V
69ps      1.099V     1.061V     1.162V
97ps      1.082V     1.052V     1.105V
123ps     1.043V     1.039V     1.057V
140ps     1.019V     1.021V     1.037V
168ps     990.7mV    989.1mV    1.018V
203ps     972.1mV    960.7mV    1.008V
242ps     963.2mV    944.3mV    1.004V
372ps     958.1mV    932.3mV    1.002V
[Rising Waveform]
R_fixture   = 50
V_fixture   = 1.1
V_fixture_min = 1.06
V_fixture_max = 1.17
|   Time   V(typ)   V(min)   V(max)
0s        957.9mV    931.6mV    1.002V
45ps      956mV      930.6mV    1.001V
56ps      956.9mV    928mV      1.018V
70ps      979.2mV    930.9mV    1.067V
81ps      1.011V     947.2mV    1.097V
96ps      1.045V     984.1mV    1.121V
113ps     1.066V     1.018V     1.138V
132ps     1.079V     1.037V     1.151V
204ps     1.096V     1.057V     1.167V
372ps     1.1V       1.06V      1.17V
[Falling Waveform]
R_fixture = 50
V_fixture = 0.0
|   Time   V(typ)   V(min)   V(max)
0s        373.4mV    356.7mV    407mV
56ps      378.7mV    357.3mV    410.2mV
73ps      374.3mV    367.6mV    324.8mV
86ps      317.1mV    361.9mV    210.8mV
100ps     218.5mV    311.8mV    133.7mV
118ps     125.9mV    208.4mV    76.18mV
140ps     66mV       112.3mV    38.75mV
167ps     30.57mV    52.38mV    17.18mV
204ps     11.13mV    19.29mV    5.941mV
372ps     1.102mV    1.123mV    726.4uV
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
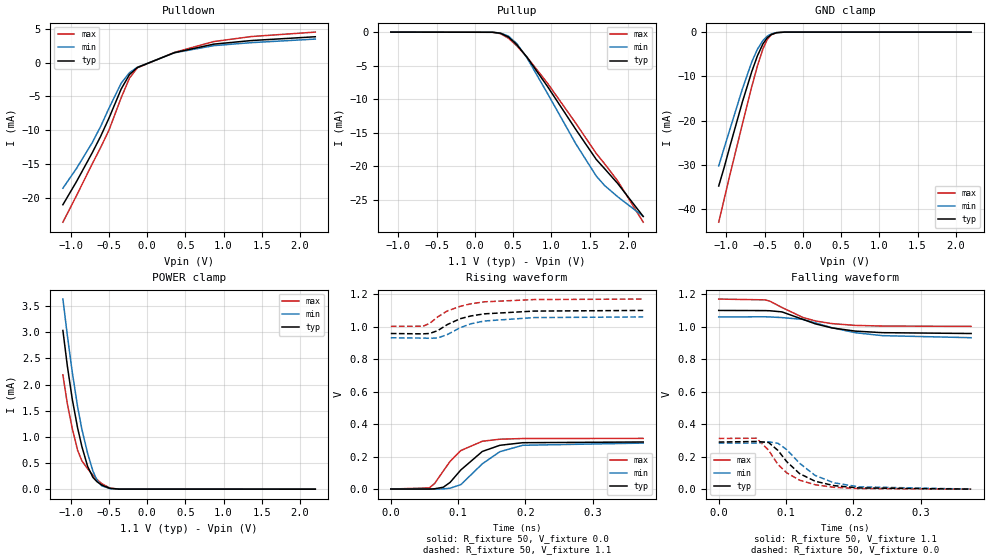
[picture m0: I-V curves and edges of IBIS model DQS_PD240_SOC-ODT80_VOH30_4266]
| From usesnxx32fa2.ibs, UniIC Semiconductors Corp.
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| DQS_PD240_SOC-ODT80_VOH30_4266
| (240 Ohm Pulldown, 80 Ohm System ODT Setting, VOH=VDDQ/3.0, 3200-4266Mbps)
[Model]   DQS_PD240_SOC-ODT80_VOH30_4266
Model_type   I/O
Vinl = 123.333mV
Vinh = 243.333mV
Vmeas = 183.333mV
Vref = 0.0mV
Cref = 0.0pF
Rref = 80.000Ohm
|   typ   min   max
|C_comp   0.849pF   0.799pF   0.899pF
C_comp_pullup   0.4245pF   0.3995pF   0.4495pF
C_comp_pulldown   0.4245pF   0.3995pF   0.4495pF
| Note: C_comp changes when the ODT circuit is enabled.
[Model Spec]
| Input threshold voltage corners
Vinl   0.1233V   0.1167V   0.1350V
Vinh   0.2433V   0.2367V   0.2550V
| Measurement voltage corners
Vmeas   0.1833V   0.1767V   0.1950V
| Timing spec test load voltage corners
Vref   0.0000V   0.0000V   0.0000V
| Dynamic Overshoot Parameters from LPDDR4 Specification
D_overshoot_ampl_h   0.30   NA   NA
D_overshoot_ampl_l   0.30   NA   NA
D_overshoot_area_h   0.1n   NA   NA
D_overshoot_area_l   0.1n   NA   NA
[Voltage Range]   1.1000V   1.0600V   1.1700V
[Pullup Reference]   1.1000V   1.0600V   1.1700V
| Junction Temperature (Ambient temp is 35C typ 95C min -40C max)
[Temperature Range]   50.0   110.0   -40.0
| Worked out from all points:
|   slope of the pulldown table from 0 to 0.165 V, typ, clamps not added: 224 ohm
|   slope of the pullup table from 0 to 0.165 V, typ, clamps not added: 26 kohm
|   GND clamp passes 1 mA (typ) near -0.45 V on its own axis
|   POWER clamp passes 1 mA (typ) near -0.88 V on its own axis
|   rising waveform, R_fixture 50, V_fixture 0.0: 20-80 % time 44.2ps typ, 47.4ps min, 38.1ps max; typ from 0.001 V to 0.29 V
|   falling waveform, R_fixture 50, V_fixture 1.1: 20-80 % time 67.6ps typ, 76.3ps min, 57.2ps max; typ from 1.1 V to 0.958 V
|   rising waveform, R_fixture 50, V_fixture 1.1: 20-80 % time 51.6ps typ, 51.6ps min, 50.7ps max; typ from 0.958 V to 1.1 V
|   falling waveform, R_fixture 50, V_fixture 0.0: 20-80 % time 47.9ps typ, 52.5ps min, 43.7ps max; typ from 0.29 V to 0.001 V
[Pulldown]
|   Voltage   I(typ)   I(min)   I(max)
-1.1V     -20.98mA   -18.54mA   -23.56mA
-921.8mV  -17.56mA   -15.62mA   -19.63mA
-717.2mV  -13.33mA   -11.83mA   -14.97mA
-605mV    -10.85mA   -9.399mA   -12.5mA
-496.1mV  -8.165mA   -6.7mA     -9.924mA
-337.7mV  -3.889mA   -3.033mA   -5.178mA
-228.8mV  -1.76mA    -1.483mA   -2.28mA
-126.5mV  -725.6uA   -684.1uA   -773.8uA
358.6mV   1.469mA    1.444mA    1.507mA
873.4mV   2.725mA    2.503mA    3.106mA
1.365V    3.253mA    2.945mA    3.846mA
2.2V      3.814mA    3.471mA    4.502mA
[GND Clamp]
|   Voltage   I(typ)   I(min)   I(max)
-1.1V     -34.74mA   -30.21mA   -42.91mA
-1.027V   -30.44mA   -26.04mA   -37.57mA
-951.5mV  -25.64mA   -21.81mA   -32.03mA
-789.8mV  -15.72mA   -12.78mA   -20.72mA
-667.7mV  -8.907mA   -6.722mA   -12.29mA
-595.1mV  -5.4mA     -3.899mA   -7.688mA
-522.5mV  -2.665mA   -1.903mA   -3.81mA
-466.4mV  -1.3mA     -943.5uA   -1.69mA
-413.6mV  -567uA     -419.2uA   -621.6uA
-344.3mV  -143.7uA   -109.8uA   -123.9uA
-238.7mV  -9.093uA   -8.569uA   -4.992uA
2.2V      0A         0A         0A
[Pullup]
|   Voltage   I(typ)   I(min)   I(max)
-1.1V     3.138uA    4.837uA    1.414uA
229.9mV   -22.65uA   -22.91uA   -23.3uA
332.2mV   -161.3uA   -134.3uA   -221.5uA
437.8mV   -720uA     -590.5uA   -906.3uA
546.7mV   -1.865mA   -1.708mA   -2.036mA
682mV     -3.775mA   -3.872mA   -3.748mA
949.3mV   -8.129mA   -9.173mA   -7.639mA
1.319V    -14.54mA   -16.68mA   -13.61mA
1.586V    -19.01mA   -21.49mA   -18.12mA
1.695V    -20.39mA   -22.9mA    -19.65mA
1.867V    -22.61mA   -24.59mA   -22.23mA
2.2V      -27.52mA   -27.51mA   -28.38mA
[POWER Clamp]
|   Voltage   I(typ)   I(min)   I(max)
-1.1V     3.033mA    3.633mA    2.184mA
-1.041V   2.345mA    2.929mA    1.625mA
-977.9mV  1.723mA    2.241mA    1.161mA
-908.6mV  1.177mA    1.582mA    747.8uA
-852.5mV  818.3uA    1.149mA    543.6uA
-776.6mV  434.1uA    683.2uA    390.2uA
-707.3mV  225.5uA    345.4uA    267.6uA
-654.5mV  142.7uA    170.4uA    185.9uA
-591.8mV  77.92uA    64.8uA     105.5uA
-486.2mV  16.82uA    10.15uA    20.98uA
-367.4mV  1.202uA    882.2nA    944.9nA
2.2V      0A         0A         0A
[Ramp]
|   typ   min   max
| 20% - 80%
dV/dt_r   173.76m/44.16p   169.72m/47.45p   187.20m/38.06p
dV/dt_f   85.14m/67.44p   76.63m/76.56p   100.78m/57.77p
| 25% - 75%
|dV/dt_r   144.80m/35.24p   141.43m/37.81p   156.00m/30.30p
|dV/dt_f   70.95m/53.54p   63.86m/60.86p   83.99m/45.86p
R_load = 50
[Rising Waveform]
R_fixture = 50
V_fixture = 0.0
|   Time   V(typ)   V(min)   V(max)
0s        567.9uV    500.8uV    410.1uV
57ps      284.1uV    -41.35uV   7.409mV
65ps      2.066mV    -310.2uV   34.02mV
78ps      11.61mV    1.584mV    111.8mV
88ps      41.15mV    5.369mV    170.5mV
104ps     117.9mV    27.39mV    237.5mV
136ps     232mV      155.9mV    294.7mV
162ps     269.7mV    230.4mV    307.3mV
196ps     285.7mV    269.8mV    311.4mV
375ps     290.2mV    283.4mV    312.4mV
[Falling Waveform]
R_fixture   = 50
V_fixture   = 1.1
V_fixture_min = 1.06
V_fixture_max = 1.17
|   Time   V(typ)   V(min)   V(max)
0s        1.1V       1.06V      1.17V
69ps      1.099V     1.061V     1.165V
76ps      1.098V     1.06V      1.157V
94ps      1.091V     1.056V     1.118V
125ps     1.045V     1.045V     1.057V
144ps     1.017V     1.023V     1.035V
168ps     992.6mV    993.8mV    1.019V
203ps     972.8mV    963mV      1.008V
243ps     963.3mV    944.9mV    1.004V
375ps     958.1mV    932.3mV    1.002V
[Rising Waveform]
R_fixture   = 50
V_fixture   = 1.1
V_fixture_min = 1.06
V_fixture_max = 1.17
|   Time   V(typ)   V(min)   V(max)
0s        957.9mV    931.6mV    1.002V
48ps      955.8mV    930mV      1.003V
58ps      958.3mV    928.1mV    1.021V
70ps      976.5mV    931mV      1.061V
84ps      1.013V     951.4mV    1.097V
103ps     1.049V     993.6mV    1.125V
119ps     1.066V     1.018V     1.141V
139ps     1.079V     1.035V     1.153V
213ps     1.096V     1.056V     1.167V
375ps     1.1V       1.06V      1.17V
[Falling Waveform]
R_fixture = 50
V_fixture = 0.0
|   Time   V(typ)   V(min)   V(max)
0s        290.3mV    283.5mV    312.5mV
56ps      294mV      284mV      313.9mV
74ps      287.9mV    291.6mV    240.7mV
88ps      238.9mV    282.9mV    152.4mV
101ps     169.9mV    243.8mV    101mV
120ps     96.52mV    160.5mV    56.16mV
143ps     49.59mV    85.59mV    27.73mV
171ps     22.4mV     39.65mV    12.04mV
208ps     8.14mV     14.83mV    4.176mV
375ps     736uV      778.8uV    468.8uV
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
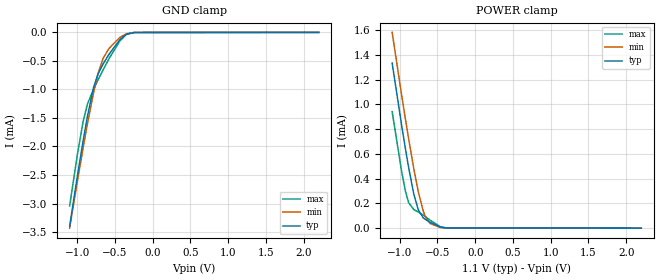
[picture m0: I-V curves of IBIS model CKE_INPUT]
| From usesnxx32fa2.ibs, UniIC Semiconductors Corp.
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| CKE_INPUT
[Model]   CKE_INPUT
Model_type   Input
Vinl = 275.000mV
Vinh = 825.000mV
|   typ   min   max
|C_comp   0.683pF   0.633pF   0.733pF
C_comp_power_clamp   0.3415pF   0.3165pF   0.3665pF
C_comp_gnd_clamp   0.3415pF   0.3165pF   0.3665pF
[Model Spec]
| Input threshold voltage corners
Vinl   0.2750V   0.2650V   0.2925V
Vinh   0.8250V   0.7950V   0.8775V
| Dynamic Overshoot Parameters from LPDDR4 Specification
D_overshoot_ampl_h   0.35   NA   NA
D_overshoot_ampl_l   0.35   NA   NA
D_overshoot_area_h   0.8n   NA   NA
D_overshoot_area_l   0.8n   NA   NA
[Voltage Range]   1.1000V   1.0600V   1.1700V
| Junction Temperature (Ambient temp is 35C typ 95C min -40C max)
[Temperature Range]   50.0   110.0   -40.0
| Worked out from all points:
|   GND clamp passes 1 mA (typ) near -0.79 V on its own axis
|   POWER clamp passes 1 mA (typ) near -1.02 V on its own axis
[GND Clamp]
|   Voltage   I(typ)   I(min)   I(max)
-1.1V     -3.395mA   -3.431mA   -3.04mA
-997.7mV  -2.519mA   -2.612mA   -2.141mA
-921.8mV  -1.901mA   -2.026mA   -1.563mA
-865.7mV  -1.479mA   -1.612mA   -1.26mA
-783.2mV  -964uA     -1.056mA   -995.7uA
-723.8mV  -727.2uA   -718.2uA   -833.2uA
-654.5mV  -547.2uA   -448.4uA   -650.8uA
-578.6mV  -384.1uA   -281.9uA   -460.6uA
-436.7mV  -130.3uA   -89.38uA   -153.3uA
-347.6mV  -33.73uA   -24.52uA   -31.36uA
-245.3mV  -2.391uA   -2.529uA   -1.106uA
2.2V      0A         0A         0A
[POWER Clamp]
|   Voltage   I(typ)   I(min)   I(max)
-1.1V     1.334mA    1.582mA    941.4uA
-971.3mV  818.8uA    1.063mA    446.7uA
-921.8mV  632.4uA    871.8uA    292.6uA
-882.2mV  491.2uA    723.9uA    206.6uA
-812.9mV  274.9uA    478.4uA    149.7uA
-753.5mV  146.9uA    294.1uA    130.1uA
-687.5mV  83.23uA    136.1uA    105.4uA
-654.5mV  67.82uA    84.67uA    91.08uA
-598.4mV  47.31uA    37.61uA    64.8uA
-459.8mV  8.605uA    4.92uA     9.861uA
-370.7mV  1.046uA    744.1nA    836.5nA
2.2V      0A         0A         0A
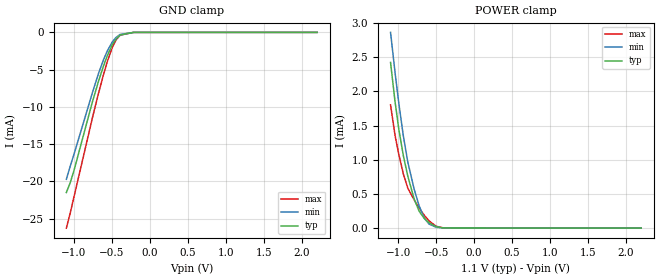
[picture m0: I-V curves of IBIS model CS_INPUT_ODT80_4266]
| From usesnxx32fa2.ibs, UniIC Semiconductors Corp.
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| CS_INPUT_ODT80_4266 (with 80ohm ODT, 3200-4266Mbps)
[Model]   CS_INPUT_ODT80_4266
Model_type   Input
Vinl = 110.833mV
Vinh = 255.833mV
|   typ   min   max
|C_comp   0.640pF   0.592pF   0.695pF
C_comp_power_clamp   0.3200pF   0.2960pF   0.3475pF
C_comp_gnd_clamp   0.3200pF   0.2960pF   0.3475pF
| Note: C_comp changes when the ODT circuit is enabled.
[Model Spec]
| Input threshold voltage corners
Vinl   0.1108V   0.1042V   0.1225V
Vinh   0.2558V   0.2492V   0.2675V
| Dynamic Overshoot Parameters from LPDDR4 Specification
D_overshoot_ampl_h   0.30   NA   NA
D_overshoot_ampl_l   0.30   NA   NA
D_overshoot_area_h   0.1n   NA   NA
D_overshoot_area_l   0.1n   NA   NA
[Voltage Range]   1.1000V   1.0600V   1.1700V
[POWER Clamp Reference]   1.1000V   1.0600V   1.1700V
| Junction Temperature (Ambient temp is 35C typ 95C min -40C max)
[Temperature Range]   50.0   110.0   -40.0
[Add Submodel]
| Submodel Name   Mode
80ohm_ODT_4266   Non-Driving
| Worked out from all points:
|   GND clamp passes 1 mA (typ) near -0.45 V on its own axis
|   POWER clamp passes 1 mA (typ) near -0.92 V on its own axis
[GND Clamp]
|   Voltage   I(typ)   I(min)   I(max)
-1.1V     -21.5mA    -19.73mA   -26.28mA
-1.05V    -20.21mA   -18mA      -24.3mA
-1.001V   -18.6mA    -16.41mA   -22.14mA
-756.8mV  -9.322mA   -8.095mA   -11.46mA
-674.3mV  -6.479mA   -5.435mA   -8.089mA
-611.6mV  -4.527mA   -3.692mA   -5.688mA
-558.8mV  -3.075mA   -2.45mA    -3.855mA
-496.1mV  -1.68mA    -1.302mA   -2.043mA
-446.6mV  -895.4uA   -681.7uA   -1.019mA
-390.5mV  -360.6uA   -270.9uA   -358.3uA
-215.6mV  -4.605uA   -4.495uA   -2.165uA
2.2V      0A         0A         0A
[POWER Clamp]
|   Voltage   I(typ)   I(min)   I(max)
-1.1V     2.422mA    2.862mA    1.802mA
-1.041V   1.851mA    2.277mA    1.359mA
-991.1mV  1.446mA    1.826mA    1.078mA
-931.7mV  1.06mA     1.348mA    793.2uA
-872.3mV  758.1uA    963.8uA    583.4uA
-789.8mV  428.8uA    572.2uA    413.9uA
-723.8mV  247.8uA    326.1uA    295.1uA
-654.5mV  141uA      142.6uA    185.5uA
-591.8mV  77.55uA    58.75uA    105.2uA
-499.4mV  21.2uA     12.49uA    27.17uA
-400.4mV  2.408uA    1.511uA    2.096uA
2.2V      0A         0A         0A
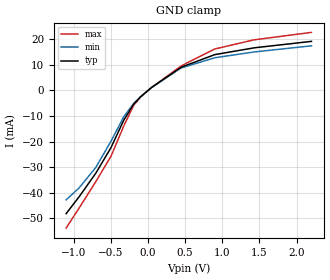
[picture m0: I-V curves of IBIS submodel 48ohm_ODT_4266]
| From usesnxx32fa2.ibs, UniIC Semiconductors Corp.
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| SUBMODEL 48ohm_ODT_4266
[Submodel]   48ohm_ODT_4266
Submodel_type   Dynamic_clamp
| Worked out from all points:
|   GND clamp passes 1 mA (typ) near -0.04 V on its own axis
[GND Clamp]
|   Voltage   I(typ)   I(min)   I(max)
-1.1V     -48.22mA   -42.84mA   -53.87mA
-925.1mV  -41.62mA   -38.14mA   -46.03mA
-700.7mV  -32.39mA   -30.14mA   -35.69mA
-496.1mV  -22.37mA   -19.88mA   -25.76mA
-324.5mV  -11.66mA   -10.3mA    -13.92mA
-192.5mV  -5.411mA   -5.152mA   -5.91mA
-96.8mV   -2.481mA   -2.449mA   -2.483mA
48.4mV    1.125mA    1.121mA    1.121mA
447.7mV   9.071mA    8.78mA     9.581mA
899.8mV   14mA       12.77mA    16.21mA
1.428V    16.65mA    15.04mA    19.78mA
2.2V      19.18mA    17.44mA    22.7mA
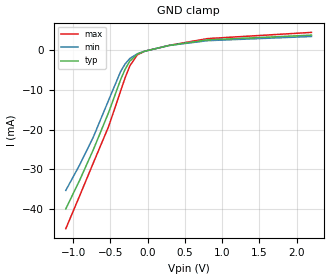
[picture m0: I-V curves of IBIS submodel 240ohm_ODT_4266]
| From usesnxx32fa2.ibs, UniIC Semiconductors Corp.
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| SUBMODEL 240ohm_ODT_4266
[Submodel]   240ohm_ODT_4266
Submodel_type   Dynamic_clamp
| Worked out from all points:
|   GND clamp passes 1 mA (typ) near -0.14 V on its own axis
[GND Clamp]
|   Voltage   I(typ)   I(min)   I(max)
-1.1V     -39.98mA   -35.33mA   -44.98mA
-915.2mV  -32.82mA   -28.95mA   -36.75mA
-730.4mV  -25.07mA   -21.88mA   -28.4mA
-525.8mV  -15.73mA   -12.63mA   -19.27mA
-364.1mV  -7.424mA   -5.38mA    -10.31mA
-304.7mV  -4.835mA   -3.484mA   -6.995mA
-238.7mV  -2.707mA   -2.048mA   -3.904mA
-139.7mV  -998.6uA   -883.6uA   -1.173mA
-40.7mV   -250.8uA   -237.1uA   -239.6uA
289.3mV   1.217mA    1.202mA    1.235mA
804.1mV   2.615mA    2.418mA    2.942mA
2.2V      3.814mA    3.471mA    4.502mA
